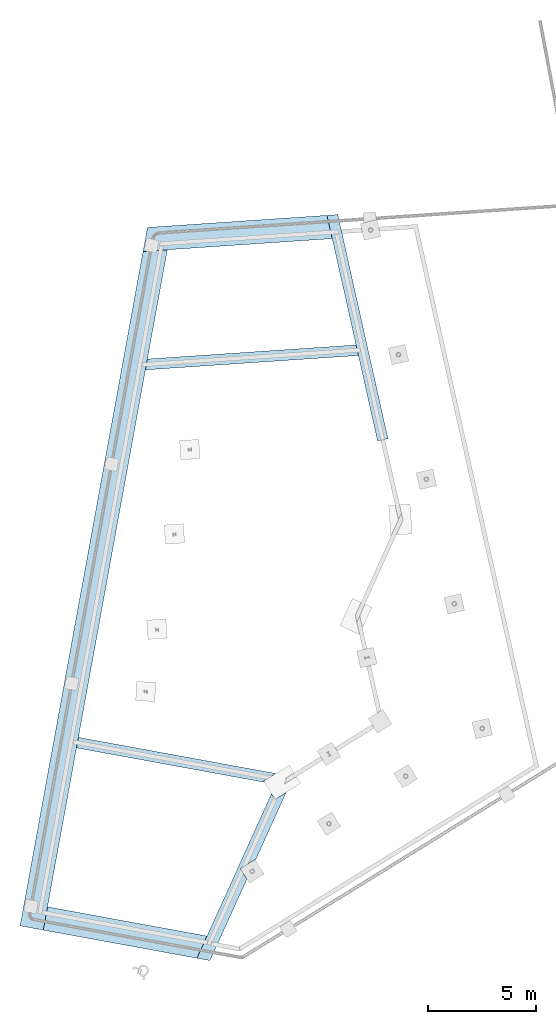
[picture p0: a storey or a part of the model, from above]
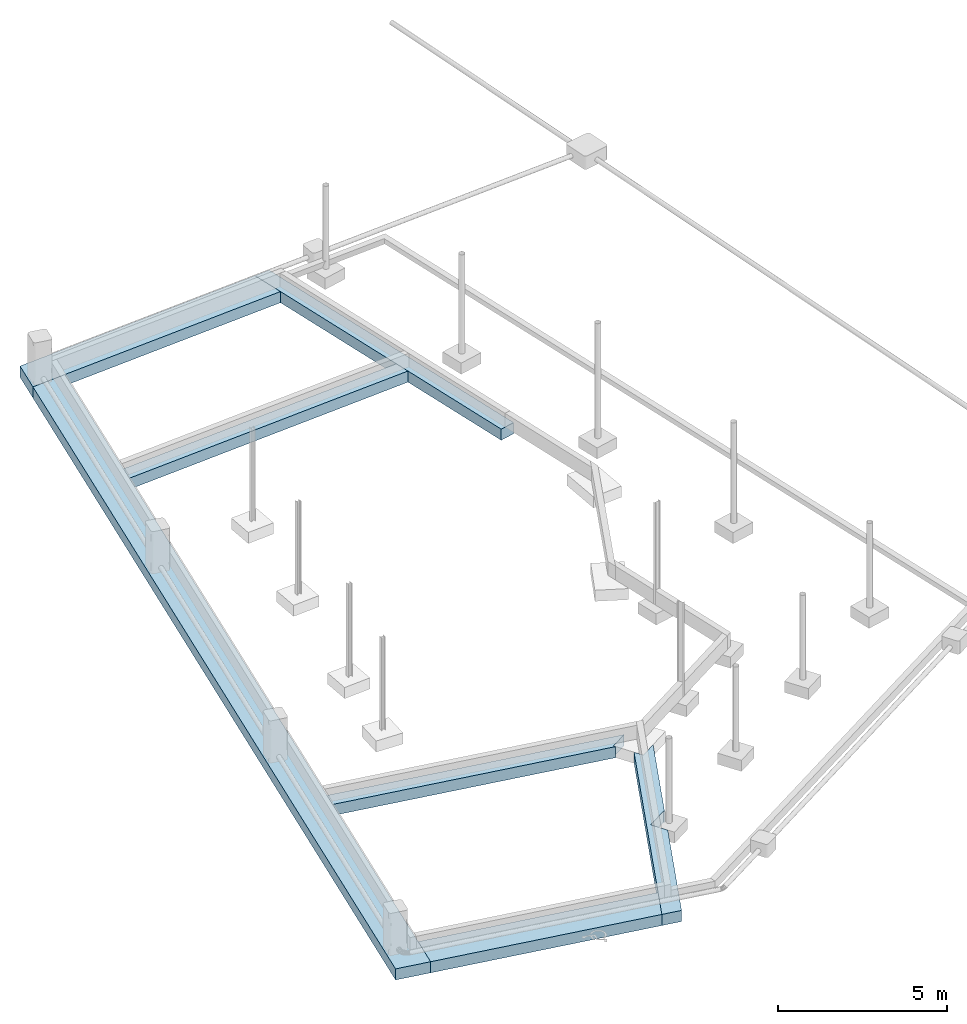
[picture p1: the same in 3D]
Properties of the parts of a building model (IFC2X3), part 1 of 5

# File
Description: ViewDefinition [CoordinationView_V2.0, QuantityTakeOffAddOnView]
File name: Maison des activités
Time: 2020-01-26T12:22:14
Written by: The EXPRESS Data Manager Version 5.02.0100.07 : 28 Aug 2013
Made in: 20180328_1600(x64) - Exporter 19.1.0.0 - Interface alternative d'export 19.1.0.0
Comment: STEP Physical File produced by: The EXPRESS Data Manager Version 5.02.0100.07 : 28 Aug 2013 * Module: EDMstepFileFactory/EDMstandAlone * Creation date: Sun Jan 26 12:22:14 2020 * Host: DESKTOP-D25JFNO * Database: C:\Users\MA392~1.JEA\AppData\Local\Temp\{6E2AF56B-D0A0-4CB7-A6A2-1DAB4A0019D9}\ifc * Database version: 5507 * Database creation date: Sun Jan 26 12:21:57 2020 * Schema: IFC2X3 * Model: DataRepository.ifc * Model creation date: Sun Jan 26 12:21:57 2020 * Header model: DataRepository.ifc_HeaderModel * Header model creation date: Sun Jan 26 12:21:57 2020 * EDMuser: sdai-user * EDMgroup: sdai-group * License ID and type: 5605 : Permanent license. Expiry date: * EDMstepFileFactory options: 020000

# IfcProject, Maison des activités
LongName: Construction d'une maison des activités; Phase: PRO

# IfcSite, Surface:1027720
RefLatitude: 43, 35, 59, 999999; RefLongitude: 1, 23, 59, 999999; RefElevation: 1.23108e-26 cm
Autre - Catégorie: Topographie; Déblais: 1000.42 m3; Déblais/remblais net: -831.129 m3; Remblais: 169.291 m3
Cotes - Surface: 22180.9 m2; Surface projetée: 21753.3 m2
Données d'identification - Nom: Terrain
Matériaux et finitions - Matériau: Site - Herbe existant
Phase de construction - Phase de création: Projet

# IfcBuilding
Pset_BuildingCommon - NumberOfStoreys: 4
Autre - Adresse du projet: LE P I G E O N N I E R 1 2 7 2 0 V E Y R E AU; Catégorie: Informations sur le projet; Etat du projet: PRO; Nom du client: Com. de Communes de Millau Grands Causses; Nom du projet: Construction d'une maison des activités; Numéro de projet: Maison des activités
Données d'identification - Auteur: Team TEB LP Millau

# IfcBuildingStorey: Niveau:Niveau (4)
Autre - Catégorie: Niveaux; Famille: Niveau: Niveau; Famille et type: Niveau: Niveau; ID du type: Niveau: Niveau; Type: Niveau: Niveau
Cotes - Hauteur de calcul: 0 cm
Données d'identification - Structure: no
Autre(Type) - Catégorie: Niveaux; Nom de la famille: Niveau
Contraintes(Type) - Base de l'élévation: Point de base du projet
Données d'identification(Type) - Nom du type: Niveau
Graphismes(Type) - Couleur: 16711680; Epaisseur des lignes: 1; Motif des lignes: Axes; Symbole: Repère de niveau - Demi-cercle: Arial 2mm; Valeur par défaut du symbole à l'extrémité 1: no; Valeur par défaut du symbole à l'extrémité 2: yes
Name | LongName | Elevation (cm) | Elévation (cm) | Etage de bâtiment | Nom
-1 Soubassement | -1 Soubassement | 86950 | 86700 | no | -2 Parking
0 RDC | 0 RDC | 87000 | 87000 | yes | 0 RDC
1 Toiture auvent | 1 Toiture auvent | 87229 | 87229 | yes | 1 Toiture auvent
2 Toiture batiment | 2 Toiture batiment | 87291 | 87291 | yes | 2 Toiture batiment

# IfcBeam: HEA260, HE-A:HEA260:1442058
In: 1 Toiture auvent
Type - PredefinedType: BEAM
Type - Analyse structurelle - Moment d'inertie de torsion: 0; Rayon d'inertie sectoriel: 0; Aire sectionnelle: 0.00868 m2; Module d'élasticité - axe faible: 0.000282 m3; Module d'élasticité - axe fort: 0.000836 m3; Module plastique - axe faible: 0.0004302 m3; Module plastique - axe fort: 0.0009198 m3; Moment d'inertie - axe faible: 0.00425213; Moment d'inertie - axe fort: 0.0121076; Périmètre: 0.451104 m2; Poids nominal: 668.811
Type - Autre - Catégorie: Ossature; Nom de la famille: HE-A
Type - Données d'identification - Identifiant du nom de la coupe: HEA260; Nom de code: EURONORM 53-62; DIN 1025-3; NF A 45-201; Nom du type: HEA260
Type - Géométrie de coupe structurelle - Centre de gravité horizontal: 13 cm; Centre de gravité vertical: 12.5 cm; Congé de l'âme: 2.4 cm; Epaisseur de l'aile: 1.25 cm; Epaisseur de l'âme: 0.75 cm; Hauteur: 25 cm; Largeur: 26 cm
Type - Structure - Forme de coupe: 8
Type - Pset_BeamCommon - IsExternal: no; Reference: HE-A:HEA260
Type - Pset_QuantityTakeOff - Reference: HE-A:HEA260
Type - Pset_ReinforcementBarPitchOfBeam - Reference: HE-A:HEA260
Material: Acier structurel - S235
BaseQuantities - GrossVolume: 0.0692697 m3; NetSurfaceArea: 12.4206 m2; NetVolume: 0.0725738 m3
Pset_BeamCommon - Span: 851.99 cm; Slope: 5.24864 deg
Pset_QuantityTakeOff - sets with these values: 2
Autre - Famille: HE-A: HEA260; Famille et type: HE-A: HEA260; ID du type: HE-A: HEA260; Type: HE-A: HEA260
Contraintes - Rotation de la section: 0 deg; Niveau de référence: Niveau: 1 Toiture auvent; Décalage du niveau d'arrivée: 125.927 cm; Décalage du niveau de départ: 47.9889 cm; Elévation du niveau de référence: 87229 cm
Cotes - Longueur: 851.99 cm; Volume: 0.0692697 m3
Matériaux et finitions - Matériau structurel: Acier structurel - S235
Phase de construction - Phase de création: Projet
Position géométrique - Etat de la jonction: Deux jonctions activées; Justification Y: Origine; Justification YZ: Uniforme; Justification Z: Haut; Valeur de décalage Y: 0 cm; Valeur de décalage Z: 0 cm
Structure - Activer le modèle analytique: yes; Emplacement du symbole filaire: Centre de la géométrie; Utilisation structurelle: Longeron; Longueur de coupe: 850.758 cm; Revêtement: -

# IfcBeam: IPE100 (9)
In: 1 Toiture auvent
Type - PredefinedType: BEAM
Type - Analyse structurelle - Moment d'inertie de torsion: 0; Rayon d'inertie sectoriel: 0; Aire sectionnelle: 0.00103 m2; Module d'élasticité - axe faible: 0.00000579 m3; Module d'élasticité - axe fort: 0.0000342 m3; Module plastique - axe faible: 0.0000092 m3; Module plastique - axe fort: 0.0000394 m3; Moment d'inertie - axe faible: 0.000018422; Moment d'inertie - axe fort: 0.000198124; Périmètre: 0.12192 m2; Poids nominal: 79.4336
Type - Autre - Catégorie: Ossature; Nom de la famille: IPE
Type - Données d'identification - Identifiant du nom de la coupe: IPE100; Nom de code: EURONORM 19-57; DIN 1025-5; NF A 45-205; Nom du type: IPE100
Type - Géométrie de coupe structurelle - Centre de gravité horizontal: 2.75 cm; Centre de gravité vertical: 5 cm; Congé de l'âme: 0.7 cm; Epaisseur de l'aile: 0.57 cm; Epaisseur de l'âme: 0.41 cm; Hauteur: 10 cm; Largeur: 5.5 cm
Type - Structure - Forme de coupe: 6
Type - Pset_BeamCommon - IsExternal: no; Reference: IPE:IPE100
Type - Pset_QuantityTakeOff - Reference: IPE:IPE100
Type - Pset_ReinforcementBarPitchOfBeam - Reference: IPE:IPE100
Material: Acier structurel - S235
Pset_QuantityTakeOff - sets with these values: 2
Autre - Famille: IPE: IPE100; Famille et type: IPE: IPE100; ID du type: IPE: IPE100; Type: IPE: IPE100
Contraintes - Niveau de référence: Niveau: 1 Toiture auvent; Elévation du niveau de référence: 87229 cm; Rotation de la section: 5 deg
Matériaux et finitions - Matériau structurel: Acier structurel - S235
Phase de construction - Phase de création: Projet
Position géométrique - Etat de la jonction: Deux jonctions activées; Justification Y: Origine; Justification YZ: Uniforme; Justification Z: Haut; Valeur de décalage Y: 0 cm; Valeur de décalage Z: 0 cm
Structure - Emplacement du symbole filaire: Centre de la géométrie; Revêtement: -
Name (IPE:IPE100:...) | GrossVolume (m3) = Volume (m3) | Span (cm) = Longueur (cm) | Slope (deg) | NetSurfaceArea (m2) | NetVolume (m3) | Décalage du niveau d'arrivée (cm) | Décalage du niveau de départ (cm) | Activer le modèle analytique | Utilisation structurelle | Longueur de coupe (cm)
1445606 | 0.00141974 | 146.88 | 0.863942 | 0.589265 | 0.00151628 | 40.841 | 43.0557 | yes | Autre | 145.336
1445995 | 0.00142019 | 146.88 | 0.864168 | 0.589265 | 0.00151628 | 55.4854 | 57.7007 | yes | Autre | 145.464
1446794 | 0.00142008 | 146.88 | 0.864382 | 0.589265 | 0.00151628 | 69.9644 | 72.1802 | yes | Poutrelle | 145.465
1447244 | 0.00141994 | 146.88 | 0.864596 | 0.589265 | 0.00151628 | 84.649 | 86.8654 | yes | Autre | 145.463
1448172 | 0.00141973 | 146.88 | 0.00315279 | 0.589265 | 0.00151628 | 99.3281 | 99.32 | no | Autre | 145.309
1448308 | 0.0014197 | 146.88 | 0.865 | 0.589265 | 0.00151628 | 113.842 | 116.059 | yes | Autre | 145.464
1448549 | 0.00141957 | 146.88 | 0.865199 | 0.589265 | 0.00151628 | 128.421 | 130.639 | yes | Autre | 145.462
1448750 | 0.00141942 | 146.87 | 0.865239 | 0.589225 | 0.00151618 | 142.959 | 145.177 | yes | Autre | 145.459
1449021 | 0.00141933 | 146.88 | 0.865617 | 0.589265 | 0.00151628 | 157.641 | 159.86 | yes | Autre | 145.464

# IfcBeam: IPE160 (57)
Type - PredefinedType: BEAM
Type - Analyse structurelle - Moment d'inertie de torsion: 0; Rayon d'inertie sectoriel: 0; Aire sectionnelle: 0.00201 m2; Module d'élasticité - axe faible: 0.0000167 m3; Module d'élasticité - axe fort: 0.000109 m3; Module plastique - axe faible: 0.0000261 m3; Module plastique - axe fort: 0.000124 m3; Moment d'inertie - axe faible: 0.0000791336; Moment d'inertie - axe fort: 0.00100684; Périmètre: 0.18989 m2; Poids nominal: 154.944
Type - Autre - Catégorie: Ossature; Nom de la famille: IPE
Type - Données d'identification - Identifiant du nom de la coupe: IPE160; Nom de code: EURONORM 19-57; DIN 1025-5; NF A 45-205; Nom du type: IPE160
Type - Géométrie de coupe structurelle - Centre de gravité horizontal: 4.1 cm; Centre de gravité vertical: 8 cm; Congé de l'âme: 0.9 cm; Epaisseur de l'aile: 0.74 cm; Epaisseur de l'âme: 0.5 cm; Hauteur: 16 cm; Largeur: 8.2 cm
Type - Structure - Forme de coupe: 6
Type - Pset_BeamCommon - IsExternal: no; Reference: IPE:IPE160
Type - Pset_QuantityTakeOff - Reference: IPE:IPE160
Type - Pset_ReinforcementBarPitchOfBeam - Reference: IPE:IPE160
Material: Acier structurel - S235
Pset_QuantityTakeOff - sets with these values: 2
Autre - Famille: IPE: IPE160; Famille et type: IPE: IPE160; ID du type: IPE: IPE160; Type: IPE: IPE160
Matériaux et finitions - Matériau structurel: Acier structurel - S235
Phase de construction - Phase de création: Projet
Position géométrique - Etat de la jonction: Deux jonctions activées; Justification Y: Origine; Justification YZ: Uniforme; Justification Z: Haut; Valeur de décalage Y: 0 cm; Valeur de décalage Z: 0 cm
Structure - Emplacement du symbole filaire: Centre de la géométrie
Name (IPE:IPE160:...) | In | GrossVolume (m3) = Volume (m3) | Span (cm) = Longueur (cm) | Slope (deg) | NetSurfaceArea (m2) | NetVolume (m3) | Niveau de référence | Décalage du niveau d'arrivée (cm) | Décalage du niveau de départ (cm) | Elévation du niveau de référence (cm) | Rotation de la section (deg) | Extension de départ (cm) | Extension de fin (cm) | Activer le modèle analytique | Utilisation structurelle | Distance d'ajustement (cm) | Longueur de coupe (cm)
1426357 | 2 Toiture batiment | 0.00786796 | 412 | 0.0000446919 | 2.53158 | 0.00814931 | Niveau: 2 Toiture batiment | 85.21 | 85.2097 | 87291 | -7 | 0 | 0 | yes | Longeron | 2 | 410.013
1426603 | 2 Toiture batiment | 0.00770232 | 402.5 | 0.000223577 | 2.47809 | 0.00797785 | Niveau: 2 Toiture batiment | 23.24 | 23.2384 | 87291 | 7 | 0 | 0 | yes | Longeron | 2 | 400.198
1426959 | 2 Toiture batiment | 0.00785297 | 411 | 0.000219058 | 2.52674 | 0.00813379 | Niveau: 2 Toiture batiment | 64.55 | 64.5484 | 87291 | 0 | 0 | 0 | yes | Longeron | 2 | 409.491
1427229 | 2 Toiture batiment | 0.00785165 | 411.5 | 0.000566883 | 2.52583 | 0.00813265 | Niveau: 2 Toiture batiment | 106.97 | 106.966 | 87291 | -7 | 0 | 0 | yes | Longeron | 2 | 409.513 | Position géométrique - Réduction du joint d'extrémité: 1.27 cm
1427360 | 2 Toiture batiment | 0.0057832 | 304 | 0.349515 | 1.8623 | 0.00598981 | Niveau: 2 Toiture batiment | 127.616 | 125.761 | 87291 | -7 | 0 | 0 | yes | Autre | 2 | 302.476 | Position géométrique - Réduction du joint de début: -10.1666 cm
1451167 | 1 Toiture auvent | 0.00810599 | 417.92 | 0.140781 | 2.55946 | 0.00824712 | Niveau: 1 Toiture auvent | 61.0967 | 60.0699 | 87229 | 5 |  |  | yes | Autre |  | 417.921 | Structure - Revêtement: -
1451210 | 1 Toiture auvent | 0.00811858 | 418.56 | 0.0898172 | 2.56213 | 0.00825576 | Niveau: 1 Toiture auvent | 74.8881 | 74.232 | 87229 | 5 |  |  | yes | Autre |  | 418.57 | Structure - Revêtement: -
1451319 | 1 Toiture auvent | 0.00818669 | 422.08 | 0.0775908 | 2.58181 | 0.00831925 | Niveau: 1 Toiture auvent | 89.4084 | 89.98 | 87229 | 5 |  |  | no | Autre |  | 422.081 | Structure - Revêtement: -
1451371 | 1 Toiture auvent | 0.00820692 | 423.12 | 0.143301 | 2.58479 | 0.00832889 | Niveau: 1 Toiture auvent | 102.996 | 104.055 | 87229 | 5 |  |  | yes | Autre |  | 423.124 | Structure - Revêtement: -
1451428 | 1 Toiture auvent | 0.00840514 | 423.75 | 0.0835391 | 2.59575 | 0.00836425 | Niveau: 1 Toiture auvent | 119.077 | 118.459 | 87229 | 5 |  |  | yes | Autre |  | 433.344 | Structure - Revêtement: -
1451463 | 1 Toiture auvent | 0.00690451 | 355.97 | 0.0839449 | 2.13152 | 0.00686604 | Niveau: 1 Toiture auvent | 133.028 | 132.506 | 87229 | 5 |  |  | no | Autre |  | 355.976 | Structure - Revêtement: -
1451555 | 1 Toiture auvent | 0.00376246 | 193.98 | 0.132089 | 1.14434 | 0.00368014 | Niveau: 1 Toiture auvent | 147.059 | 146.612 | 87229 | 5 |  |  | yes | Autre |  | 193.981 | Structure - Revêtement: -
1452370 | 1 Toiture auvent | 0.00397307 | 213.48 | 2.53689 | 1.28597 | 0.00413722 | Niveau: 1 Toiture auvent | 151.039 | 160.488 | 87229 | 5 |  |  | yes | Autre |  | 208.405 | Structure - Revêtement: -
2655009 | 2 Toiture batiment | 0.00734216 | 384 | 0.019421 | 2.36253 | 0.00760472 | Niveau: 2 Toiture batiment | 23.24 | 23.1098 | 87291 | 7 | 0 | 0 | yes | Longeron | 2 | 381.606 | Position géométrique - Réduction du joint de début: -8.5 cm
2655140 | 2 Toiture batiment | 0.00504601 | 272.1 | 0.0347731 | 1.62802 | 0.00522539 | Niveau: 2 Toiture batiment | 23.24 | 23.4051 | 87291 | 7 | 0 | 0 | yes | Longeron | 2 | 268.917 | Position géométrique - Réduction du joint de début: -10.4446 cm
2655445 | 2 Toiture batiment | 0.00845199 | 448.05 | 0.0387291 | 2.72113 | 0.00875351 | Niveau: 2 Toiture batiment | 23.24 | 23.5429 | 87291 | 7 | 0 | 0 | yes | Longeron | 2 | 444.725 | Position géométrique - Réduction du joint de début: -9.02683 cm
2655654 | 2 Toiture batiment | 0.00756356 | 402.13 | 0.0307975 | 2.43616 | 0.00783318 | Niveau: 2 Toiture batiment | 23.24 | 23.0238 | 87291 | 7 | 0 | 0 | yes | Longeron | 2 | 399.132 | Position géométrique - Réduction du joint de début: -9.7263 cm
2655850 | 2 Toiture batiment | 0.00784919 | 411 | 0.0312716 | 2.52561 | 0.00812983 | Niveau: 2 Toiture batiment | 23.24 | 23.4643 | 87291 | 7 | 0 | 0 | yes | Longeron | 2 | 409.005 | Position géométrique - Réduction du joint de début: -9.95159 cm
2656075 | 2 Toiture batiment | 0.00770148 | 402.5 | 0 | 2.47785 | 0.00797697 | Niveau: 2 Toiture batiment | 40.65 | 40.65 | 87291 | 7 | 0 | 0 | yes | Longeron | 2 | 400.133
2656185 | 2 Toiture batiment | 0.00735172 | 384.49 | 0.00250094 | 2.3656 | 0.00761461 | Niveau: 2 Toiture batiment | 40.65 | 40.6332 | 87291 | 7 | 0 | 0 | yes | Longeron | 2 | 382.095 | Position géométrique - Réduction du joint de début: -8.53366 cm
2656187 | 2 Toiture batiment | 0.00535272 | 287.91 | 0.0137888 | 1.72648 | 0.00554309 | Niveau: 2 Toiture batiment | 40.65 | 40.7193 | 87291 | 7 | 0 | 0 | yes | Longeron | 2 | 284.722 | Position géométrique - Réduction du joint de début: -10.4446 cm
2656189 | 2 Toiture batiment | 0.00845263 | 448.05 | 0.0430754 | 2.7214 | 0.00875418 | Niveau: 2 Toiture batiment | 40.65 | 40.9868 | 87291 | 7 | 0 | 0 | yes | Longeron | 2 | 445.05 | Position géométrique - Réduction du joint de début: -11.3354 cm
2656191 | 2 Toiture batiment | 0.00756327 | 402.13 | 0.0155274 | 2.43604 | 0.00783289 | Niveau: 2 Toiture batiment | 40.65 | 40.541 | 87291 | 7 | 0 | 0 | yes | Longeron | 2 | 399.132 | Position géométrique - Réduction du joint de début: -9.72814 cm
2656193 | 2 Toiture batiment | 0.00784919 | 411 | 0.0226187 | 2.52561 | 0.00812984 | Niveau: 2 Toiture batiment | 40.65 | 40.8123 | 87291 | 7 | 0 | 0 | yes | Longeron | 2 | 408.9 | Position géométrique - Réduction du joint de début: -9.24955 cm
2657622 | 2 Toiture batiment | 0.00769758 | 402.5 | 0 | 2.47661 | 0.00797292 | Niveau: 2 Toiture batiment | 64.55 | 64.55 | 87291 | 7 | 0 | 0 | yes | Longeron | 2 | 399.926
2657855 | 2 Toiture batiment | 0.00735181 | 384.5 | 0.000567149 | 2.36548 | 0.00761588 | Niveau: 2 Toiture batiment | 64.55 | 64.5538 | 87291 | 7 | 0 | 0 | yes | Longeron | 2 | 382.1 | Position géométrique - Réduction du joint de début: -8.5 cm
2658107 | 2 Toiture batiment | 0.00577078 | 309.48 | 0.0362374 | 1.86063 | 0.00597615 | Niveau: 2 Toiture batiment | 64.55 | 64.3543 | 87291 | 7 | 0 | 0 | yes | Longeron | 2 | 306.297 | Position géométrique - Réduction du joint de début: -12.3696 cm
2658297 | 2 Toiture batiment | 0.00845269 | 448.05 | 0.0318499 | 2.72142 | 0.00875424 | Niveau: 2 Toiture batiment | 64.55 | 64.7991 | 87291 | 7 | 0 | 0 | yes | Longeron | 2 | 445.05 | Position géométrique - Réduction du joint de début: -9.47143 cm
2658375 | 2 Toiture batiment | 0.00755506 | 401.79 | 0.013821 | 2.43326 | 0.00782445 | Niveau: 2 Toiture batiment | 64.55 | 64.4531 | 87291 | 7 | 0 | 0 | yes | Longeron | 2 | 398.764 | Position géométrique - Réduction du joint de début: -9.70074 cm
2658492 | 2 Toiture batiment | 0.00769545 | 402.5 | 0 | 2.47597 | 0.0079707 | Niveau: 2 Toiture batiment | 85.21 | 85.21 | 87291 | 7 | 0 | 0 | yes | Longeron | 2 | 399.79
2658655 | 2 Toiture batiment | 0.00735167 | 384.49 | 0.0193949 | 2.36559 | 0.00761457 | Niveau: 2 Toiture batiment | 85.21 | 85.3402 | 87291 | 7 | 0 | 0 | yes | Longeron | 2 | 382.094 | Position géométrique - Réduction du joint de début: -8.5 cm
2658731 | 2 Toiture batiment | 0.00613457 | 328.23 | 0.0554362 | 1.9774 | 0.00635298 | Niveau: 2 Toiture batiment | 85.21 | 84.8924 | 87291 | 7 | 0 | 0 | yes | Longeron | 2 | 325.045 | Position géométrique - Réduction du joint de début: -11.4086 cm
2658798 | 2 Toiture batiment | 0.00756188 | 402.2 | 0.00325656 | 2.43549 | 0.0078315 | Niveau: 2 Toiture batiment | 85.21 | 85.2329 | 87291 | 7 | 0 | 0 | yes | Longeron | 2 | 399.132 | Position géométrique - Réduction du joint de début: -11.3344 cm
2658959 | 2 Toiture batiment | 0.00735215 | 384.5 | 0.147819 | 2.36574 | 0.00761508 | Niveau: 2 Toiture batiment | 106.97 | 105.978 | 87291 | 7 | 0 | 0 | yes | Longeron | 2 | 382.143 | Position géométrique - Réduction du joint de début: -8.5 cm
2659129 | 2 Toiture batiment | 0.0041513 | 220 | 0 | 1.33807 | 0.00429962 | Niveau: 2 Toiture batiment | 106.97 | 106.97 | 87291 | 7 | 0 | 0 | yes | Longeron | 2 | 217.29
2659305 | 2 Toiture batiment | 0.00649006 | 346.85 | 0.278531 | 2.09106 | 0.00672139 | Niveau: 2 Toiture batiment | 106.97 | 105.284 | 87291 | 7 | 0 | 0 | yes | Longeron | 2 | 343.631 | Position géométrique - Réduction du joint de début: -8.27074 cm
2659413 | 2 Toiture batiment | 0.00844803 | 448.05 | 0.119489 | 2.71955 | 0.00874958 | Niveau: 2 Toiture batiment | 106.97 | 106.036 | 87291 | 7 | 0 | 0 | yes | Longeron | 2 | 445.051 | Position géométrique - Réduction du joint de début: -11.3354 cm
2659504 | 2 Toiture batiment | 0.00755065 | 401.9 | 0.157862 | 2.43135 | 0.0078201 | Niveau: 2 Toiture batiment | 106.97 | 105.863 | 87291 | 7 | 0 | 0 | yes | Longeron | 2 | 398.873 | Position géométrique - Réduction du joint d'extrémité: 0 cm; Réduction du joint de début: -9.89639 cm
2659623 | 2 Toiture batiment | 0.00685255 | 365.54 | 0.29131 | 2.2074 | 0.0070969 | Niveau: 2 Toiture batiment | 127.62 | 125.761 | 87291 | 7 | 0 | 0 | yes | Longeron | 2 | 362.358 | Position géométrique - Réduction du joint de début: -10.4763 cm
2660036 | 2 Toiture batiment | 0.00845088 | 447.92 | 0.0436361 | 2.72088 | 0.00875235 | Niveau: 2 Toiture batiment | 85.21 | 85.5511 | 87291 | 7 | 0 | 0 | yes | Longeron | 2 | 444.917 | Position géométrique - Réduction du joint de début: -9.88126 cm
2660176 | 2 Toiture batiment | 0.00844834 | 448.05 | 0.121896 | 2.71968 | 0.00874989 | Niveau: 2 Toiture batiment | 127.62 | 126.667 | 87291 | 7 | 0 | 0 | yes | Longeron | 2 | 445.051 | Position géométrique - Réduction du joint de début: -9.9601 cm
2660293 | 2 Toiture batiment | 0.00753281 | 398 | 0.149658 | 2.42533 | 0.00780174 | Niveau: 2 Toiture batiment | 127.62 | 126.58 | 87291 | 7 | 0 | 0 | yes | Longeron | 2 | 396.054 | Position géométrique - Réduction du joint de début: -9.97844 cm
2660359 | 2 Toiture batiment | 0.00704824 | 374 | 0 | 2.26791 | 0.00730046 | Niveau: 2 Toiture batiment | 127.62 | 127.62 | 87291 | -7 | 0 | 0 | yes | Longeron | 2 | 368.123
2660474 | 2 Toiture batiment | 0.00853167 | 448.05 | 0 | 2.74771 | 0.00883739 | Niveau: 2 Toiture batiment | 148.23 | 148.23 | 87291 | 7 | 0 | 0 | yes | Longeron | 2 | 447.035
2660672 | 2 Toiture batiment | 0.0061233 | 321.99 | 0.13478 | 1.97165 | 0.00634207 | Niveau: 2 Toiture batiment | 148.23 | 147.473 | 87291 | 7 | 0 | 0 | yes | Longeron | 2 | 320.041 | Position géométrique - Réduction du joint de début: -9.62284 cm
2660924 | 1 Toiture auvent | 0.00197774 | 92.37 | 0.441841 | 0.532687 | 0.00170616 | Niveau: 1 Toiture auvent | 117.74 | 117.028 | 87229 | 0 |  |  | yes | Autre |  | 101.966 | Structure - Revêtement: -
2661203 | 1 Toiture auvent | 0.00809422 | 417.31 | 0.058538 | 2.58187 | 0.00831945 | Niveau: 1 Toiture auvent | 89.8459 | 89.4196 | 87229 | 0 |  |  | no | Autre |  | 417.314 | Structure - Revêtement: -
2661324 | 1 Toiture auvent | 0.00806119 | 415.61 | 0.132645 | 2.54377 | 0.00819649 | Niveau: 1 Toiture auvent | 75.8575 | 74.8953 | 87229 | 0 |  |  | yes | Autre |  | 415.611 | Structure - Revêtement: -
2661588 | 1 Toiture auvent | 0.0080808 | 416.62 | 0.0968652 | 2.5513 | 0.0082208 | Niveau: 1 Toiture auvent | 61.8046 | 61.1002 | 87229 | 0 |  |  | yes | Autre |  | 416.622 | Structure - Revêtement: -
2665686 | 1 Toiture auvent | 0.00627313 | 332 | 0.102612 | 2.01747 | 0.00649806 | Niveau: 1 Toiture auvent | 61.21 | 61.8046 | 87229 | 0 | 0 | 0 | yes | Autre | 2 | 323.46 | Position géométrique - Réduction du joint de début: 1.27 cm
2666502 | 2 Toiture batiment | 0.00508501 | 268 | 0 | 1.63829 | 0.00526655 | Niveau: 2 Toiture batiment | 23.24 | 23.24 | 87291 | 7 | 0 | 0 | yes | Longeron | 2 | 266.38
2666755 | 1 Toiture auvent | 0.00500304 | 248.35 | 0.131233 | 1.50374 | 0.00484002 | Niveau: 1 Toiture auvent | 103.58 | 103.011 | 87229 | 0 |  |  | yes | Autre |  | 257.942 | Structure - Revêtement: -
2667009 | 1 Toiture auvent | 0.00336696 | 163.99 | 0.0195331 | 1.09665 | 0.00352624 | Niveau: 1 Toiture auvent | 75.4 | 75.4559 | 87229 | 0 |  |  | yes | Autre |  | 173.59 | Structure - Revêtement: -
2667447 | 2 Toiture batiment | 0.00549392 | 289.1 | 0 | 1.7695 | 0.00569014 | Niveau: 2 Toiture batiment | 40.65 | 40.65 | 87291 | 7 | 0 | 0 | yes | Longeron | 2 | 287.485
2667801 | 2 Toiture batiment | 0.00601703 | 316 | 0 | 1.93729 | 0.00623207 | Niveau: 2 Toiture batiment | 64.55 | 64.55 | 87291 | 7 | -1.77673 | 0 | yes | Longeron | 2 | 314.223
2668509 | 2 Toiture batiment | 0.00650238 | 342 | 0 | 2.09304 | 0.00673481 | Niveau: 2 Toiture batiment | 85.21 | 85.21 | 87291 | 7 | -1.77673 | 0 | yes | Longeron | 2 | 339.569
2668663 | 2 Toiture batiment | 0.00697839 | 370 | 0 | 2.24534 | 0.00722811 | Niveau: 2 Toiture batiment | 106.97 | 106.97 | 87291 | 7 | -1.77673 | 0 | yes | Longeron | 2 | 364.43

# IfcBeam: IPE180 (6)
In: 2 Toiture batiment
Type - PredefinedType: BEAM
Type - Analyse structurelle - Aire sectionnelle: 0.00239 m2; Module d'élasticité - axe faible: 0.0000222 m3; Module d'élasticité - axe fort: 0.000146 m3; Module plastique - axe faible: 0.0000346 m3; Module plastique - axe fort: 0.000166 m3; Moment d'inertie - axe faible: 0.00011702; Moment d'inertie - axe fort: 0.00152938; Moment d'inertie de torsion: 0; Périmètre: 0.21275 m2; Poids nominal: 184.364; Rayon d'inertie sectoriel: 0
Type - Autre - Catégorie: Ossature; Nom de la famille: IPE
Type - Données d'identification - Identifiant du nom de la coupe: IPE180; Nom de code: EURONORM 19-57; DIN 1025-5; NF A 45-205; Nom du type: IPE180
Type - Géométrie de coupe structurelle - Centre de gravité horizontal: 4.55 cm; Centre de gravité vertical: 9 cm; Congé de l'âme: 0.9 cm; Epaisseur de l'aile: 0.8 cm; Epaisseur de l'âme: 0.53 cm; Hauteur: 18 cm; Largeur: 9.1 cm
Type - Structure - Forme de coupe: 6
Type - Pset_BeamCommon - IsExternal: no; Reference: IPE:IPE180
Type - Pset_QuantityTakeOff - Reference: IPE:IPE180
Type - Pset_ReinforcementBarPitchOfBeam - Reference: IPE:IPE180
Material: Acier structurel - S235
Pset_QuantityTakeOff - sets with these values: 2
Autre - Famille: IPE: IPE180; Famille et type: IPE: IPE180; ID du type: IPE: IPE180; Type: IPE: IPE180
Contraintes - Elévation du niveau de référence: 87291 cm; Niveau de référence: Niveau: 2 Toiture batiment; Rotation de la section: 0 deg
Matériaux et finitions - Matériau structurel: Acier structurel - S235
Phase de construction - Phase de création: Projet
Position géométrique - Etat de la jonction: Deux jonctions activées; Justification Y: Origine; Justification YZ: Uniforme; Justification Z: Haut; Valeur de décalage Y: 0 cm; Valeur de décalage Z: 0 cm
Structure - Activer le modèle analytique: yes; Emplacement du symbole filaire: Centre de la géométrie
Name (IPE:IPE180:...) | GrossVolume (m3) = Volume (m3) | Span (cm) = Longueur (cm) | Slope (deg) | NetSurfaceArea (m2) | NetVolume (m3) | Décalage du niveau d'arrivée (cm) | Décalage du niveau de départ (cm) | Extension de départ (cm) | Extension de fin (cm) | Longueur de coupe (cm) | Utilisation structurelle
1423514 | 0.0124574 | 563 | 1.6703 | 3.7441 | 0.01283 | 52.7905 | 36.3802 | -26.2457 | -0.997768 | 535.757 | Longeron
1424207 | 0.0124723 | 537 | 1.73504 | 3.74856 | 0.0128453 | 73.6624 | 57.4034 | 0 | -0.603256 | 536.397 | Longeron
1424939 | 0.0124542 | 537 | 1.72874 | 3.74312 | 0.0128266 | 93 | 76.8 | 0 | -1.38286 | 535.617 | Longeron
1425459 | 0.0124863 | 537 | 1.76076 | 3.75277 | 0.0128598 | 112.5 | 96 | 0 | 0 | 537 | Longeron
1852149 | 0.0125145 | 590 | 1.69914 | 3.76124 | 0.0128888 | 34.0126 | 16.5183 | -25.0813 | -26.7057 | 538.213 | Longeron
1921158 | 0.00809963 | 352 | 0.950957 | 2.43603 | 0.00834187 | 7.11863 | 12.9606 | 0.108323 | -3.76699 | 348.341 | Autre

# IfcBeam: IPE220 (4)
In: 1 Toiture auvent
Type - PredefinedType: BEAM
Type - Analyse structurelle - Moment d'inertie de torsion: 0; Rayon d'inertie sectoriel: 0; Aire sectionnelle: 0.00334 m2; Module d'élasticité - axe faible: 0.0000373 m3; Module d'élasticité - axe fort: 0.000252 m3; Module plastique - axe faible: 0.0000581 m3; Module plastique - axe fort: 0.000285 m3; Moment d'inertie - axe faible: 0.000237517; Moment d'inertie - axe fort: 0.00320937; Périmètre: 0.25847 m2; Poids nominal: 256.933
Type - Autre - Catégorie: Ossature; Nom de la famille: IPE
Type - Données d'identification - Identifiant du nom de la coupe: IPE220; Nom de code: EURONORM 19-57; DIN 1025-5; NF A 45-205; Nom du type: IPE220
Type - Géométrie de coupe structurelle - Centre de gravité horizontal: 5.5 cm; Centre de gravité vertical: 11 cm; Congé de l'âme: 1.2 cm; Epaisseur de l'aile: 0.92 cm; Epaisseur de l'âme: 0.59 cm; Hauteur: 22 cm; Largeur: 11 cm
Type - Structure - Forme de coupe: 6
Type - Pset_BeamCommon - IsExternal: no; Reference: IPE:IPE220
Type - Pset_QuantityTakeOff - Reference: IPE:IPE220
Type - Pset_ReinforcementBarPitchOfBeam - Reference: IPE:IPE220
Material: Acier structurel - S235
Pset_QuantityTakeOff - sets with these values: 2
Autre - Famille: IPE: IPE220; Famille et type: IPE: IPE220; ID du type: IPE: IPE220; Type: IPE: IPE220
Contraintes - Elévation du niveau de référence: 87229 cm; Niveau de référence: Niveau: 1 Toiture auvent
Matériaux et finitions - Matériau structurel: Acier structurel - S235
Phase de construction - Phase de création: Projet
Position géométrique - Etat de la jonction: Deux jonctions activées; Justification Y: Origine; Justification YZ: Uniforme; Justification Z: Haut; Valeur de décalage Y: 0 cm; Valeur de décalage Z: 0 cm
Structure - Activer le modèle analytique: yes; Emplacement du symbole filaire: Centre de la géométrie; Revêtement: -
Name (IPE:IPE220:...) | GrossVolume (m3) = Volume (m3) | Span (cm) = Longueur (cm) | Slope (deg) | NetSurfaceArea (m2) | NetVolume (m3) | Rotation de la section (deg) | Décalage du niveau d'arrivée (cm) | Décalage du niveau de départ (cm) | Utilisation structurelle | Longueur de coupe (cm)
1434282 | 0.0391287 | 1217.65 | 5.62232 | 10.2632 | 0.0404022 | 0 | 159.294 | 40 | Autre | 1217.66
1435283 | 0.0379793 | 1177.96 | 5.42628 | 9.90917 | 0.0390075 | 0 | 47.9 | 159.294 | Longeron | 1185.52
1435941 | 0.0431707 | 1343.44 | 0.00589968 | 11.2565 | 0.0442916 | 5 | 48.0832 | 47.9449 | Longeron | 1343.44
1443118 | 0.0144115 | 453.51 | 5.29022 | 3.77468 | 0.0148428 | 0 | 89.8459 | 48.032 | Autre | 452.247

# IfcBeam: IPE360, IPE:IPE360:1431222
In: 2 Toiture batiment
Type - PredefinedType: BEAM
Type - Analyse structurelle - Moment d'inertie de torsion: 0; Rayon d'inertie sectoriel: 0; Aire sectionnelle: 0.00727 m2; Module d'élasticité - axe faible: 0.000123 m3; Module d'élasticité - axe fort: 0.000904 m3; Module plastique - axe faible: 0.000191 m3; Module plastique - axe fort: 0.001019 m3; Moment d'inertie - axe faible: 0.00120496; Moment d'inertie - axe fort: 0.0188507; Périmètre: 0.41148 m2; Poids nominal: 559.958
Type - Autre - Catégorie: Ossature; Nom de la famille: IPE
Type - Données d'identification - Identifiant du nom de la coupe: IPE360; Nom de code: EURONORM 19-57; DIN 1025-5; NF A 45-205; Nom du type: IPE360
Type - Géométrie de coupe structurelle - Centre de gravité horizontal: 8.5 cm; Centre de gravité vertical: 18 cm; Congé de l'âme: 1.8 cm; Epaisseur de l'aile: 1.27 cm; Epaisseur de l'âme: 0.8 cm; Hauteur: 36 cm; Largeur: 17 cm
Type - Structure - Forme de coupe: 6
Type - Pset_BeamCommon - IsExternal: no; Reference: IPE:IPE360
Type - Pset_QuantityTakeOff - Reference: IPE:IPE360
Type - Pset_ReinforcementBarPitchOfBeam - Reference: IPE:IPE360
Material: Acier structurel - S235
BaseQuantities - GrossVolume: 0.0632203 m3; NetSurfaceArea: 12.2441 m2; NetVolume: 0.0657702 m3
Pset_BeamCommon - Span: 906 cm; Slope: 6.89083 deg
Pset_QuantityTakeOff - sets with these values: 2
Autre - Famille: IPE: IPE360; Famille et type: IPE: IPE360; ID du type: IPE: IPE360; Type: IPE: IPE360
Contraintes - Niveau de référence: Niveau: 2 Toiture batiment; Rotation de la section: 0 deg; Décalage du niveau d'arrivée: 3.57495 cm; Décalage du niveau de départ: 112.275 cm; Elévation du niveau de référence: 87291 cm
Cotes - Longueur: 906 cm; Volume: 0.0632203 m3
Matériaux et finitions - Matériau structurel: Acier structurel - S235
Phase de construction - Phase de création: Projet
Position géométrique - Etat de la jonction: Deux jonctions activées; Justification Y: Origine; Justification YZ: Uniforme; Justification Z: Haut; Valeur de décalage Y: 0 cm; Valeur de décalage Z: 0 cm; Extension de départ: -4.31116 cm; Extension de fin: 2.12979 cm
Structure - Activer le modèle analytique: yes; Emplacement du symbole filaire: Centre de la géométrie; Utilisation structurelle: Longeron; Longueur de coupe: 903.819 cm

# IfcBeam: IPE450 (4)
In: 2 Toiture batiment
Type - PredefinedType: BEAM
Type - Analyse structurelle - Moment d'inertie de torsion: 0; Rayon d'inertie sectoriel: 0; Aire sectionnelle: 0.00988 m2; Module d'élasticité - axe faible: 0.000176 m3; Module d'élasticité - axe fort: 0.0015 m3; Module plastique - axe faible: 0.000276 m3; Module plastique - axe fort: 0.001702 m3; Moment d'inertie - axe faible: 0.00194648; Moment d'inertie - axe fort: 0.0390918; Périmètre: 0.490728 m2; Poids nominal: 760.993
Type - Autre - Catégorie: Ossature; Nom de la famille: IPE
Type - Données d'identification - Identifiant du nom de la coupe: IPE450; Nom de code: EURONORM 19-57; DIN 1025-5; NF A 45-205; Nom du type: IPE450
Type - Géométrie de coupe structurelle - Centre de gravité horizontal: 9.5 cm; Centre de gravité vertical: 22.5 cm; Congé de l'âme: 2.1 cm; Epaisseur de l'aile: 1.46 cm; Epaisseur de l'âme: 0.94 cm; Hauteur: 45 cm; Largeur: 19 cm
Type - Structure - Forme de coupe: 6
Type - Pset_BeamCommon - IsExternal: no; Reference: IPE:IPE450
Type - Pset_QuantityTakeOff - Reference: IPE:IPE450
Type - Pset_ReinforcementBarPitchOfBeam - Reference: IPE:IPE450
Material: Acier structurel - S235
Pset_QuantityTakeOff - sets with these values: 2
Autre - Famille: IPE: IPE450; Famille et type: IPE: IPE450; ID du type: IPE: IPE450; Type: IPE: IPE450
Contraintes - Niveau de référence: Niveau: 2 Toiture batiment; Rotation de la section: 0 deg; Elévation du niveau de référence: 87291 cm
Matériaux et finitions - Matériau structurel: Acier structurel - S235
Phase de construction - Phase de création: Projet
Position géométrique - Etat de la jonction: Deux jonctions activées; Justification Y: Origine; Justification YZ: Uniforme; Justification Z: Haut; Valeur de décalage Y: 0 cm; Valeur de décalage Z: 0 cm
Structure - Activer le modèle analytique: yes; Emplacement du symbole filaire: Centre de la géométrie; Revêtement: -
Name (IPE:IPE450:...) | GrossVolume (m3) = Volume (m3) | Span (cm) = Longueur (cm) | Slope (deg) | NetSurfaceArea (m2) | NetVolume (m3) | Décalage du niveau d'arrivée (cm) | Décalage du niveau de départ (cm) | Utilisation structurelle | Longueur de coupe (cm)
1427679 | 0.114945 | 1209.5 | 6.6135 | 19.5276 | 0.120112 | 3.33906 | 142.639 | Longeron | 1209.5
1428650 | 0.129866 | 1366.5 | 6.67744 | 22.0971 | 0.135933 | 2.90392 | 161.8 | Longeron | 1366.5
1429455 | 0.117802 | 1239.56 | 6.64979 | 19.9841 | 0.122923 | 3.5 | 147.042 | Autre | 1239.56
1429862 | 0.106256 | 1118.06 | 6.739 | 17.9473 | 0.110383 | 3.5 | 134.701 | Autre | 1118.07

# IfcBuildingElementPart (222)
Autre - Catégorie: Eléments
Cotes - Exclusion: no
Données d'identification - Matériau par origine: yes
Phase de construction - Phase de création: Projet; Phase de création par origine: yes; Phase de démolition par origine: yes
Name (Elément:...) | In | Material = Matériau | Niveau de base | Epaisseur (cm) | Hauteur (cm) | La forme a été modifiée | Longueur (cm) | Surface (m2) | Volume (m3) | Afficher des poignées de la forme | Catégorie d'origine | Construction | Famille d'origine | Type d'origine
1858975 | 0 RDC | Isolant Laine minérale 45mm | Niveau: 0 RDC | 4.8 | 331.463 | no | 120 | 1.89015 | 0.0907273 | yes | Murs | Noyau | Mur de base | Cloison de séparation 98/48 à ossature métal avec laine minérale
1858976 | 0 RDC | Plâtre BA25 | Niveau: 0 RDC | 2.5 | 331.763 | no | 112.7 | 1.66228 | 0.0415569 | no | Murs | Finition | Mur de base | Cloison de séparation 98/48 à ossature métal avec laine minérale
1858977 | 0 RDC | Plâtre BA25 | Niveau: 0 RDC | 2.5 | 330.887 | no | 120 | 1.89384 | 0.0473461 | no | Murs | Finition | Mur de base | Cloison de séparation 98/48 à ossature métal avec laine minérale
2182440 | 2 Toiture batiment | Bac acier | Niveau: 2 Toiture batiment | 1.5 |  | no |  | 379.293 | 5.68939 | no | Toits | Finition | Toit de base | Couverture bac acier double peau
2182441 | 2 Toiture batiment | Isolant Laine minérale 140mm | Niveau: 2 Toiture batiment | 14 |  | no |  | 379.293 | 53.101 | no | Toits | Noyau | Toit de base | Couverture bac acier double peau
2182442 | 2 Toiture batiment | Pare vapeur feutre alu tendu | Niveau: 2 Toiture batiment | 8 |  | no |  | 379.293 | 30.3434 | no | Toits | Noyau | Toit de base | Couverture bac acier double peau
2182443 | 2 Toiture batiment | Isolant Laine minairale 70mm | Niveau: 2 Toiture batiment | 7 |  | no |  | 379.293 | 26.5505 | no | Toits | Noyau | Toit de base | Couverture bac acier double peau
2182444 | 2 Toiture batiment | Bac acier | Niveau: 2 Toiture batiment | 1.5 |  | no |  | 379.293 | 5.68939 | no | Toits | Finition | Toit de base | Couverture bac acier double peau
1858782 | 0 RDC | Isolant Laine minérale 45mm | Niveau: 0 RDC | 4.8 | 404.963 | yes | 690.572 | 23.2508 | 1.11604 | yes | Murs | Noyau | Mur de base | Cloison de séparation 98/48 à ossature métal avec laine minérale
1858783 | 0 RDC | Plâtre BA25 | Niveau: 0 RDC | 2.5 | 404.738 | yes | 689.811 | 23.2651 | 0.581627 | yes | Murs | Finition | Mur de base | Cloison de séparation 98/48 à ossature métal avec laine minérale
1882766 | 0 RDC | Plâtre BA25 | Niveau: 0 RDC | 2.5 | 378.049 | yes | 458.5 | 14.211 | 0.355275 | yes | Murs | Finition | Mur de base | Cloison de séparation 98/48 à ossature métal avec laine minérale
1882767 | 0 RDC | Plâtre BA25 | Niveau: 0 RDC | 2.5 | 404.084 | yes | 227.636 | 8.88842 | 0.222211 | yes | Murs | Finition | Mur de base | Cloison de séparation 98/48 à ossature métal avec laine minérale
2184018 | 0 RDC | Béton dallage | Niveau: 0 RDC | 18 |  | yes |  | 180.198 | 32.4357 | yes | Sols | Noyau | Sol | Dallage Terrasse
1858825 | 0 RDC | Isolant Laine minérale 45mm | Niveau: 0 RDC | 4.8 | 331.887 | yes | 274.729 | 8.665 | 0.41592 | yes | Murs | Noyau | Mur de base | Cloison de séparation 98/48 à ossature métal avec laine minérale
1858826 | 0 RDC | Plâtre BA25 | Niveau: 0 RDC | 2.5 | 330.887 | yes | 125.4 | 4.05497 | 0.101374 | yes | Murs | Finition | Mur de base | Cloison de séparation 98/48 à ossature métal avec laine minérale
1858827 | 0 RDC | Plâtre BA25 | Niveau: 0 RDC | 2.5 | 331.887 | yes | 273.426 | 8.62605 | 0.215651 | yes | Murs | Finition | Mur de base | Cloison de séparation 98/48 à ossature métal avec laine minérale
1858840 | 0 RDC | Plâtre BA25 | Niveau: 0 RDC | 2.5 | 316.263 | yes | 143.231 | 4.40676 | 0.110169 | yes | Murs | Finition | Mur de base | Cloison de séparation 98/48 à ossature métal avec laine minérale
1858808 | 0 RDC | Isolant Laine minérale 45mm | Niveau: 0 RDC | 4.8 | 331.887 | yes | 275.325 | 8.6828 | 0.416774 | yes | Murs | Noyau | Mur de base | Cloison de séparation 98/48 à ossature métal avec laine minérale
1858809 | 0 RDC | Plâtre BA25 | Niveau: 0 RDC | 2.5 | 331.887 | yes | 274.027 | 8.64402 | 0.2161 | yes | Murs | Finition | Mur de base | Cloison de séparation 98/48 à ossature métal avec laine minérale
1858810 | 0 RDC | Plâtre BA25 | Niveau: 0 RDC | 2.5 | 331.887 | yes | 274.021 | 8.64386 | 0.216096 | yes | Murs | Finition | Mur de base | Cloison de séparation 98/48 à ossature métal avec laine minérale
2252366 | 0 RDC | Isolant Laine minérale 45mm | Niveau: 0 RDC | 4.8 | 365.762 | yes | 859.704 | 23.2232 | 1.11471 | yes | Murs | Noyau | Mur de base | Cloison de séparation 98/48 à ossature métal avec laine minérale
2252367 | 0 RDC | Plâtre BA25 | Niveau: 0 RDC | 2.5 | 364.837 | yes | 410.579 | 13.9155 | 0.347887 | yes | Murs | Finition | Mur de base | Cloison de séparation 98/48 à ossature métal avec laine minérale
2252368 | 0 RDC | Plâtre BA25 | Niveau: 0 RDC | 2.5 | 365.618 | yes | 857.517 | 24.9374 | 0.623435 | yes | Murs | Finition | Mur de base | Cloison de séparation 98/48 à ossature métal avec laine minérale
2595301 | 0 RDC | Plâtre BA25 | Niveau: 0 RDC | 2.5 | 294.513 | no | 157.6 | 4.49228 | 0.112307 | yes | Murs | Finition | Mur de base | Cloison de séparation 98/48 à ossature métal avec laine minérale
2595302 | 0 RDC | Plâtre BA25 | Niveau: 0 RDC | 2.5 | 315.919 | yes | 165 | 3.10422 | 0.0776056 | yes | Murs | Finition | Mur de base | Cloison de séparation 98/48 à ossature métal avec laine minérale
2624165 | 0 RDC | Plâtre BA25 | Niveau: 0 RDC | 2.5 | 276.141 | yes | 112.963 | 3.04267 | 0.0760667 | yes | Murs | Finition | Mur de base | Cloison de séparation 98/48 à ossature métal avec laine minérale
1858795 | 0 RDC | Isolant Laine minérale 45mm | Niveau: 0 RDC | 4.8 | 382.916 | yes | 182.41 | 6.93038 | 0.332658 | yes | Murs | Noyau | Mur de base | Cloison de séparation 98/48 à ossature métal avec laine minérale
1858796 | 0 RDC | Plâtre BA25 | Niveau: 0 RDC | 2.5 | 383.186 | yes | 174.084 | 6.62343 | 0.165586 | yes | Murs | Finition | Mur de base | Cloison de séparation 98/48 à ossature métal avec laine minérale
1858797 | 0 RDC | Plâtre BA25 | Niveau: 0 RDC | 2.5 | 383.035 | no | 174.084 | 6.6208 | 0.16552 | yes | Murs | Finition | Mur de base | Cloison de séparation 98/48 à ossature métal avec laine minérale
1858988 | 0 RDC | Isolant Laine minérale 45mm | Niveau: 0 RDC | 4.8 | 352.839 | yes | 382.937 | 11.4057 | 0.547472 | yes | Murs | Noyau | Mur de base | Cloison de séparation 98/48 à ossature métal avec laine minérale
1858989 | 0 RDC | Plâtre BA25 | Niveau: 0 RDC | 2.5 | 352.263 | yes | 257.137 | 9.05413 | 0.226353 | yes | Murs | Finition | Mur de base | Cloison de séparation 98/48 à ossature métal avec laine minérale
1858990 | 0 RDC | Plâtre BA25 | Niveau: 0 RDC | 2.5 | 352.263 | yes | 112.7 | 1.88331 | 0.0470828 | yes | Murs | Finition | Mur de base | Cloison de séparation 98/48 à ossature métal avec laine minérale
1858991 | 0 RDC | Plâtre BA25 | Niveau: 0 RDC | 2.5 | 353.139 | yes | 374.637 | 11.1387 | 0.278466 | yes | Murs | Finition | Mur de base | Cloison de séparation 98/48 à ossature métal avec laine minérale
1858872 | 0 RDC | vide | Niveau: 0 RDC | 0.3 | 331.887 | yes | 274.649 | 6.57681 | 0.0197304 | yes | Murs | Finition | Mur de base | Cloison de distribution 72/48 à ossature métal avec laine minérale
1858873 | 0 RDC | vide | Niveau: 0 RDC | 0.3 | 331.887 | yes | 274.647 | 6.57674 | 0.0197302 | yes | Murs | Finition | Mur de base | Cloison de distribution 72/48 à ossature métal avec laine minérale
1858874 | 0 RDC | Plâtre BA18 | Niveau: 0 RDC | 1.8 | 331.887 | yes | 273.351 | 6.53797 | 0.117683 | yes | Murs | Finition | Mur de base | Cloison de distribution 72/48 à ossature métal avec laine minérale
1858875 | 0 RDC | Isolant Laine minérale haute densité 40mm | Niveau: 0 RDC | 3 | 331.887 | yes | 274.649 | 6.57678 | 0.197303 | yes | Murs | Noyau | Mur de base | Cloison de distribution 72/48 à ossature métal avec laine minérale
1858876 | 0 RDC | Plâtre BA18 | Niveau: 0 RDC | 1.8 | 331.887 | yes | 273.347 | 6.53869 | 0.117696 | yes | Murs | Finition | Mur de base | Cloison de distribution 72/48 à ossature métal avec laine minérale
1858893 | 0 RDC | vide | Niveau: 0 RDC | 0.3 | 301 | yes | 102.168 | 3.07526 | 0.00922577 | yes | Murs | Finition | Mur de base | Cloison de distribution 72/48 à ossature métal avec laine minérale
1858894 | 0 RDC | vide | Niveau: 0 RDC | 0.3 | 301 | yes | 102.171 | 3.07533 | 0.00922599 | yes | Murs | Finition | Mur de base | Cloison de distribution 72/48 à ossature métal avec laine minérale
1858895 | 0 RDC | Plâtre BA18 | Niveau: 0 RDC | 1.8 | 301 | yes | 100.868 | 3.0361 | 0.0546499 | yes | Murs | Finition | Mur de base | Cloison de distribution 72/48 à ossature métal avec laine minérale
1858896 | 0 RDC | Isolant Laine minérale haute densité 40mm | Niveau: 0 RDC | 3 | 301 | yes | 102.17 | 3.07529 | 0.0922588 | yes | Murs | Noyau | Mur de base | Cloison de distribution 72/48 à ossature métal avec laine minérale
1858897 | 0 RDC | Plâtre BA18 | Niveau: 0 RDC | 1.8 | 301 | yes | 100.872 | 3.03622 | 0.054652 | yes | Murs | Finition | Mur de base | Cloison de distribution 72/48 à ossature métal avec laine minérale
1858968 | 0 RDC | Isolant Laine minérale 45mm | Niveau: 0 RDC | 4.8 | 352.263 | yes | 165 | 5.64903 | 0.271153 | yes | Murs | Noyau | Mur de base | Cloison de séparation 98/48 à ossature métal avec laine minérale
1858969 | 0 RDC | Plâtre BA25 | Niveau: 0 RDC | 2.5 | 351.963 | yes | 167.3 | 5.72072 | 0.143018 | yes | Murs | Finition | Mur de base | Cloison de séparation 98/48 à ossature métal avec laine minérale
1858970 | 0 RDC | Plâtre BA25 | Niveau: 0 RDC | 2.5 | 351.963 | yes | 160 | 5.47781 | 0.136945 | yes | Murs | Finition | Mur de base | Cloison de séparation 98/48 à ossature métal avec laine minérale
1858715 | 0 RDC | Isolant Laine minérale 45mm | Niveau: 0 RDC | 4.8 | 332.463 | yes | 1836.11 | 47.6019 | 2.28489 | yes | Murs | Noyau | Mur de base | Cloison de séparation 98/48 à ossature métal avec laine minérale
1858716 | 0 RDC | Plâtre BA25 | Niveau: 0 RDC | 2.5 | 332.763 | yes | 1835.4 | 47.6685 | 1.19171 | yes | Murs | Finition | Mur de base | Cloison de séparation 98/48 à ossature métal avec laine minérale
2598077 | 0 RDC | Plâtre BA25 | Niveau: 0 RDC | 2.5 | 330.887 | yes | 5.8 | 0.191797 | 0.00479492 | yes | Murs | Finition | Mur de base | Cloison de séparation 98/48 à ossature métal avec laine minérale
2682655 | 0 RDC | Plâtre BA25 | Niveau: 0 RDC | 2.5 | 255 | no | 20 | 0.509977 | 0.0127494 | no | Murs | Finition | Mur de base | Cloison de séparation 98/48 à ossature métal avec laine minérale
2683542 | 0 RDC | Plâtre BA25 | Niveau: 0 RDC | 2.5 | 330.887 | no | 255.763 | 6.38402 | 0.159601 | no | Murs | Finition | Mur de base | Cloison de séparation 98/48 à ossature métal avec laine minérale
2683543 | 0 RDC | Plâtre BA25 | Niveau: 0 RDC | 2.5 | 330.887 | no | 99.9 | 3.30406 | 0.0826015 | no | Murs | Finition | Mur de base | Cloison de séparation 98/48 à ossature métal avec laine minérale
2826877 | 0 RDC | Plâtre BA25 | Niveau: 0 RDC | 2.5 | 330.887 | no | 190.1 | 4.21231 | 0.105308 | no | Murs | Finition | Mur de base | Cloison de séparation 98/48 à ossature métal avec laine minérale
2826878 | 0 RDC | Plâtre BA25 | Niveau: 0 RDC | 2.5 | 330.887 | no | 600.3 | 15.9739 | 0.399347 | no | Murs | Finition | Mur de base | Cloison de séparation 98/48 à ossature métal avec laine minérale
2826879 | 0 RDC | Plâtre BA25 | Niveau: 0 RDC | 2.5 | 330.887 | no | 650.885 | 16.3292 | 0.40823 | no | Murs | Finition | Mur de base | Cloison de séparation 98/48 à ossature métal avec laine minérale
1858923 | 0 RDC | vide | Niveau: 0 RDC | 0.3 | 300 | no | 377.336 | 7.57901 | 0.022737 | no | Murs | Finition | Mur de base | Cloison de distribution 72/48 à ossature métal avec laine minérale
1858924 | 0 RDC | vide | Niveau: 0 RDC | 0.3 | 300 | no | 184.8 | 3.67045 | 0.0110113 | no | Murs | Finition | Mur de base | Cloison de distribution 72/48 à ossature métal avec laine minérale
1858925 | 0 RDC | Plâtre BA18 | Niveau: 0 RDC | 1.8 | 300 | no | 376.636 | 7.56407 | 0.136153 | no | Murs | Finition | Mur de base | Cloison de distribution 72/48 à ossature métal avec laine minérale
1858926 | 0 RDC | Isolant Laine minérale haute densité 40mm | Niveau: 0 RDC | 3 | 300 | no | 377.036 | 7.57001 | 0.2271 | no | Murs | Noyau | Mur de base | Cloison de distribution 72/48 à ossature métal avec laine minérale
1858927 | 0 RDC | Plâtre BA18 | Niveau: 0 RDC | 1.8 | 301 | yes | 182 | 3.59272 | 0.064669 | yes | Murs | Finition | Mur de base | Cloison de distribution 72/48 à ossature métal avec laine minérale
2624271 | 0 RDC | vide | Niveau: 0 RDC | 0.3 | 300 | no | 186.236 | 3.71957 | 0.0111587 | no | Murs | Finition | Mur de base | Cloison de distribution 72/48 à ossature métal avec laine minérale
2624272 | 0 RDC | Plâtre BA18 | Niveau: 0 RDC | 1.8 | 300 | no | 185.636 | 3.70157 | 0.0666282 | no | Murs | Finition | Mur de base | Cloison de distribution 72/48 à ossature métal avec laine minérale
1858942 | 0 RDC | vide | Niveau: 0 RDC | 0.3 | 301 | yes | 113.099 | 3.40429 | 0.0102129 | yes | Murs | Finition | Mur de base | Cloison de distribution 72/48 à ossature métal avec laine minérale
1858943 | 0 RDC | vide | Niveau: 0 RDC | 0.3 | 301 | yes | 113.097 | 3.40421 | 0.0102126 | yes | Murs | Finition | Mur de base | Cloison de distribution 72/48 à ossature métal avec laine minérale
1858944 | 0 RDC | Plâtre BA18 | Niveau: 0 RDC | 1.8 | 301 | yes | 110.001 | 3.311 | 0.059598 | yes | Murs | Finition | Mur de base | Cloison de distribution 72/48 à ossature métal avec laine minérale
1858945 | 0 RDC | Isolant Laine minérale haute densité 40mm | Niveau: 0 RDC | 3 | 301 | yes | 113.399 | 3.41328 | 0.102398 | yes | Murs | Noyau | Mur de base | Cloison de distribution 72/48 à ossature métal avec laine minérale
1858946 | 0 RDC | Plâtre BA18 | Niveau: 0 RDC | 1.8 | 301 | yes | 109.997 | 3.31088 | 0.0595959 | yes | Murs | Finition | Mur de base | Cloison de distribution 72/48 à ossature métal avec laine minérale
2608668 | 0 RDC | Plâcoplatre plafond | Niveau: 0 RDC | 1.5 |  | no |  | 19.1008 | 0.286511 | no | Plafonds | Noyau | Plafond composé | Plafond Placo non démontable
2608669 | 0 RDC | Plâcoplatre plafond | Niveau: 0 RDC | 1.5 |  | no |  | 19.1008 | 0.286511 | no | Plafonds | Noyau | Plafond composé | Plafond Placo non démontable
2608653 | 0 RDC | Isolant Laine minérale haute densité 40mm | Niveau: 0 RDC | 4 |  | no |  | 1.9809 | 0.0792361 | no | Plafonds | Noyau | Plafond composé | Plafond Rayonnant H Dalle 60 x 60
2608654 | 0 RDC | Plâcoplatre plafond | Niveau: 0 RDC | 0.65 |  | no |  | 2.70616 | 0.0175901 | no | Plafonds | Noyau | Plafond composé | Plafond Rayonnant H Dalle 60 x 60
2633709 | 0 RDC | Isolant Laine minérale haute densité 40mm | Niveau: 0 RDC | 4 |  | no |  | 2.00481 | 0.0801926 | no | Plafonds | Noyau | Plafond composé | Plafond Rayonnant H Dalle 60 x 60
2633710 | 0 RDC | Isolant Laine minérale haute densité 40mm | Niveau: 0 RDC | 4 |  | no |  | 2.70616 | 0.108247 | no | Plafonds | Noyau | Plafond composé | Plafond Rayonnant H Dalle 60 x 60
2633711 | 0 RDC | Plâcoplatre plafond | Niveau: 0 RDC | 0.65 |  | no |  | 2.00481 | 0.0130313 | no | Plafonds | Noyau | Plafond composé | Plafond Rayonnant H Dalle 60 x 60
2633712 | 0 RDC | Plâcoplatre plafond | Niveau: 0 RDC | 0.65 |  | no |  | 1.9809 | 0.0128759 | no | Plafonds | Noyau | Plafond composé | Plafond Rayonnant H Dalle 60 x 60
2634302 | 0 RDC | Isolant Laine minérale haute densité 40mm | Niveau: 0 RDC | 4 |  | no |  | 4.1404 | 0.165616 | no | Plafonds | Noyau | Plafond composé | Plafond Rayonnant H Dalle 60 x 60
2634303 | 0 RDC | Isolant Laine minérale haute densité 40mm | Niveau: 0 RDC | 4 |  | no |  | 13.2706 | 0.530823 | no | Plafonds | Noyau | Plafond composé | Plafond Rayonnant H Dalle 60 x 60
2634304 | 0 RDC | Plâcoplatre plafond | Niveau: 0 RDC | 0.65 |  | no |  | 4.1404 | 0.0269126 | no | Plafonds | Noyau | Plafond composé | Plafond Rayonnant H Dalle 60 x 60
2634305 | 0 RDC | Plâcoplatre plafond | Niveau: 0 RDC | 0.65 |  | no |  | 13.2706 | 0.0862587 | no | Plafonds | Noyau | Plafond composé | Plafond Rayonnant H Dalle 60 x 60
2608660 | 0 RDC | Plastique blanc | Niveau: 0 RDC | 0.1 |  | no |  | 16.9877 | 0.0169877 | no | Plafonds | Finition | Plafond composé | Plafond Dalle 60 x 60 "Hygiène & Acoustique"
2608661 | 0 RDC | Isolant Laine minérale 20mm | Niveau: 0 RDC | 1.8 |  | no |  | 16.9877 | 0.305778 | no | Plafonds | Noyau | Plafond composé | Plafond Dalle 60 x 60 "Hygiène & Acoustique"
2608662 | 0 RDC | Plastique blanc | Niveau: 0 RDC | 0.1 |  | no |  | 16.9877 | 0.0169877 | no | Plafonds | Finition | Plafond composé | Plafond Dalle 60 x 60 "Hygiène & Acoustique"
2608656 | 0 RDC | Isolant Laine minérale haute densité 40mm | Niveau: 0 RDC | 4 |  | no |  | 1.7632 | 0.070528 | no | Plafonds | Noyau | Plafond composé | Plafond Rayonnant H Dalle 60 x 60
2608657 | 0 RDC | Plâcoplatre plafond | Niveau: 0 RDC | 0.65 |  | no |  | 1.7632 | 0.0114608 | no | Plafonds | Noyau | Plafond composé | Plafond Rayonnant H Dalle 60 x 60
2608683 | 0 RDC | Plâcoplatre plafond | Niveau: 0 RDC | 1.5 |  | no |  | 7.89474 | 0.118421 | no | Plafonds | Noyau | Plafond composé | Plafond Placo non démontable
2608684 | 0 RDC | Plâcoplatre plafond | Niveau: 0 RDC | 1.5 |  | no |  | 7.89474 | 0.118421 | no | Plafonds | Noyau | Plafond composé | Plafond Placo non démontable
2608687 | 0 RDC | Isolant Laine minérale haute densité 40mm | Niveau: 0 RDC | 4 |  | no |  | 4.23135 | 0.169254 | no | Plafonds | Noyau | Plafond composé | Plafond Rayonnant H Dalle 60 x 60
2608688 | 0 RDC | Plâcoplatre plafond | Niveau: 0 RDC | 0.65 |  | no |  | 4.23135 | 0.0275038 | no | Plafonds | Noyau | Plafond composé | Plafond Rayonnant H Dalle 60 x 60
1858857 | 0 RDC | Isolant Laine minérale 45mm | Niveau: 0 RDC | 4.8 | 330.887 | no | 130.2 | 4.20643 | 0.201909 | no | Murs | Noyau | Mur de base | Cloison de séparation 98/48 à ossature métal avec laine minérale
1858858 | 0 RDC | Plâtre BA25 | Niveau: 0 RDC | 2.5 | 331.887 | yes | 132.7 | 4.29848 | 0.107462 | yes | Murs | Finition | Mur de base | Cloison de séparation 98/48 à ossature métal avec laine minérale
1858859 | 0 RDC | Plâtre BA25 | Niveau: 0 RDC | 2.5 | 330.887 | yes | 125.4 | 4.05497 | 0.101374 | yes | Murs | Finition | Mur de base | Cloison de séparation 98/48 à ossature métal avec laine minérale
1858841 | 0 RDC | Isolant Laine minérale 45mm | Niveau: 0 RDC | 4.8 | 315.839 | no | 195.1 | 6.1564 | 0.295507 | no | Murs | Noyau | Mur de base | Cloison de séparation 98/48 à ossature métal avec laine minérale
1858842 | 0 RDC | Plâtre BA25 | Niveau: 0 RDC | 2.5 | 315.263 | no | 197.4 | 6.22033 | 0.155508 | no | Murs | Finition | Mur de base | Cloison de séparation 98/48 à ossature métal avec laine minérale
1858843 | 0 RDC | Plâtre BA25 | Niveau: 0 RDC | 2.5 | 316.139 | no | 190.1 | 6.00695 | 0.150174 | no | Murs | Finition | Mur de base | Cloison de séparation 98/48 à ossature métal avec laine minérale
2189592 | 0 RDC | Béton dallage | Niveau: 0 RDC | 12 |  | no |  | 32.7069 | 3.92483 | no | Terre-plein | Noyau | Terre-plein | Dallage sur terre plein finition carrelage 45x45
2189593 | 0 RDC | Isolant rigide Polystyrène Expansé | Niveau: 0 RDC | 8 |  | no |  | 32.7069 | 2.61656 | no | Terre-plein | Noyau | Terre-plein | Dallage sur terre plein finition carrelage 45x45
2189594 | 0 RDC | Sable | Niveau: 0 RDC | 4 |  | no |  | 32.7069 | 1.30828 | no | Terre-plein | Noyau | Terre-plein | Dallage sur terre plein finition carrelage 45x45
2189595 | 0 RDC | Gravier | Niveau: 0 RDC | 25 |  | no |  | 32.7069 | 8.17673 | no | Terre-plein | Noyau | Terre-plein | Dallage sur terre plein finition carrelage 45x45
2748537 | 0 RDC | Carrelage 45x45cm | Niveau: 0 RDC | 1 |  | yes |  | 29.837 | 0.29837 | yes | Terre-plein | Finition | Terre-plein | Dallage sur terre plein finition carrelage 45x45
2608638 | 0 RDC | Isolant Laine minérale haute densité 40mm | Niveau: 0 RDC | 4 |  | no |  | 30.8811 | 1.23524 | yes | Plafonds | Noyau | Plafond composé | Plafond Rayonnant C Dalle 60x60cm
2608639 | 0 RDC | Plâcoplatre plafond | Niveau: 0 RDC | 0.95 |  | no |  | 30.8811 | 0.29337 | yes | Plafonds | Finition | Plafond composé | Plafond Rayonnant C Dalle 60x60cm
1858906 | 0 RDC | vide | Niveau: 0 RDC | 0.3 | 301 | yes | 113.236 | 3.4084 | 0.0102252 | yes | Murs | Finition | Mur de base | Cloison de distribution 72/48 à ossature métal avec laine minérale
1858907 | 0 RDC | vide | Niveau: 0 RDC | 0.3 | 301 | yes | 116.539 | 3.50781 | 0.0105234 | yes | Murs | Finition | Mur de base | Cloison de distribution 72/48 à ossature métal avec laine minérale
1858908 | 0 RDC | Plâtre BA18 | Niveau: 0 RDC | 1.8 | 301 | yes | 110.136 | 3.31507 | 0.0596712 | yes | Murs | Finition | Mur de base | Cloison de distribution 72/48 à ossature métal avec laine minérale
1858909 | 0 RDC | Isolant Laine minérale haute densité 40mm | Niveau: 0 RDC | 3 | 301 | yes | 113.538 | 3.41747 | 0.102524 | yes | Murs | Noyau | Mur de base | Cloison de distribution 72/48 à ossature métal avec laine minérale
1858910 | 0 RDC | Plâtre BA18 | Niveau: 0 RDC | 1.8 | 301 | yes | 115.54 | 3.47773 | 0.0625991 | yes | Murs | Finition | Mur de base | Cloison de distribution 72/48 à ossature métal avec laine minérale
2174406 | 0 RDC | Enduit | Niveau: 0 RDC | 2.1 | 351.733 | yes | 505.564 | 12.0814 | 0.253709 | yes | Murs | Finition | Mur de base | Mur exterieur doublé
2174407 | 0 RDC | Béton banché mur | Niveau: 0 RDC | 20 | 352.539 | yes | 521.806 | 12.0347 | 2.40695 | yes | Murs | Noyau | Mur de base | Mur exterieur doublé
2683629 | 0 RDC | Plâtre BA13 | Niveau: 0 RDC | 1.3 | 281.3 | yes | 489.835 | 9.33792 | 0.121393 | yes | Murs | Finition | Mur de base | Mur exterieur doublé
2683699 | 0 RDC | Isolant Laine minérale 120mm | Niveau: 0 RDC | 12 | 281.3 | yes | 506.683 | 9.69617 | 1.16354 | yes | Murs | Noyau | Mur de base | Mur exterieur doublé
1856201 | 0 RDC | Enduit | Niveau: 0 RDC | 2.1 | 294.185 | no | 3175.87 | 93.3362 | 1.96006 | no | Murs | Finition | Mur de base | Mur exterieur doublé
1856202 | 0 RDC | Béton banché mur | Niveau: 0 RDC | 20 | 296.585 | no | 3176.66 | 93.7141 | 18.7428 | yes | Murs | Noyau | Mur de base | Mur exterieur doublé
1856203 | 0 RDC | Plâtre BA13 | Niveau: 0 RDC | 1.3 | 298.95 | yes | 533.288 | 15.9274 | 0.207056 | yes | Murs | Finition | Mur de base | Mur exterieur doublé
1856205 | 0 RDC | Isolant Laine minérale 120mm | Niveau: 0 RDC | 12 | 298.794 | yes | 553.014 | 16.3921 | 1.96706 | yes | Murs | Noyau | Mur de base | Mur exterieur doublé
1856206 | 0 RDC | Isolant Laine minérale 120mm | Niveau: 0 RDC | 12 | 299.023 | yes | 2568.46 | 76.4589 | 9.17507 | yes | Murs | Noyau | Mur de base | Mur exterieur doublé
1858752 | 0 RDC | Plâtre BA13 | Niveau: 0 RDC | 1.3 | 298.11 | no | 175.965 | 5.15811 | 0.0670555 | no | Murs | Finition | Mur de base | Mur exterieur doublé
1858807 | 0 RDC | Plâtre BA13 | Niveau: 0 RDC | 1.3 | 298.004 | no | 585.286 | 17.4248 | 0.226523 | yes | Murs | Finition | Mur de base | Mur exterieur doublé
2597011 | 0 RDC | Plâtre BA13 | Niveau: 0 RDC | 1.3 | 299.143 | yes | 182 | 5.44219 | 0.0707485 | yes | Murs | Finition | Mur de base | Mur exterieur doublé
2628208 | 0 RDC | Plâtre BA13 | Niveau: 0 RDC | 1.3 | 299.075 | yes | 805.401 | 24.0724 | 0.312941 | yes | Murs | Finition | Mur de base | Mur exterieur doublé
2628209 | 0 RDC | Plâtre BA13 | Niveau: 0 RDC | 1.3 | 298.085 | no | 104.4 | 3.10519 | 0.0403674 | no | Murs | Finition | Mur de base | Mur exterieur doublé
2628210 | 0 RDC | Plâtre BA13 | Niveau: 0 RDC | 1.3 | 298.094 | no | 103.601 | 3.0874 | 0.0401362 | no | Murs | Finition | Mur de base | Mur exterieur doublé
2628211 | 0 RDC | Plâtre BA13 | Niveau: 0 RDC | 1.3 | 298.127 | no | 185.718 | 5.5327 | 0.0719251 | no | Murs | Finition | Mur de base | Mur exterieur doublé
2724605 | 0 RDC | Plâtre BA13 | Niveau: 0 RDC | 1.3 | 299.178 | yes | 381.302 | 11.404 | 0.148252 | yes | Murs | Finition | Mur de base | Mur exterieur doublé
2724606 | 0 RDC | Plâtre BA13 | Niveau: 0 RDC | 1.3 | 298.144 | no | 7.30001 | 0.092995 | 0.00120894 | no | Murs | Finition | Mur de base | Mur exterieur doublé
1858767 | 0 RDC | Isolant Laine minérale 45mm | Niveau: 0 RDC | 4.8 | 330.028 | yes | 521.184 | 16.7851 | 0.805686 | yes | Murs | Noyau | Mur de base | Cloison de séparation 98/48 à ossature métal avec laine minérale
1858769 | 0 RDC | Plâtre BA25 | Niveau: 0 RDC | 2.5 | 329.298 | yes | 514.084 | 16.5312 | 0.413281 | yes | Murs | Finition | Mur de base | Cloison de séparation 98/48 à ossature métal avec laine minérale
2682450 | 0 RDC | Plâtre BA25 | Niveau: 0 RDC | 2.5 | 329.147 | no | 174.084 | 5.68269 | 0.142067 | no | Murs | Finition | Mur de base | Cloison de séparation 98/48 à ossature métal avec laine minérale
2682451 | 0 RDC | Plâtre BA25 | Niveau: 0 RDC | 2.5 | 324.72 | yes | 330.2 | 10.5566 | 0.263914 | yes | Murs | Finition | Mur de base | Cloison de séparation 98/48 à ossature métal avec laine minérale
1853358 | 0 RDC | Enduit | Niveau: 0 RDC | 2.1 | 390.385 | no | 829.483 | 28.3637 | 0.595637 | no | Murs | Finition | Mur de base | Mur exterieur doublé
1853359 | 0 RDC | Béton banché mur | Niveau: 0 RDC | 20 | 391.087 | no | 814.87 | 27.8477 | 5.56953 | no | Murs | Noyau | Mur de base | Mur exterieur doublé
1853360 | 0 RDC | Plâtre BA13 | Niveau: 0 RDC | 1.3 | 314.126 | yes | 130.874 | 4.00632 | 0.0520821 | yes | Murs | Finition | Mur de base | Mur exterieur doublé
1853361 | 0 RDC | Isolant Laine minérale 120mm | Niveau: 0 RDC | 12 | 390.303 | yes | 787.141 | 27.0236 | 3.24284 | yes | Murs | Noyau | Mur de base | Mur exterieur doublé
1858766 | 0 RDC | Plâtre BA13 | Niveau: 0 RDC | 1.3 | 388.952 | yes | 638.514 | 22.4589 | 0.291966 | yes | Murs | Finition | Mur de base | Mur exterieur doublé
2167449 | 0 RDC | Plâtre BA13 | Niveau: 0 RDC | 1.3 | 352.263 | yes | 169.8 | 5.80843 | 0.0755096 | yes | Murs | Finition | Mur de base | Int. Voile BA 20 doublé
2598555 | 0 RDC | Isolant Laine minérale 45mm | Niveau: 0 RDC | 4.5 | 352.263 | yes | 169.803 | 5.80849 | 0.261382 | yes | Murs | Finition | Mur de base | Int. Voile BA 20 doublé
2678185 | 0 RDC | Plâtre BA13 | Niveau: 0 RDC | 1.3 | 280.3 | no | 7.25016 | 0.178613 | 0.00232196 | no | Murs | Finition | Mur de base | Int. Voile BA 20 doublé
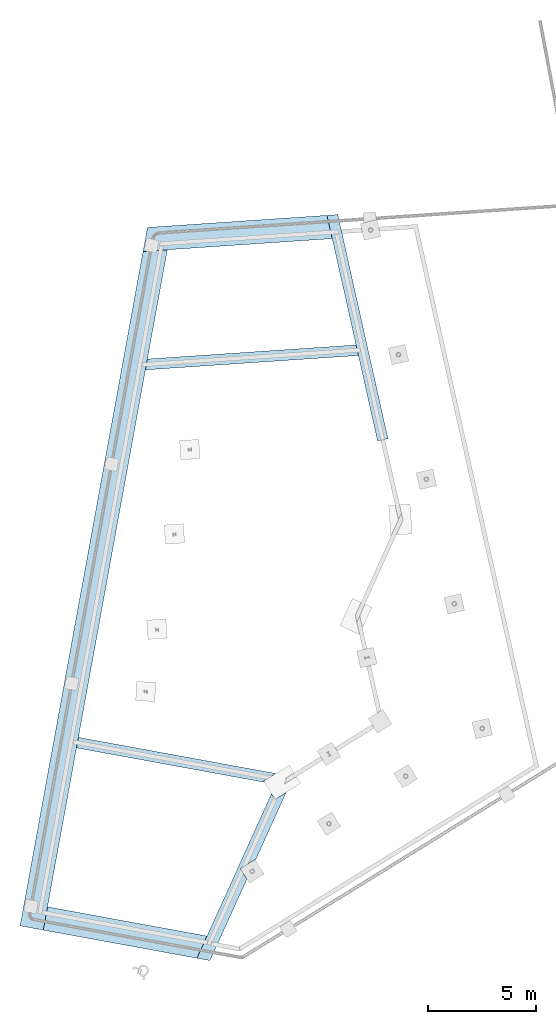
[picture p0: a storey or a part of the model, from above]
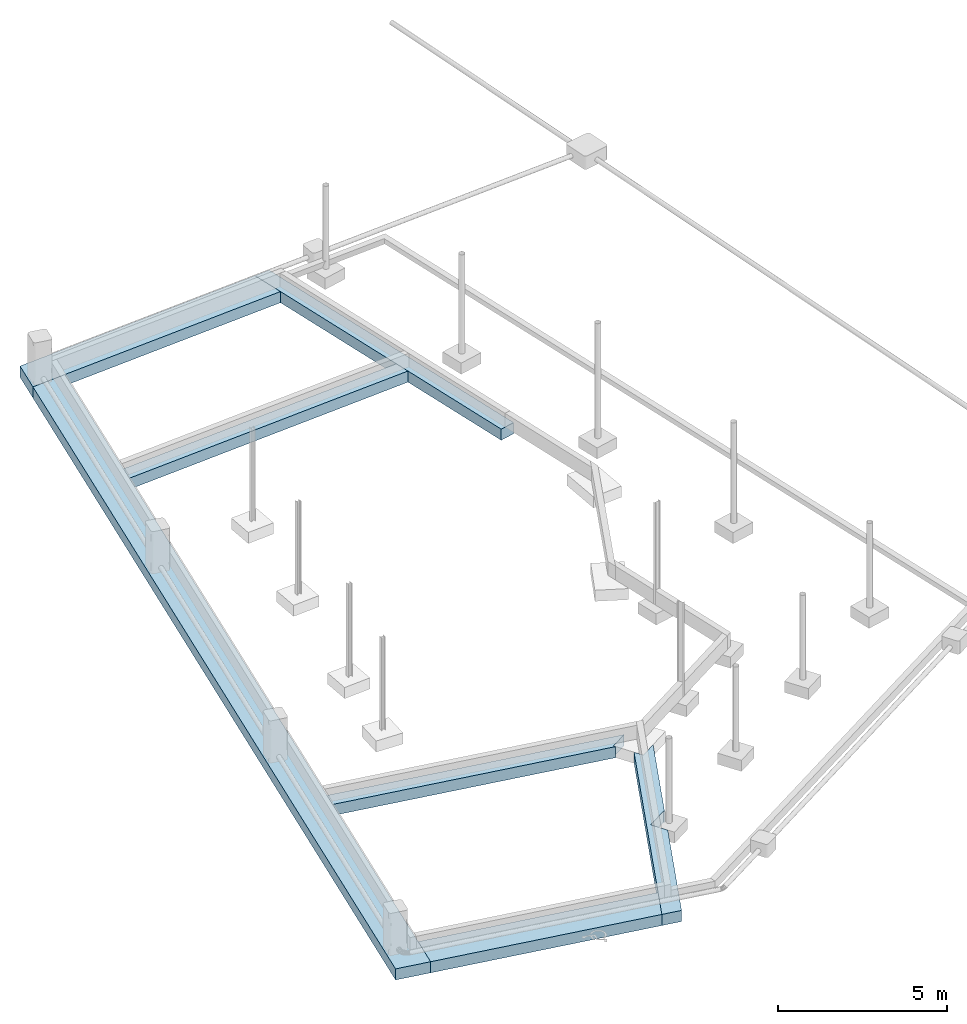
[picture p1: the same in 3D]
Properties of the parts of a building model (IFC2X3), part 2 of 5

# IfcBuildingElementPart (222)
Name (Elément:...) | In | Material = Matériau | Niveau de base | Epaisseur (cm) | Hauteur (cm) | La forme a été modifiée | Longueur (cm) | Surface (m2) | Volume (m3) | Afficher des poignées de la forme | Catégorie d'origine | Construction | Famille d'origine | Type d'origine
2678186 | 0 RDC | Plâtre BA13 | Niveau: 0 RDC | 1.3 | 281.3 | yes | 678.044 | 16.9808 | 0.22075 | yes | Murs | Finition | Mur de base | Int. Voile BA 20 doublé
2686381 | 0 RDC | Isolant Laine minérale 45mm | Niveau: 0 RDC | 4.5 | 412.491 | no | 505.433 | 17.2177 | 0.774798 | no | Murs | Finition | Mur de base | Int. Voile BA 20 doublé
2686748 | 0 RDC | Plâtre BA13 | Niveau: 0 RDC | 1.3 | 413.195 | yes | 502.971 | 17.173 | 0.223249 | yes | Murs | Finition | Mur de base | Int. Voile BA 20 doublé
2726262 | 0 RDC | Béton banché mur | Niveau: 0 RDC | 20 | 415.573 | yes | 697.387 | 23.8709 | 4.77419 | yes | Murs | Noyau | Mur de base | Int. Voile BA 20 doublé
2826754 | 0 RDC | Plâtre BA13 | Niveau: 1 Toiture auvent | 1.3 | 132.828 | no | 678.044 | 6.24572 | 0.0811943 | no | Murs | Finition | Mur de base | Int. Voile BA 20 doublé
2182281 | 0 RDC | Enduit | Niveau: 0 RDC | 2.1 | 308.786 | yes | 549.818 | 10.7971 | 0.226738 | yes | Murs | Finition | Mur de base | Mur exterieur doublé
2726695 | 0 RDC | Plâtre BA13 | Niveau: 0 RDC | 1.3 | 281.3 | yes | 519.789 | 8.3394 | 0.108412 | yes | Murs | Finition | Mur de base | Mur exterieur doublé
2727262 | 0 RDC | Isolant Laine minérale 120mm | Niveau: 0 RDC | 12 | 281.3 | yes | 530.613 | 8.55852 | 1.02702 | yes | Murs | Noyau | Mur de base | Mur exterieur doublé
2728156 | 0 RDC | Béton banché mur | Niveau: 0 RDC | 20 | 15.7858 | no | 35.2894 | 0.0189223 | 0.00378446 | no | Murs | Noyau | Mur de base | Mur exterieur doublé
2728158 | 0 RDC | Béton banché mur | Niveau: 0 RDC | 20 | 15.7858 | no | 26.9432 | 0.0155247 | 0.00310495 | no | Murs | Noyau | Mur de base | Mur exterieur doublé
2728880 | 0 RDC | Béton banché mur | Niveau: 0 RDC | 20 | 306.786 | no | 551.432 | 10.2522 | 2.05045 | yes | Murs | Noyau | Mur de base | Mur exterieur doublé
2728881 | 0 RDC | Béton banché mur | Niveau: 0 RDC | 20 | 280.212 | no | 12.8775 | 0.0447014 | 0.00894028 | no | Murs | Noyau | Mur de base | Mur exterieur doublé
1854748 | 0 RDC | Plâtre BA13 | Niveau: 0 RDC | 1.3 | 412.25 | no | 253.336 | 10.0659 | 0.130857 | yes | Murs | Finition | Mur de base | Int. Voile BA 20 doublé
1854749 | 0 RDC | Isolant Laine minérale 45mm | Niveau: 0 RDC | 4.5 | 412.616 | no | 255.345 | 10.1408 | 0.456334 | no | Murs | Finition | Mur de base | Int. Voile BA 20 doublé
1854750 | 0 RDC | Béton banché mur | Niveau: 0 RDC | 20 | 415.977 | yes | 1019.83 | 34.1982 | 6.83964 | yes | Murs | Noyau | Mur de base | Int. Voile BA 20 doublé
1858764 | 0 RDC | Plâtre BA13 | Niveau: 0 RDC | 1.3 | 328.336 | no | 261.244 | 6.18029 | 0.0803438 | no | Murs | Finition | Mur de base | Int. Voile BA 20 doublé
1858765 | 0 RDC | Isolant Laine minérale 45mm | Niveau: 0 RDC | 4.5 | 328.469 | no | 263.724 | 6.24433 | 0.280995 | no | Murs | Finition | Mur de base | Int. Voile BA 20 doublé
1858793 | 0 RDC | Plâtre BA13 | Niveau: 0 RDC | 1.3 | 383.225 | yes | 458.5 | 16.3474 | 0.212516 | yes | Murs | Finition | Mur de base | Int. Voile BA 20 doublé
1858794 | 0 RDC | Isolant Laine minérale 45mm | Niveau: 0 RDC | 4.5 | 383.358 | yes | 458.5 | 16.3513 | 0.73581 | yes | Murs | Finition | Mur de base | Int. Voile BA 20 doublé
2586333 | 0 RDC | Plâtre BA13 | Niveau: 0 RDC | 1.3 | 330.887 | no | 283.481 | 6.90786 | 0.0898021 | no | Murs | Finition | Mur de base | Int. Voile BA 20 doublé
2586334 | 0 RDC | Plâtre BA13 | Niveau: 0 RDC | 1.3 | 414.474 | yes | 705.08 | 26.3215 | 0.34218 | yes | Murs | Finition | Mur de base | Int. Voile BA 20 doublé
2190372 | 0 RDC | Isolant rigide Polystyrène Expansé | Niveau: 0 RDC | 8 |  | no |  | 219.041 | 17.5233 | no | Terre-plein | Noyau | Terre-plein | Dallage sur terre plein finition quartz
2190373 | 0 RDC | Sable | Niveau: 0 RDC | 4 |  | no |  | 219.041 | 8.76165 | no | Terre-plein | Noyau | Terre-plein | Dallage sur terre plein finition quartz
2190374 | 0 RDC | Gravier | Niveau: 0 RDC | 25 |  | no |  | 219.041 | 54.7603 | no | Terre-plein | Noyau | Terre-plein | Dallage sur terre plein finition quartz
2771341 | 0 RDC | Chape finiton quartz | Niveau: 0 RDC | 1 |  | yes |  | 213.358 | 2.13358 | yes | Terre-plein | Finition | Terre-plein | Dallage sur terre plein finition quartz
2252275 | 0 RDC | vide | Niveau: 0 RDC | 0.3 | 301 | yes | 254.637 | 5.57958 | 0.0167387 | yes | Murs | Finition | Mur de base | Cloison de distribution 72/48 à ossature métal avec laine minérale
2252276 | 0 RDC | vide | Niveau: 0 RDC | 0.3 | 301 | yes | 254.637 | 5.57958 | 0.0167387 | yes | Murs | Finition | Mur de base | Cloison de distribution 72/48 à ossature métal avec laine minérale
2252277 | 0 RDC | Plâtre BA18 | Niveau: 0 RDC | 1.8 | 301 | yes | 254.637 | 5.57958 | 0.100432 | yes | Murs | Finition | Mur de base | Cloison de distribution 72/48 à ossature métal avec laine minérale
2252278 | 0 RDC | Isolant Laine minérale haute densité 40mm | Niveau: 0 RDC | 3 | 301 | yes | 254.637 | 5.57958 | 0.167387 | yes | Murs | Noyau | Mur de base | Cloison de distribution 72/48 à ossature métal avec laine minérale
2252279 | 0 RDC | Plâtre BA18 | Niveau: 0 RDC | 1.8 | 301 | yes | 254.637 | 5.57958 | 0.100432 | yes | Murs | Finition | Mur de base | Cloison de distribution 72/48 à ossature métal avec laine minérale
2173726 | 0 RDC | Enduit | Niveau: 0 RDC | 2.1 | 457.447 | yes | 2165.84 | 41.9344 | 0.880623 | yes | Murs | Finition | Mur de base | Mur exterieur doublé
2177107 | 0 RDC | Isolant Laine minérale 120mm | Niveau: 0 RDC | 12 | 453.659 | yes | 1330.82 | 18.2172 | 2.18607 | yes | Murs | Noyau | Mur de base | Mur exterieur doublé
2724583 | 0 RDC | Plâtre BA13 | Niveau: 0 RDC | 1.3 | 390.734 | yes | 11.5916 | 0.446314 | 0.00580208 | yes | Murs | Finition | Mur de base | Mur exterieur doublé
2724584 | 0 RDC | Plâtre BA13 | Niveau: 0 RDC | 1.3 | 401.815 | yes | 379.805 | 6.90738 | 0.0897959 | yes | Murs | Finition | Mur de base | Mur exterieur doublé
2724585 | 0 RDC | Plâtre BA13 | Niveau: 0 RDC | 1.3 | 452.145 | yes | 1311.58 | 17.9899 | 0.233869 | yes | Murs | Finition | Mur de base | Mur exterieur doublé
2724588 | 0 RDC | Plâtre BA13 | Niveau: 0 RDC | 1.3 | 169.789 | no | 1.90019 | 0.0322435 | 0.000419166 | no | Murs | Finition | Mur de base | Mur exterieur doublé
2724589 | 0 RDC | Plâtre BA13 | Niveau: 0 RDC | 1.3 | 401.108 | no | 10.4241 | 0.260935 | 0.00339215 | no | Murs | Finition | Mur de base | Mur exterieur doublé
2725675 | 0 RDC | Isolant Laine minérale 120mm | Niveau: 0 RDC | 12 | 414.975 | yes | 810.516 | 22.2692 | 2.67231 | yes | Murs | Noyau | Mur de base | Mur exterieur doublé
2725816 | 0 RDC | Plâtre BA13 | Niveau: 0 RDC | 1.3 | 414.356 | yes | 387.77 | 13.7389 | 0.178605 | yes | Murs | Finition | Mur de base | Mur exterieur doublé
2727905 | 0 RDC | Béton banché mur | Niveau: 0 RDC | 20 | 419.047 | yes | 853.735 | 24.1126 | 4.82252 | yes | Murs | Noyau | Mur de base | Mur exterieur doublé
2729507 | 0 RDC | Béton banché mur | Niveau: 0 RDC | 20 | 456.182 | yes | 1345.13 | 18.5025 | 3.7005 | yes | Murs | Noyau | Mur de base | Mur exterieur doublé
2174209 | 0 RDC | Enduit | Niveau: 0 RDC | 2.1 | 456.283 | yes | 1387.21 | 42.2361 | 0.886958 | yes | Murs | Finition | Mur de base | Mur exterieur doublé
2174210 | 0 RDC | Béton banché mur | Niveau: 0 RDC | 20 | 454.623 | yes | 1363.37 | 40.5006 | 8.10013 | yes | Murs | Noyau | Mur de base | Mur exterieur doublé
2174211 | 0 RDC | Plâtre BA13 | Niveau: 0 RDC | 1.3 | 452.044 | yes | 801.252 | 27.3796 | 0.355934 | yes | Murs | Finition | Mur de base | Mur exterieur doublé
2174213 | 0 RDC | Isolant Laine minérale 120mm | Niveau: 0 RDC | 12 | 451.724 | yes | 801.487 | 27.0478 | 3.24573 | yes | Murs | Noyau | Mur de base | Mur exterieur doublé
2174214 | 0 RDC | Isolant Laine minérale 120mm | Niveau: 0 RDC | 12 | 415.028 | yes | 529.189 | 12.0591 | 1.44709 | yes | Murs | Noyau | Mur de base | Mur exterieur doublé
2175371 | 0 RDC | Plâtre BA13 | Niveau: 0 RDC | 1.3 | 412.403 | no | 177.656 | 5.19713 | 0.0675627 | no | Murs | Finition | Mur de base | Mur exterieur doublé
2175372 | 0 RDC | Plâtre BA13 | Niveau: 0 RDC | 1.3 | 404.617 | yes | 334.3 | 6.18199 | 0.0803659 | yes | Murs | Finition | Mur de base | Mur exterieur doublé
2190527 | 0 RDC | Béton dallage | Niveau: 0 RDC | 12 |  | no |  | 35.5618 | 4.26742 | no | Terre-plein | Noyau | Terre-plein | Dallage sur terre plein finition Carrelage 30x30
2190528 | 0 RDC | Isolant rigide Polystyrène Expansé | Niveau: 0 RDC | 8 |  | no |  | 35.5618 | 2.84494 | no | Terre-plein | Noyau | Terre-plein | Dallage sur terre plein finition Carrelage 30x30
2190529 | 0 RDC | Sable | Niveau: 0 RDC | 4 |  | no |  | 35.5618 | 1.42247 | no | Terre-plein | Noyau | Terre-plein | Dallage sur terre plein finition Carrelage 30x30
2190530 | 0 RDC | Gravier | Niveau: 0 RDC | 25 |  | no |  | 35.5618 | 8.89045 | no | Terre-plein | Noyau | Terre-plein | Dallage sur terre plein finition Carrelage 30x30
2738408 | 0 RDC | Carrelage 30x30cm | Niveau: 0 RDC | 1 |  | yes |  | 33.0331 | 0.330331 | yes | Terre-plein | Finition | Terre-plein | Dallage sur terre plein finition Carrelage 30x30
2185831 | 0 RDC | Béton dallage | Niveau: 0 RDC | 12 |  | no |  | 33.5907 | 4.03088 | no | Terre-plein | Noyau | Terre-plein | Dallage sur terre plein finition carrelage 45x45
2185832 | 0 RDC | Isolant rigide Polystyrène Expansé | Niveau: 0 RDC | 8 |  | no |  | 33.5907 | 2.68726 | no | Terre-plein | Noyau | Terre-plein | Dallage sur terre plein finition carrelage 45x45
2185833 | 0 RDC | Sable | Niveau: 0 RDC | 4 |  | no |  | 33.5907 | 1.34363 | no | Terre-plein | Noyau | Terre-plein | Dallage sur terre plein finition carrelage 45x45
2185834 | 0 RDC | Gravier | Niveau: 0 RDC | 25 |  | no |  | 33.5907 | 8.39768 | no | Terre-plein | Noyau | Terre-plein | Dallage sur terre plein finition carrelage 45x45
2724175 | 0 RDC | Carrelage 45x45cm | Niveau: 0 RDC | 1 |  | yes |  | 30.8184 | 0.308184 | yes | Terre-plein | Finition | Terre-plein | Dallage sur terre plein finition carrelage 45x45
2608680 | 0 RDC | Isolant Laine minérale haute densité 40mm | Niveau: 0 RDC | 4 |  | no |  | 21.9544 | 0.878176 | no | Plafonds | Noyau | Plafond composé | Plafond Rayonnant C Dalle 60x60cm
2608681 | 0 RDC | Plâcoplatre plafond | Niveau: 0 RDC | 0.95 |  | no |  | 21.9544 | 0.208567 | no | Plafonds | Finition | Plafond composé | Plafond Rayonnant C Dalle 60x60cm
2608672 | 0 RDC | Plâcoplatre plafond | Niveau: 0 RDC | 1.5 |  | no |  | 9.94213 | 0.149132 | no | Plafonds | Noyau | Plafond composé | Plafond Placo non démontable
2608673 | 0 RDC | Plâcoplatre plafond | Niveau: 0 RDC | 1.5 |  | no |  | 9.94213 | 0.149132 | no | Plafonds | Noyau | Plafond composé | Plafond Placo non démontable
2608676 | 0 RDC | Plâcoplatre plafond | Niveau: 0 RDC | 1.5 |  | no |  | 16.8532 | 0.252797 | no | Plafonds | Noyau | Plafond composé | Plafond Placo non démontable
2608677 | 0 RDC | Plâcoplatre plafond | Niveau: 0 RDC | 1.5 |  | no |  | 16.8532 | 0.252797 | no | Plafonds | Noyau | Plafond composé | Plafond Placo non démontable
2634310 | 0 RDC | Enduit | Niveau: 0 RDC | 2.1 | 392.667 | yes | 820.885 | 22.5158 | 0.472832 | yes | Murs | Finition | Mur de base | Mur exterieur doublé
2634311 | 0 RDC | Béton banché mur | Niveau: 0 RDC | 20 | 390.532 | yes | 786.583 | 21.2427 | 4.24854 | yes | Murs | Noyau | Mur de base | Mur exterieur doublé
2634312 | 0 RDC | Plâtre BA13 | Niveau: 0 RDC | 1.3 | 390.285 | yes | 759.228 | 20.5026 | 0.266533 | yes | Murs | Finition | Mur de base | Mur exterieur doublé
2634313 | 0 RDC | Isolant Laine minérale 120mm | Niveau: 0 RDC | 12 | 390.407 | yes | 762.424 | 20.5546 | 2.46655 | yes | Murs | Noyau | Mur de base | Mur exterieur doublé
2608664 | 0 RDC | Plâcoplatre plafond | Niveau: 0 RDC | 1.5 |  | no |  | 2.2888 | 0.0343321 | no | Plafonds | Noyau | Plafond composé | Plafond Placo non démontable
2608665 | 0 RDC | Plâcoplatre plafond | Niveau: 0 RDC | 1.5 |  | no |  | 2.2888 | 0.0343321 | no | Plafonds | Noyau | Plafond composé | Plafond Placo non démontable
2742824 | 0 RDC | Béton dallage | Niveau: 0 RDC | 12 |  | no |  | 4.55179 | 0.546214 | no | Terre-plein | Noyau | Terre-plein | Dallage sur terre plein finition Carrelage 30x30
2742825 | 0 RDC | Isolant rigide Polystyrène Expansé | Niveau: 0 RDC | 8 |  | no |  | 4.55179 | 0.364143 | no | Terre-plein | Noyau | Terre-plein | Dallage sur terre plein finition Carrelage 30x30
2742826 | 0 RDC | Sable | Niveau: 0 RDC | 4 |  | no |  | 4.55179 | 0.182071 | no | Terre-plein | Noyau | Terre-plein | Dallage sur terre plein finition Carrelage 30x30
2742827 | 0 RDC | Gravier | Niveau: 0 RDC | 25 |  | no |  | 4.55179 | 1.13795 | no | Terre-plein | Noyau | Terre-plein | Dallage sur terre plein finition Carrelage 30x30
2744430 | 0 RDC | Carrelage 30x30cm | Niveau: 0 RDC | 1 |  | no |  | 4.17612 | 0.0417612 | no | Terre-plein | Finition | Terre-plein | Dallage sur terre plein finition Carrelage 30x30
2597922 | 0 RDC | Béton banché mur | Niveau: 0 RDC | 20 | 75.8869 | yes | 286.457 | 1.68146 | 0.336292 | yes | Murs | Noyau | Mur de base | Int. Voile BA 20
2717988 | 0 RDC | Chape finiton quartz | Niveau: 0 RDC | 1 |  | yes |  | 9.94571 | 0.0994571 | yes | Terre-plein | Finition | Terre-plein | Dallage sur terre plein finition quartz
2717989 | 0 RDC | Béton dallage | Niveau: 0 RDC | 12 |  | no |  | 11.0317 | 1.32381 | no | Terre-plein | Noyau | Terre-plein | Dallage sur terre plein finition quartz
2717990 | 0 RDC | Isolant rigide Polystyrène Expansé | Niveau: 0 RDC | 8 |  | no |  | 11.0317 | 0.882537 | no | Terre-plein | Noyau | Terre-plein | Dallage sur terre plein finition quartz
2717991 | 0 RDC | Sable | Niveau: 0 RDC | 4 |  | no |  | 11.0317 | 0.441269 | no | Terre-plein | Noyau | Terre-plein | Dallage sur terre plein finition quartz
2717992 | 0 RDC | Gravier | Niveau: 0 RDC | 25 |  | no |  | 11.0317 | 2.75793 | no | Terre-plein | Noyau | Terre-plein | Dallage sur terre plein finition quartz
2717983 | 0 RDC | Béton dallage | Niveau: 0 RDC | 12 |  | no |  | 10.9192 | 1.31031 | no | Terre-plein | Noyau | Terre-plein | Dallage sur terre plein finition Carrelage 30x30
2717984 | 0 RDC | Isolant rigide Polystyrène Expansé | Niveau: 0 RDC | 8 |  | no |  | 10.9192 | 0.873539 | no | Terre-plein | Noyau | Terre-plein | Dallage sur terre plein finition Carrelage 30x30
2717985 | 0 RDC | Sable | Niveau: 0 RDC | 4 |  | no |  | 10.9192 | 0.436769 | no | Terre-plein | Noyau | Terre-plein | Dallage sur terre plein finition Carrelage 30x30
2717986 | 0 RDC | Gravier | Niveau: 0 RDC | 25 |  | no |  | 10.9192 | 2.72981 | no | Terre-plein | Noyau | Terre-plein | Dallage sur terre plein finition Carrelage 30x30
2741243 | 0 RDC | Carrelage 30x30cm | Niveau: 0 RDC | 1 |  | no |  | 10.3885 | 0.103885 | yes | Terre-plein | Finition | Terre-plein | Dallage sur terre plein finition Carrelage 30x30

# IfcBuildingElementProxy: 4.8m x 2.4m - 90°, Place de parking - Handicapé:4.8m x 2.4m - 90°:1593048
In: -1 Soubassement
Type - Material: Peinture de sol - Blanc
Type - Autre - Catégorie: Parking; Nom de la famille: Place de parking - Handicapé
Type - Contraintes - pl2: 240 cm; pw2: 120 cm
Type - Cotes - Angle: 90 deg; Largeur du parking: 240 cm; Longueur du parking: 480 cm; pl: 480 cm; pw: 240 cm
Type - Données d'identification - Nom du type: 4.8m x 2.4m - 90°
Type - Pset_BuildingElementProxyCommon - Reference: Place de parking - Handicapé:4.8m x 2.4m - 90°
Type - Pset_QuantityTakeOff - Reference: Place de parking - Handicapé:4.8m x 2.4m - 90°
Pset_BuildingElementProxyCommon - sets with these values: 2
Autre - Famille: Place de parking - Handicapé: 4.8m x 2.4m - 90°; Famille et type: Place de parking - Handicapé: 4.8m x 2.4m - 90°; ID du type: Place de parking - Handicapé: 4.8m x 2.4m - 90°; Type: Place de parking - Handicapé: 4.8m x 2.4m - 90°
Contraintes - Se déplace avec les éléments voisins: no; Niveau: Niveau: -1 Soubassement; Décalage: 1 cm; Hôte: Sous-région
Cotes - Surface: 0.146568 m2; Volume: 0.000227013 m3
Phase de construction - Phase de création: Projet

# IfcBuildingElementProxy: 56x52 cm (2)
In: 0 RDC
Type - Material: Métal - Chrome, Peinture - Ivoire brillant
Type - Autre - Catégorie: Equipement spécialisé; Nom de la famille: Congélateur - Vertical
Type - Cotes - Dégagement arrière: 5 cm; Hauteur: 84 cm; Largeur: 56 cm; Poignée: 4 cm; Profondeur: 52 cm
Type - Données d'identification - Nom du type: 56x52 cm
Type - Matériaux et finitions - Matériau: Peinture - Ivoire brillant
Type - Pset_BuildingElementProxyCommon - Reference: Congélateur - Vertical:56x52 cm
Type - Pset_QuantityTakeOff - Reference: Congélateur - Vertical:56x52 cm
Pset_BuildingElementProxyCommon - sets with these values: 2
Autre - Famille: Congélateur - Vertical: 56x52 cm; Famille et type: Congélateur - Vertical: 56x52 cm; ID du type: Congélateur - Vertical: 56x52 cm; Type: Congélateur - Vertical: 56x52 cm
Contraintes - Décalage: 0 cm; Se déplace avec les éléments voisins: no; Niveau: Niveau: 0 RDC; Hôte: Niveau : 0 RDC
Cotes - Surface: 1.68307 m2; Volume: 0.240455 m3
Phase de construction - Phase de création: Projet
Name (Congélateur - Vertical:56x52 cm:...)
559292
660356

# IfcBuildingElementProxy: 600 mm x 600 mm x 850 mm, Lave vaisselle - 01:600 mm x 600 mm x 850 mm:574366
In: 0 RDC
Type - Material: Peinture - Ivoire
Type - Autre - Catégorie: Equipement spécialisé; Nom de la famille: Lave vaisselle - 01
Type - Cotes - Hauteur: 85 cm; Profondeur: 60 cm
Type - Données d'identification - Nom du type: 600 mm x 600 mm x 850 mm
Type - Matériaux et finitions - Finition: Peinture - Ivoire
Type - Pset_BuildingElementProxyCommon - Reference: Lave vaisselle - 01:600 mm x 600 mm x 850 mm
Type - Pset_QuantityTakeOff - Reference: Lave vaisselle - 01:600 mm x 600 mm x 850 mm
Pset_BuildingElementProxyCommon - sets with these values: 2
Autre - Famille: Lave vaisselle - 01: 600 mm x 600 mm x 850 mm; Famille et type: Lave vaisselle - 01: 600 mm x 600 mm x 850 mm; ID du type: Lave vaisselle - 01: 600 mm x 600 mm x 850 mm; Type: Lave vaisselle - 01: 600 mm x 600 mm x 850 mm
Contraintes - Décalage: 0 cm; Se déplace avec les éléments voisins: no; Niveau: Niveau: 0 RDC; Hôte: Niveau : 0 RDC
Cotes - Surface: 1.75199 m2; Volume: 0.303685 m3
Phase de construction - Phase de création: Projet

# IfcBuildingElementProxy: 610mm x 610mm, Cuisinière:610mm x 610mm:1902207
In: 0 RDC
Type - Material: Métal - Chrome, Verre, Peinture - Ivoire
Type - Autre - Catégorie: Equipement spécialisé; Nom de la famille: Cuisinière
Type - Cotes - Largeur: 61 cm; Profondeur: 61 cm
Type - Données d'identification - Nom du type: 610mm x 610mm
Type - Matériaux et finitions - Brûleur: Métal - Chrome; Plage: Peinture - Ivoire
Type - Pset_BuildingElementProxyCommon - Reference: Cuisinière:610mm x 610mm
Type - Pset_QuantityTakeOff - Reference: Cuisinière:610mm x 610mm
Pset_BuildingElementProxyCommon - sets with these values: 2
Autre - Famille: Cuisinière: 610mm x 610mm; Famille et type: Cuisinière: 610mm x 610mm; ID du type: Cuisinière: 610mm x 610mm; Type: Cuisinière: 610mm x 610mm
Contraintes - Niveau: Niveau: 0 RDC; Se déplace avec les éléments voisins: no; Hôte: Niveau : 0 RDC
Cotes - Surface: 3.10096 m2; Volume: 0.14282 m3
Phase de construction - Phase de création: Projet

# IfcBuildingElementProxy: 750 mm x 1800 mm, Congélateur - Vertical:750 mm x 1800 mm:559449
In: 0 RDC
Type - Material: Métal - Chrome, Peinture - Ivoire brillant
Type - Autre - Catégorie: Equipement spécialisé; Nom de la famille: Congélateur - Vertical
Type - Cotes - Dégagement arrière: 5 cm; Hauteur: 204 cm; Largeur: 70 cm; Poignée: 4 cm; Profondeur: 86 cm
Type - Données d'identification - Nom du type: 750 mm x 1800 mm
Type - Matériaux et finitions - Matériau: Peinture - Ivoire brillant
Type - Pset_BuildingElementProxyCommon - Reference: Congélateur - Vertical:750 mm x 1800 mm
Type - Pset_QuantityTakeOff - Reference: Congélateur - Vertical:750 mm x 1800 mm
Pset_BuildingElementProxyCommon - sets with these values: 2
Autre - Famille: Congélateur - Vertical: 750 mm x 1800 mm; Famille et type: Congélateur - Vertical: 750 mm x 1800 mm; ID du type: Congélateur - Vertical: 750 mm x 1800 mm; Type: Congélateur - Vertical: 750 mm x 1800 mm
Contraintes - Niveau: Niveau: 0 RDC; Décalage: 0 cm; Se déplace avec les éléments voisins: no; Hôte: Niveau : 0 RDC
Cotes - Surface: 5.21994 m2; Volume: 1.21753 m3
Phase de construction - Phase de création: Projet

# IfcBuildingElementProxy: Bord de dalle:Be1 (2)
In: -1 Soubassement
Pset_BuildingElementProxyCommon - Reference: Bord de dalle:Be1; sets with these values: 2
Autre - Catégorie: Bords de dalles; Famille: Bord de dalle: Be1; Famille et type: Bord de dalle: Be1; ID du type: Bord de dalle: Be1; Type: Bord de dalle: Be1
Contraintes - Décalage horizontal du profil: 0 cm; Décalage vertical du profil: 0 cm
Phase de construction - Phase de création: Projet
Profil - Angle: 0 deg
Structure - Enrobage d'armature: Paramètres de l'enrobage d'armature: Enrobage d'armature 1
Autre(Type) - Catégorie: Bords de dalles; Nom de la famille: Bord de dalle
Construction(Type) - Profil: Beche bord de dalle terrasse: Beche bord de dalle terrasse
Données d'identification(Type) - Nom du type: Be1
Matériaux et finitions(Type) - Matériau: Maçonnerie - Voile BA
Name (Bord de dalle:Be1:...) | Longueur (cm) | Volume (m3)
2120513 | 4579.79 | 1.92326
2120712 | 138.166 | 0.0571462

# IfcBuildingElementProxy: Bord de toiture:Habillage de rive H = 25cm (9)
Pset_BuildingElementProxyCommon - Reference: Bord de toiture:Habillage de rive H = 25cm; sets with these values: 2
Autre - Catégorie: Bords de toitures; Famille: Bord de toiture: Habillage de rive H = 25cm; Famille et type: Bord de toiture: Habillage de rive H = 25cm; ID du type: Bord de toiture: Habillage de rive H = 25cm; Type: Bord de toiture: Habillage de rive H = 25cm
Contraintes - Décalage horizontal du profil: 0 cm
Phase de construction - Phase de création: Projet
Profil - Angle: 0 deg
Autre(Type) - Catégorie: Bords de toitures; Nom de la famille: Bord de toiture
Construction(Type) - Profil: Planche de rive: 2x25cm
Données d'identification(Type) - Nom du type: Habillage de rive H = 25cm
Matériaux et finitions(Type) - Matériau: Chêne clair
Name (Bord de toiture:Habillage de rive H = 25cm:...) | In | Décalage vertical du profil (cm) | Longueur (cm)
1502694 | 2 Toiture batiment | 0 | 1411.66
1502710 | 2 Toiture batiment | 32.3231 | 2196.2
1502809 | 1 Toiture auvent | 0 | 1217.35
1502815 | 1 Toiture auvent | 0 | 1275.39
1502825 | 1 Toiture auvent | 0 | 161.45
1502826 | 1 Toiture auvent | 0 | 1414.13
1945203 | 2 Toiture batiment | 0 | 3214.12
1945211 | 2 Toiture batiment | 0 | 875.783
2159197 | 2 Toiture batiment | 0 | 869.277

# IfcBuildingElementProxy: Dauphin (4)
In: 0 RDC
Type - Material: Fonte, forgé
Type - Autre - Catégorie: Modèles génériques; Nom de la famille: Dauphin
Type - Cotes - Hauteur du dauphin: 100 cm; J1: 5 cm; J2: 5.5 cm; Ø EXT: 10 cm; Ø EXT JOINTURE: 11 cm; Ø INT: 9.6 cm; Ø INT JOINTURE: 10.6 cm
Type - Données d'identification - Nom du type: Dauphin
Type - Pset_BuildingElementProxyCommon - Reference: Dauphin:Dauphin
Type - Pset_QuantityTakeOff - Reference: Dauphin:Dauphin
Pset_BuildingElementProxyCommon - sets with these values: 2
Autre - Famille: Dauphin: Dauphin; Famille et type: Dauphin: Dauphin; ID du type: Dauphin: Dauphin; Type: Dauphin: Dauphin
Contraintes - Niveau: Niveau: 0 RDC; Se déplace avec les éléments voisins: no; Décalage: 100 cm; Hôte: Niveau : 0 RDC
Cotes - Surface: 0.348383 m2; Volume: 0.000843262 m3
Matériaux et finitions - Matériau: Fonte, forgé
Phase de construction - Phase de création: Projet
Name (Dauphin:Dauphin:...)
1946321
1946512
1956690
1957020

# IfcBuildingElementProxy: Texte 3D:Texte 3D 1, Texte 3D:Texte 3D 1:545769
In: 0 RDC
Pset_BuildingElementProxyCommon - Reference: Texte 3D:Texte 3D 1; sets with these values: 2
Autre - Catégorie: Modèles génériques; Famille: Texte 3D: Texte 3D 1; Famille et type: Texte 3D: Texte 3D 1; ID du type: Texte 3D: Texte 3D 1; Type: Texte 3D: Texte 3D 1
Contraintes - Plan de construction: <non associé>
Cotes - Profondeur: 10 cm
Données d'identification - Sous-catégorie: Modèles génériques
Graphismes - Alignement horizontal: Gauche; Texte: V E Y R E A U
Matériaux et finitions - Matériau: Peinture - Noir
Phase de construction - Phase de création: Projet
Autre(Type) - Catégorie: Modèles génériques; Nom de la famille: Texte 3D
Données d'identification(Type) - Nom du type: Texte 3D 1
Texte(Type) - Gras: no; Italique: no; Police de texte: Cooper Black; Taille du texte: 30 cm

# IfcColumn: HE140A (4)
In: -1 Soubassement
Type - PredefinedType: COLUMN
Type - Autre - Catégorie: Poteaux porteurs; Nom de la famille: H-Poutrelles-Poteau
Type - Cotes - bf: 14 cm; d: 13.3 cm; k: 2.05 cm; kr: 1.2 cm; tf: 0.85 cm; tw: 0.55 cm
Type - Données d'identification - Nom du type: HE140A
Type - Structure - A: 0.003142 m2; Forme de coupe: 0; W: 0.242224
Type - Pset_ColumnCommon - IsExternal: no; LoadBearing: yes; Reference: H-Poutrelles-Poteau:HE140A
Type - Pset_QuantityTakeOff - Reference: H-Poutrelles-Poteau:HE140A
Type - Pset_ReinforcementBarPitchOfColumn - Reference: H-Poutrelles-Poteau:HE140A
Material: Acier structurel - S235
BaseQuantities - GrossVolume: 0.0100801 m3
Pset_ColumnCommon - Slope: 0 deg
Pset_QuantityTakeOff - sets with these values: 2
Autre - Famille: H-Poutrelles-Poteau: HE140A; Famille et type: H-Poutrelles-Poteau: HE140A; ID du type: H-Poutrelles-Poteau: HE140A; Type: H-Poutrelles-Poteau: HE140A
Contraintes - Décalage inférieur: 0 cm; Niveau: Niveau: -1 Soubassement; Se déplace avec les quadrillages: yes; Style de poteau: Vertical; Niveau de base: Niveau: -1 Soubassement; Décalage supérieur: 285 cm; Niveau supérieur: Niveau: 0 RDC
Cotes - Longueur: 335 cm; Volume: 0.0100801 m3
Matériaux et finitions - Matériau structurel: Acier structurel - S235
Phase de construction - Phase de création: Projet
Structure - Activer le modèle analytique: yes; Revêtement: -
Name (H-Poutrelles-Poteau:HE140A:...)
650962
651404
651437
651486

# IfcColumn: IPE200 (2)
In: -1 Soubassement
Type - PredefinedType: COLUMN
Type - Analyse structurelle - Moment d'inertie de torsion: 0; Rayon d'inertie sectoriel: 0; Aire sectionnelle: 0.00285 m2; Module d'élasticité - axe faible: 0.0000285 m3; Module d'élasticité - axe fort: 0.000194 m3; Module plastique - axe faible: 0.0000739 m3; Module plastique - axe fort: 0.000367 m3; Moment d'inertie - axe faible: 0.000164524; Moment d'inertie - axe fort: 0.00225119; Périmètre: 0.234086 m2; Poids nominal: 301.063
Type - Autre - Catégorie: Poteaux porteurs; Nom de la famille: Poteau IPE
Type - Données d'identification - Nom de code: EURONORM 19-57; DIN 1025; NF A 45-205; Nom du type: IPE200
Type - Géométrie de coupe structurelle - Centre de gravité horizontal: 5 cm; Centre de gravité vertical: 10 cm; Congé de l'âme: 1.2 cm; Epaisseur de l'aile: 0.85 cm; Epaisseur de l'âme: 0.56 cm; Hauteur: 20 cm; Largeur: 10 cm
Type - Structure - Forme de coupe: 6
Type - Pset_ColumnCommon - IsExternal: no; LoadBearing: yes; Reference: Poteau IPE:IPE200
Type - Pset_QuantityTakeOff - Reference: Poteau IPE:IPE200
Type - Pset_ReinforcementBarPitchOfColumn - Reference: Poteau IPE:IPE200
Material: Acier structurel - S235
Pset_ColumnCommon - Slope: 0 deg
Pset_QuantityTakeOff - sets with these values: 2
Autre - Famille: Poteau IPE: IPE200; Famille et type: Poteau IPE: IPE200; ID du type: Poteau IPE: IPE200; Type: Poteau IPE: IPE200
Contraintes - Décalage inférieur: 0 cm; Niveau: Niveau: -1 Soubassement; Niveau de base: Niveau: -1 Soubassement; Se déplace avec les quadrillages: yes; Style de poteau: Vertical; Niveau supérieur: Niveau: 0 RDC
Matériaux et finitions - Matériau structurel: Acier structurel - S235
Phase de construction - Phase de création: Projet
Structure - Activer le modèle analytique: yes
Name (Poteau IPE:IPE200:...) | GrossVolume (m3) = Volume (m3) | Décalage supérieur (cm) | Longueur (cm)
2080676 | 0.0092207 | 288.399 | 338.399
2081203 | 0.00998851 | 316.578 | 366.578

# IfcColumn: Poteau rond 193.7x4 mm (8)
In: -1 Soubassement
Type - PredefinedType: COLUMN
Type - Analyse structurelle - Aire sectionnelle: 0.00238 m2; Module d'élasticité - axe fort: 0.000111 m3; Module de torsion: 0.000222 m3; Module plastique - axe fort: 0.000144 m3; Moment d'inertie - axe fort: 0.0012432; Moment d'inertie de torsion: 0.00248639; Périmètre: 0.185623 m2; Poids nominal: 183.384
Type - Autre - Catégorie: Poteaux porteurs; Nom de la famille: Poteau RO (EN 10219-2)
Type - Cotes - Epaisseur de conception du mur: 0.4 cm
Type - Données d'identification - Identifiant du nom de la coupe: RO193.7x4; Nom de code: EN 10219-2; DIN EN 10219-2; NF EN 10219-2; Nom du type: Poteau rond 193.7x4 mm
Type - Géométrie de coupe structurelle - Centre de gravité horizontal: 9.685 cm; Centre de gravité vertical: 9.685 cm; Diamètre: 19.37 cm; Epaisseur nominale du mur: 0.4 cm
Type - Structure - Forme de coupe: 15
Type - Pset_ColumnCommon - IsExternal: no; Reference: Poteau RO (EN 10219-2):Poteau rond 193.7x4 mm; LoadBearing: yes
Type - Pset_QuantityTakeOff - Reference: Poteau RO (EN 10219-2):Poteau rond 193.7x4 mm
Type - Pset_ReinforcementBarPitchOfColumn - Reference: Poteau RO (EN 10219-2):Poteau rond 193.7x4 mm
Material: Acier structurel - S235
Pset_ColumnCommon - Slope: 0 deg
Pset_QuantityTakeOff - sets with these values: 2
Autre - Famille: Poteau RO (EN 10219-2): Poteau rond 193.7x4 mm; Famille et type: Poteau RO (EN 10219-2): Poteau rond 193.7x4 mm; ID du type: Poteau RO (EN 10219-2): Poteau rond 193.7x4 mm; Type: Poteau RO (EN 10219-2): Poteau rond 193.7x4 mm
Contraintes - Décalage inférieur: 0 cm; Niveau: Niveau: -1 Soubassement; Niveau de base: Niveau: -1 Soubassement; Niveau supérieur: Niveau: -1 Soubassement; Se déplace avec les quadrillages: yes; Style de poteau: Vertical
Matériaux et finitions - Matériau structurel: Acier structurel - S235
Phase de construction - Phase de création: Projet
Structure - Activer le modèle analytique: yes; Revêtement: -
Name (Poteau RO (EN 10219-2):Poteau rond 193.7x4 mm:...) | GrossVolume (m3) = Volume (m3) | Décalage supérieur (cm) = Longueur (cm) | Décalage de l'attachement en haut (cm) | Justification de l'attachement en haut | Partie supérieure attachée
517289 | 0.00977153 | 414.553
517291 | 0.00714932 | 305.125 | 0 | Intersection maximale | yes
517293 | 0.00709877 | 304.804 | 0 | Intersection maximale | yes
517295 | 0.00717132 | 304.848 | 0 | Intersection maximale | yes
517502 | 0.00834934 | 357.472 | 0 | Intersection maximale | yes
517504 | 0.00696719 | 299.117 | 0 | Intersection maximale | yes
561053 | 0.0084592 | 362.076 | 0 | Intersection maximale | yes
582613 | 0.00717417 | 304.893 | 0 | Intersection maximale | yes

# IfcCovering: Plafond composé:Plafond Dalle 60 x 60 "Hygiène & Acoustique", Plafond composé:Plafond Dalle 60 x 60 "Hygiène & Acoustique":665799
In: 0 RDC
Type - PredefinedType: CEILING
Type - Autre - Catégorie: Plafonds; Nom de la famille: Plafond composé
Type - Construction - Epaisseur: 2 cm
Type - Données d'identification - Nom du type: Plafond Dalle 60 x 60 "Hygiène & Acoustique"
Type - Graphismes - Motif vue détail faible: <Remplissage de solide>; Couleur vue détail faible: 12632256
Type - Propriétés analytiques - Rugosité: 1; Coefficient d'absorbance: 0.1; Coefficient de transfert de chaleur (U): 1.88889; Masse thermique: 2556; Résistance thermique (R): 0.529412
Type - Pset_CoveringCommon - Reference: Plafond composé:Plafond Dalle 60 x 60 "Hygiène & Acoustique"; TotalThickness: 2 cm
Type - Pset_QuantityTakeOff - Reference: Plafond composé:Plafond Dalle 60 x 60 "Hygiène & Acoustique"
Pset_CoveringCommon - Finish: Plastique blanc;
BaseQuantities - GrossCeilingArea: 16.9877 m2
Autre - Famille: Plafond composé: Plafond Dalle 60 x 60 "Hygiène & Acoustique"; Famille et type: Plafond composé: Plafond Dalle 60 x 60 "Hygiène & Acoustique"; ID du type: Plafond composé: Plafond Dalle 60 x 60 "Hygiène & Acoustique"; Type: Plafond composé: Plafond Dalle 60 x 60 "Hygiène & Acoustique"
Contraintes - Limite de pièce: yes; Niveau: Niveau: 0 RDC; Décalage par rapport au niveau: 250 cm
Cotes - Périmètre: 1667.63 cm; Surface: 16.9877 m2; Volume: 0.339753 m3
Données d'identification - Commentaires: Pièce humide
Phase de construction - Phase de création: Projet

# IfcCovering: Plafond composé:Plafond Dalle 60x60 + Iso 200mm, Plafond composé:Plafond Dalle 60x60 + Iso 200mm:1299896
In: 0 RDC
Type - PredefinedType: CEILING
Type - Autre - Catégorie: Plafonds; Nom de la famille: Plafond composé
Type - Construction - Epaisseur: 22 cm
Type - Données d'identification - Nom du type: Plafond Dalle 60x60 + Iso 200mm
Type - Graphismes - Motif vue détail faible: <Remplissage de solide>; Couleur vue détail faible: 12632256
Type - Propriétés analytiques - Rugosité: 1; Coefficient d'absorbance: 0.1; Coefficient de transfert de chaleur (U): 0.17; Masse thermique: 28400; Résistance thermique (R): 5.88235
Type - Pset_CoveringCommon - Reference: Plafond composé:Plafond Dalle 60x60 + Iso 200mm; TotalThickness: 22 cm
Type - Pset_QuantityTakeOff - Reference: Plafond composé:Plafond Dalle 60x60 + Iso 200mm
Material: Isolant Laine minérale 200mm 20 cm, Peinture blanche 2 cm
Pset_CoveringCommon - Finish: Peinture blanche;
BaseQuantities - GrossCeilingArea: 12.2837 m2
Autre - Famille: Plafond composé: Plafond Dalle 60x60 + Iso 200mm; Famille et type: Plafond composé: Plafond Dalle 60x60 + Iso 200mm; ID du type: Plafond composé: Plafond Dalle 60x60 + Iso 200mm; Type: Plafond composé: Plafond Dalle 60x60 + Iso 200mm
Contraintes - Limite de pièce: yes; Niveau: Niveau: 0 RDC; Décalage par rapport au niveau: 258.25 cm
Cotes - Périmètre: 1837.93 cm; Surface: 12.2837 m2; Volume: 2.70242 m3
Données d'identification - Commentaires: Pièce courante
Phase de construction - Phase de création: Projet

# IfcCovering: Plafond composé:Plafond Placo non démontable (5)
In: 0 RDC
Type - PredefinedType: CEILING
Type - Autre - Catégorie: Plafonds; Nom de la famille: Plafond composé
Type - Construction - Epaisseur: 3 cm
Type - Données d'identification - Nom du type: Plafond Placo non démontable
Type - Graphismes - Motif vue détail faible: <Remplissage de solide>; Couleur vue détail faible: 12632256
Type - Propriétés analytiques - Rugosité: 1; Coefficient d'absorbance: 0.1; Coefficient de transfert de chaleur (U): 8.33333; Masse thermique: 27720; Résistance thermique (R): 0.12
Type - Pset_CoveringCommon - Reference: Plafond composé:Plafond Placo non démontable; TotalThickness: 3 cm
Type - Pset_QuantityTakeOff - Reference: Plafond composé:Plafond Placo non démontable
Pset_CoveringCommon - Finish: Plâcoplatre plafond;
Autre - Famille: Plafond composé: Plafond Placo non démontable; Famille et type: Plafond composé: Plafond Placo non démontable; ID du type: Plafond composé: Plafond Placo non démontable; Type: Plafond composé: Plafond Placo non démontable
Contraintes - Limite de pièce: yes; Niveau: Niveau: 0 RDC
Phase de construction - Phase de création: Projet
Name (Plafond composé:Plafond Placo non démontable:...) | GrossCeilingArea (m2) = Surface (m2) | Décalage par rapport au niveau (cm) | Périmètre (cm) | Volume (m3) | Commentaires
665075 | 19.1008 | 250 | 2142.85 | 0.573023 | CF1H
676425 | 7.89474 | 250 | 1255.17 | 0.236842 | CF1H
1987002 | 9.94213 | 250 | 1431.15 | 0.298264 | CF1H
1987536 | 16.8532 | 217.5 | 1783.6 | 0.505595 | CF1H | Cotes - Inclinaison: 0.12
2579840 | 2.2888 | 250 | 621 | 0.0686641

# IfcCovering: Plafond composé:Plafond Rayonnant C Dalle 60x60cm (2)
In: 0 RDC
Type - PredefinedType: CEILING
Type - Autre - Catégorie: Plafonds; Nom de la famille: Plafond composé
Type - Construction - Epaisseur: 4.95 cm
Type - Données d'identification - Nom du type: Plafond Rayonnant C Dalle 60x60cm
Type - Graphismes - Motif vue détail faible: <Remplissage de solide>; Couleur vue détail faible: 12632256
Type - Propriétés analytiques - Rugosité: 1; Coefficient d'absorbance: 0.1; Coefficient de transfert de chaleur (U): 0.752829; Masse thermique: 14458; Résistance thermique (R): 1.32832
Type - Pset_CoveringCommon - Reference: Plafond composé:Plafond Rayonnant C Dalle 60x60cm; TotalThickness: 4.95 cm
Type - Pset_QuantityTakeOff - Reference: Plafond composé:Plafond Rayonnant C Dalle 60x60cm
Pset_CoveringCommon - Finish: Plâcoplatre plafond;
Autre - Famille: Plafond composé: Plafond Rayonnant C Dalle 60x60cm; Famille et type: Plafond composé: Plafond Rayonnant C Dalle 60x60cm; ID du type: Plafond composé: Plafond Rayonnant C Dalle 60x60cm; Type: Plafond composé: Plafond Rayonnant C Dalle 60x60cm
Contraintes - Limite de pièce: yes; Niveau: Niveau: 0 RDC; Décalage par rapport au niveau: 250 cm
Cotes - Inclinaison: 0.12
Données d'identification - Commentaires: Pièce courante
Phase de construction - Phase de création: Projet
Name (Plafond composé:Plafond Rayonnant C Dalle 60x60cm:...) | GrossCeilingArea (m2) = Surface (m2) | Périmètre (cm) | Volume (m3)
1302164 | 30.8811 | 2385.37 | 1.52861
1986977 | 21.9544 | 1984.59 | 1.08674

# IfcCovering: Plafond composé:Plafond Rayonnant H Dalle 60 x 60 (3)
In: 0 RDC
Type - PredefinedType: CEILING
Type - Autre - Catégorie: Plafonds; Nom de la famille: Plafond composé
Type - Construction - Epaisseur: 4.65 cm
Type - Données d'identification - Nom du type: Plafond Rayonnant H Dalle 60 x 60
Type - Graphismes - Motif vue détail faible: <Remplissage de solide>; Couleur vue détail faible: 12632256
Type - Propriétés analytiques - Rugosité: 1; Coefficient d'absorbance: 0.1; Coefficient de transfert de chaleur (U): 0.759692; Masse thermique: 11686; Résistance thermique (R): 1.31632
Type - Pset_CoveringCommon - Reference: Plafond composé:Plafond Rayonnant H Dalle 60 x 60; TotalThickness: 4.65 cm
Type - Pset_QuantityTakeOff - Reference: Plafond composé:Plafond Rayonnant H Dalle 60 x 60
Pset_CoveringCommon - Finish: Plâcoplatre plafond;
Autre - Famille: Plafond composé: Plafond Rayonnant H Dalle 60 x 60; Famille et type: Plafond composé: Plafond Rayonnant H Dalle 60 x 60; ID du type: Plafond composé: Plafond Rayonnant H Dalle 60 x 60; Type: Plafond composé: Plafond Rayonnant H Dalle 60 x 60
Contraintes - Limite de pièce: yes; Niveau: Niveau: 0 RDC; Décalage par rapport au niveau: 250 cm
Phase de construction - Phase de création: Projet
Name (Plafond composé:Plafond Rayonnant H Dalle 60 x 60:...) | GrossCeilingArea (m2) = Surface (m2) | Périmètre (cm) | Volume (m3) | Commentaires
665087 | 24.1028 | 4796.34 | 1.12078 | Pièce humide
666149 | 1.7632 | 540.4 | 0.0819888 | Pièce courante
676441 | 4.23135 | 835.363 | 0.196758 | Pièce humide

# IfcDistributionPort (61)
Description: Flow; FlowDirection: SOURCEANDSINK
Name | Group
2 x InPort_1963935 | EP 5
2 x OutPort_2002122 | EP 5
Port_1963935 | EP 5
OutPort_2027032 | EP 5
2 x InPort_1964383 | EP 5
2 x OutPort_2000957 | EP 5
Port_1964383 | EP 5
2 x Port_1964598 | EP 5
InPort_1964598 | EP 5
2 x Port_1981700 | EP 3
InPort_1981700 | EP 3
OutPort_2047433 | EP 3
2 x InPort_1981944 | EP 2
OutPort_2039489 | EP 2
Port_1981944 | EP 2
OutPort_2000548 | EP 2
2 x Port_1982875 | EP 6
InPort_1982875 | EP 6
OutPort_2038890 | EP 6
2 x Port_1983183 | EP 5
InPort_1983183 | EP 5
2 x OutPort_2035817 | EP 5
InPort_2000548 | EP 2
OutPort_2040593 | EP 2
2 x InPort_2026979 | EP 5
OutPort_2034771 | EP 5
2 x OutPort_2035645 | EP 5
InPort_2027032 | EP 5
OutPort_2035501 | EP 5
InPort_2034771 | EP 5
InPort_2035501 | EP 5
2 x InPort_2037868 | EP 1
OutPort_2040104 | EP 1
Port_2037868 | EP 1
OutPort_2038155 | EP 1
Port_2038155 | EP 1
InPort_2038890 | EP 6
2 x OutPort_2039167 | EP 6
2 x InPort_2039043 | EP 6
Port_2039043 | EP 6
OutPort_2039150 | EP 6
Port_2039150 | EP 6
Port_2039489 | EP 2
Port_2040104 | EP 1
Port_2040593 | EP 2
Port_2047433 | EP 3

# IfcDoor: 0.90m x 2.04m, Coulissante - Encastrée:0.90m x 2.04m:574166
In: 0 RDC
Type - ParameterTakesPrecedence: no; Sizeable: no; Material: Porte - Poignée, Porte - Panneau, Porte - Cadre
Type - Autre - Catégorie: Portes; Nom de la famille: Coulissante - Encastrée
Type - Construction - Fonction: Intérieur; Fermeture du mur: Aucun
Type - Cotes - Epaisseur: 4 cm; Hauteur: 204 cm; Hauteur de la poignée: 90 cm; Largeur: 90 cm; Largeur du cadre: 1.5 cm; Retour: 1 cm
Type - Données d'identification - Marque de type: 43; Nom du type: 0.90m x 2.04m
Type - Matériaux et finitions - Dormants: Porte - Cadre; Panneau: Porte - Panneau; Poignée: Porte - Poignée
Type - Propriétés analytiques - Coefficient d'apport thermique solaire: 0; Coefficient de transfert de chaleur (U): 3.7021; Construction analytique: Métal; Résistance thermique (R): 0.270117; Transmission de la lumière visible: 0
OverallHeight: 206.5 cm; OverallWidth: 184 cm
Pset_DoorCommon - IsExternal: no; Reference: Coulissante - Encastrée:0.90m x 2.04m; ThermalTransmittance: 3.7021 kg/K/s3
Pset_QuantityTakeOff - Reference: Coulissante - Encastrée:0.90m x 2.04m
BaseQuantities - Height: 204 cm; Width: 90 cm; Area: 1.836 m2
Autre - ID hôte: Mur de base: Cloison de séparation 98/48 à ossature métal avec laine minérale; Famille: Coulissante - Encastrée: 0.90m x 2.04m; Famille et type: Coulissante - Encastrée: 0.90m x 2.04m; Hauteur sous linteau: 203 cm; ID du type: Coulissante - Encastrée: 0.90m x 2.04m; Type: Coulissante - Encastrée: 0.90m x 2.04m
Contraintes - Niveau: Niveau: 0 RDC; Hauteur de l'appui: -1 cm
Cotes - Surface: 2.5614 m2; Volume: 0.0817011 m3
Données d'identification - Identifiant: 138
Phase de construction - Phase de création: Projet

# IfcDoor: Menuiserie 2, Ensemble Alu vitré:Menuiserie 2:1876803
In: 0 RDC
Type - ParameterTakesPrecedence: no; Sizeable: no; Material: Verre, Aluminium
Type - Autre(Type) - Catégorie: Portes; Altezza maniglia: 73.3333 cm; Larghezza anta: 94.95 cm; Nom de la famille: Ensemble Alu vitré; Posizione simbolo: 47.475 cm; Proiezione telaio est.: 2.5 cm; Proiezione telaio int.: 2.5 cm
Type - Construction(Type) - Fonction: Extérieur; Fermeture du mur: Par hôte
Type - Cotes(Type) - Epaisseur: 30 cm; Hauteur: 220 cm; Largeur: 370 cm; Largeur brute: 30 cm
Type - Données d'identification(Type) - Marque de type: 99; Nom du type: Menuiserie 2; Note d'identification: Paroi vitrée; Numéro OmniClass: 23.30.10.00; Titre OmniClass: Doors
Type - Données(Type) - Air Permeability: Class 4; Mechanical Resistance: Class 4; Operating Forces: Class 1; Resistance opening and closing: Class 2; Soundproofing: up to 42 dB; Thermal Transmittance: Uf W/m2K 2.6; Watertightness: Class 9A; Wind Resistance: Class B3
Type - Général(Type) - Edition number: 2; Nominal height: 0; Nominal width: 0; Weight Net (Kg): 0; Product group: Aluminium windows
Type - Matériaux et finitions(Type) - Material Frame: Aluminium; Material Glass: Verre; Material Handle: Aluminium; Material main: Alluminium; Material secondary: Glass
Type - Propriétés analytiques(Type) - Coefficient d'apport thermique solaire: 0; Transmission de la lumière visible: 0; Coefficient de transfert de chaleur (U): 1.55; Construction analytique: Cadre en métal, double/triple vitre, contre-porte vitrée; Résistance thermique (R): 0.645161
OverallHeight: 220.001 cm; OverallWidth: 370 cm
Pset_DoorCommon - IsExternal: yes; Reference: Ensemble Alu vitré:Menuiserie 2; ThermalTransmittance: 1.55 kg/K/s3
Pset_QuantityTakeOff - Reference: Ensemble Alu vitré:Menuiserie 2
BaseQuantities - Height: 220 cm; Width: 370 cm; Area: 8.14 m2
Autre - Catégorie: Portes; ID hôte: Mur de base: Mur exterieur doublé; Famille: Ensemble Alu vitré: Menuiserie 2; Famille et type: Ensemble Alu vitré: Menuiserie 2; ID du type: Ensemble Alu vitré: Menuiserie 2; Type: Ensemble Alu vitré: Menuiserie 2; Hauteur sous linteau: 220 cm
Contraintes - Niveau: Niveau: 0 RDC; Hauteur de l'appui: 0 cm
Cotes - Ext Wall Offset: 2 cm; Surface: 15.7068 m2; Volume: 0.38 m3
Données d'identification - Identifiant: 167
Phase de construction - Phase de création: Projet

# IfcDoor: Menuiserie 3 (3)
In: 0 RDC
Type - ParameterTakesPrecedence: no; Sizeable: no; Material: Black, Aluminium, Verre, Black_Rubber
Type - Analyse d'énergie(Type) - U-Value: 1.55
Type - Autre(Type) - Catégorie: Portes; Height Control: 220 cm; Nom de la famille: Porte Ext vitrée; Width Control: 93 cm
Type - Construction(Type) - Fonction: Extérieur; Fermeture du mur: Par hôte
Type - Cotes(Type) - Epaisseur: 6.5 cm; Gap: 0 cm; Hauteur: 220 cm; Hauteur brute: 220 cm; Largeur: 93 cm; Largeur brute: 93 cm; Leaf Height: 216 cm; Leaf Width: 85 cm
Type - Données d'identification(Type) - Marque de type: 92; Nom du type: Menuiserie 3; Numéro OmniClass: 23.30.10.00; Titre OmniClass: Doors
Type - Général(Type) - Nominal height: 0; Nominal width: 0; Weight Net (Kg): 0; Edition number: 1; Manufacturer country: Switzerland; Manufacturer name: Forster; Product family: Door
Type - Matériaux et finitions(Type) - Frame Material: Aluminium; Glass Material: Verre; Handle Material: Aluminium; Leaf Material: Aluminium; Material main: Aluminium; Material secondary: Verre
Type - Propriétés analytiques(Type) - Coefficient d'apport thermique solaire: 0; Transmission de la lumière visible: 0; Coefficient de transfert de chaleur (U): 1.55; Construction analytique: Cadre en métal, double/triple vitre, contre-porte vitrée; Résistance thermique (R): 0.645161
Type - Visibilité(Type) - Height Warning Max: no; Height Warning Min: no; Warning: no; Width Warning Max: no; Width Warning Min: no
OverallHeight: 220 cm; OverallWidth: 93 cm
Pset_DoorCommon - IsExternal: yes; ThermalTransmittance: 1.55 kg/K/s3; Reference: Porte Ext vitrée:Menuiserie 3
Pset_QuantityTakeOff - Reference: Porte Ext vitrée:Menuiserie 3
BaseQuantities - Height: 220 cm; Width: 93 cm; Area: 2.046 m2
Autre - Catégorie: Portes; ID hôte: Mur de base: Mur exterieur doublé; Famille: Porte Ext vitrée: Menuiserie 3; Famille et type: Porte Ext vitrée: Menuiserie 3; ID du type: Porte Ext vitrée: Menuiserie 3; Type: Porte Ext vitrée: Menuiserie 3; Handle Height Control: 105 cm; Hauteur sous linteau: 220 cm; Inset Control: 5 cm; Wall Width: 35.4 cm
Contraintes - Niveau: Niveau: 0 RDC; Hauteur de l'appui: 0 cm
Cotes - Handle Height: 105 cm; Inset: 5 cm; Surface: 3.43277 m2; Volume: 0.0724895 m3
Données - Fire Resistance Options Text: no
Phase de construction - Phase de création: Projet
Name (Porte Ext vitrée:Menuiserie 3:...) | Identifiant
1876838 | 160
1876934 | 162
2675854 | 243

# IfcDoor: Menuiserie 6, Ensemble Alu vitré:Menuiserie 6:1876860
In: 0 RDC
Type - ParameterTakesPrecedence: no; Sizeable: no; Material: Verre, Aluminium
Type - Autre(Type) - Catégorie: Portes; Altezza maniglia: 73.3333 cm; Larghezza anta: 102.45 cm; Nom de la famille: Ensemble Alu vitré; Posizione simbolo: 51.225 cm; Proiezione telaio est.: 2.5 cm; Proiezione telaio int.: 2.5 cm
Type - Construction(Type) - Fonction: Extérieur; Fermeture du mur: Par hôte
Type - Cotes(Type) - Epaisseur: 30 cm; Hauteur: 220 cm; Largeur: 400 cm; Largeur brute: 30 cm
Type - Données d'identification(Type) - Marque de type: 97; Nom du type: Menuiserie 6; Note d'identification: Paroi vitrée; Numéro OmniClass: 23.30.10.00; Titre OmniClass: Doors
Type - Données(Type) - Air Permeability: Class 4; Mechanical Resistance: Class 4; Operating Forces: Class 1; Resistance opening and closing: Class 2; Soundproofing: up to 42 dB; Watertightness: Class 9A; Wind Resistance: Class B3
Type - Général(Type) - Edition number: 2; Nominal height: 0; Nominal width: 0; Product family: Windows & Doors; Product group: Aluminium windows; Weight Net (Kg): 0
Type - Matériaux et finitions(Type) - Material Frame: Aluminium; Material Glass: Verre; Material Handle: Aluminium; Material main: Aluminium; Material secondary: Glass
Type - Propriétés analytiques(Type) - Coefficient d'apport thermique solaire: 0; Transmission de la lumière visible: 0; Coefficient de transfert de chaleur (U): 1.55; Construction analytique: Cadre en métal, double/triple vitre, contre-porte vitrée; Résistance thermique (R): 0.645161
OverallHeight: 220.001 cm; OverallWidth: 400 cm
Pset_DoorCommon - IsExternal: yes; ThermalTransmittance: 1.55 kg/K/s3; Reference: Ensemble Alu vitré:Menuiserie 6
Pset_QuantityTakeOff - Reference: Ensemble Alu vitré:Menuiserie 6
BaseQuantities - Height: 220 cm; Width: 400 cm; Area: 8.8 m2
Autre - Catégorie: Portes; Famille: Ensemble Alu vitré: Menuiserie 6; Famille et type: Ensemble Alu vitré: Menuiserie 6; ID du type: Ensemble Alu vitré: Menuiserie 6; ID hôte: Mur de base: Mur exterieur doublé; Type: Ensemble Alu vitré: Menuiserie 6; Hauteur sous linteau: 220 cm
Contraintes - Hauteur de l'appui: 0 cm; Niveau: Niveau: 0 RDC
Cotes - Ext Wall Offset: 2 cm; Surface: 16.6796 m2; Volume: 0.406165 m3
Données d'identification - Identifiant: 172
Phase de construction - Phase de création: Projet

# IfcDoor: Menuiserie 7, Ensemble Alu vitré:Menuiserie 7:1876902
In: 0 RDC
Type - ParameterTakesPrecedence: no; Sizeable: no; Material: Verre, Aluminium
Type - Autre(Type) - Catégorie: Portes; Altezza maniglia: 73.3333 cm; Larghezza anta: 84.95 cm; Nom de la famille: Ensemble Alu vitré; Posizione simbolo: 42.475 cm; Proiezione telaio est.: 2.5 cm; Proiezione telaio int.: 2.5 cm
Type - Construction(Type) - Fonction: Extérieur; Fermeture du mur: Par hôte
Type - Cotes(Type) - Epaisseur: 30 cm; Hauteur: 220 cm; Largeur: 330 cm; Largeur brute: 30 cm
Type - Données d'identification(Type) - Marque de type: 100; Nom du type: Menuiserie 7; Note d'identification: Paroi vitrée; Numéro OmniClass: 23.30.10.00; Titre OmniClass: Doors
Type - Données(Type) - Air Permeability: Class 4; Mechanical Resistance: Class 4; Operating Forces: Class 1; Resistance opening and closing: Class 2; Soundproofing: up to 42 dB; Thermal Transmittance: Uf W/m2K 2.6; Watertightness: Class 9A; Wind Resistance: Class B3
Type - Général(Type) - Edition number: 2; Nominal height: 0; Nominal width: 0; Weight Net (Kg): 0; Manufacturer name: Metra; Product family: Windows & Doors; Product group: Aluminium windows; Region Antarctica: TF
Type - Matériaux et finitions(Type) - Material Frame: Aluminium; Material Glass: Verre; Material Handle: Aluminium; Material main: Aluminium; Material secondary: Glass
Type - Propriétés analytiques(Type) - Coefficient d'apport thermique solaire: 0; Transmission de la lumière visible: 0; Coefficient de transfert de chaleur (U): 1.55; Construction analytique: Cadre en métal, double/triple vitre, contre-porte vitrée; Résistance thermique (R): 0.645161
OverallHeight: 220.001 cm; OverallWidth: 330 cm
Pset_DoorCommon - IsExternal: yes; ThermalTransmittance: 1.55 kg/K/s3; Reference: Ensemble Alu vitré:Menuiserie 7
Pset_QuantityTakeOff - Reference: Ensemble Alu vitré:Menuiserie 7
BaseQuantities - Height: 220 cm; Width: 330 cm; Area: 7.26 m2
Autre - Catégorie: Portes; ID hôte: Mur de base: Mur exterieur doublé; Famille: Ensemble Alu vitré: Menuiserie 7; Famille et type: Ensemble Alu vitré: Menuiserie 7; ID du type: Ensemble Alu vitré: Menuiserie 7; Type: Ensemble Alu vitré: Menuiserie 7; Hauteur sous linteau: 220 cm
Contraintes - Niveau: Niveau: 0 RDC; Hauteur de l'appui: 0 cm
Cotes - Ext Wall Offset: 2 cm; Surface: 14.4097 m2; Volume: 0.345114 m3
Données d'identification - Identifiant: 171
Phase de construction - Phase de création: Projet

# IfcDoor: Menuiserie 8, Ensemble Alu vitré:Menuiserie 8:1876962
In: 0 RDC
Type - ParameterTakesPrecedence: no; Sizeable: no; Material: Verre, Aluminium
Type - Autre - Catégorie: Portes; Altezza maniglia: 73.3333 cm; Larghezza anta: 82.45 cm; Nom de la famille: Ensemble Alu vitré; Posizione simbolo: 41.225 cm; Proiezione telaio est.: 2.5 cm; Proiezione telaio int.: 2.5 cm
Type - Construction - Fonction: Extérieur; Fermeture du mur: Par hôte
Type - Cotes - Epaisseur: 30 cm; Hauteur: 220 cm; Largeur: 320 cm; Largeur brute: 30 cm
Type - Données - Air Permeability: Class 4; Mechanical Resistance: Class 4; Operating Forces: Class 1; Resistance opening and closing: Class 2; Soundproofing: up to 42 dB; Thermal Transmittance: Uf W/m2K 2.6; Watertightness: Class 9A; Wind Resistance: Class B3
Type - Données d'identification - Marque de type: 98; Nom du type: Menuiserie 8; Note d'identification: Paroi vitrée; Numéro OmniClass: 23.30.10.00; Titre OmniClass: Doors
Type - Général - Edition number: 2; Nominal height: 0; Nominal width: 0; Weight Net (Kg): 0
Type - Matériaux et finitions - Material Frame: Aluminium; Material Glass: Verre; Material Handle: Aluminium; Material main: Aluminium; Material secondary: Glass
Type - Propriétés analytiques - Coefficient d'apport thermique solaire: 0; Transmission de la lumière visible: 0; Coefficient de transfert de chaleur (U): 1.55; Construction analytique: Cadre en métal, double/triple vitre, contre-porte vitrée; Résistance thermique (R): 0.645161
OverallHeight: 220.001 cm; OverallWidth: 320 cm
Pset_DoorCommon - IsExternal: yes; ThermalTransmittance: 1.55 kg/K/s3; Reference: Ensemble Alu vitré:Menuiserie 8
Pset_QuantityTakeOff - Reference: Ensemble Alu vitré:Menuiserie 8
BaseQuantities - Height: 220 cm; Width: 320 cm; Area: 7.04 m2
Autre - ID hôte: Mur de base: Mur exterieur doublé; Famille: Ensemble Alu vitré: Menuiserie 8; Famille et type: Ensemble Alu vitré: Menuiserie 8; Hauteur sous linteau: 220 cm; ID du type: Ensemble Alu vitré: Menuiserie 8; Type: Ensemble Alu vitré: Menuiserie 8
Contraintes - Niveau: Niveau: 0 RDC; Hauteur de l'appui: 0 cm
Cotes - Ext Wall Offset: 2 cm; Surface: 14.0854 m2; Volume: 0.336392 m3
Données d'identification - Identifiant: 170
Phase de construction - Phase de création: Projet

# IfcDoor: Ouverture Loge, Ouverture en rectangle:Ouverture Loge:1854679
In: 0 RDC
Type - ParameterTakesPrecedence: no; Sizeable: no; Material: Bois - Chêne
Type - Autre - Catégorie: Portes; Nom de la famille: Ouverture en rectangle
Type - Construction - Fonction: Intérieur; Fermeture du mur: Aucun
Type - Cotes - Hauteur: 210 cm; Largeur: 95 cm; Retour: 2.5 cm
Type - Données d'identification - Marque de type: 75; Nom du type: Ouverture Loge
Type - Matériaux et finitions - Cadre: Bois - Chêne
Type - Propriétés analytiques - Construction analytique: <Aucun>
OverallHeight: 212.5 cm; OverallWidth: 100 cm
Pset_DoorCommon - IsExternal: no; Reference: Ouverture en rectangle:Ouverture Loge
Pset_QuantityTakeOff - Reference: Ouverture en rectangle:Ouverture Loge
BaseQuantities - Height: 210 cm; Width: 95 cm; Area: 1.995 m2
Autre - ID hôte: Mur de base: Int. Voile BA 20 doublé; Famille: Ouverture en rectangle: Ouverture Loge; Famille et type: Ouverture en rectangle: Ouverture Loge; Hauteur sous linteau: 210 cm; ID du type: Ouverture en rectangle: Ouverture Loge; Type: Ouverture en rectangle: Ouverture Loge
Contraintes - Niveau: Niveau: 0 RDC; Hauteur de l'appui: 0 cm
Cotes - Surface: 1.59503 m2; Volume: 0.0297402 m3
Données d'identification - Identifiant: 176
Graphismes - Avec huisserie: yes
Phase de construction - Phase de création: Projet

# IfcDoor: PP (0.83m x 2.04m), Int. Simple:PP (0.83m x 2.04m):575037
In: 0 RDC
Type - OperationType: SINGLE_SWING_LEFT; ParameterTakesPrecedence: no; Sizeable: no; Material: Finition Peinture - Blanc satiné, Bois - Panneau de porte, Bois - Cadre de porte
Type - Autre - Catégorie: Portes; Nom de la famille: Int. Simple
Type - Construction - Fonction: Intérieur; Fermeture du mur: Par hôte
Type - Cotes - Epaisseur: 4 cm; Hauteur: 204 cm; Largeur: 83 cm
Type - Données d'identification - Marque de type: 13; Nom du type: PP (0.83m x 2.04m)
Type - Matériaux et finitions - Panneau: Bois - Panneau de porte; Poignée: Finition Peinture - Blanc satiné; Ajustement: Bois - Cadre de porte; Cadre: Bois - Cadre de porte
Type - Propriétés analytiques - Construction analytique: <Aucun>
Type - Int. Simple:PP (0.83m x 2.04m):575037 - PanelOperation: SWINGING
OverallHeight: 209 cm; OverallWidth: 93 cm
Pset_DoorCommon - IsExternal: no; Reference: Int. Simple:PP (0.83m x 2.04m)
Pset_QuantityTakeOff - Reference: Int. Simple:PP (0.83m x 2.04m)
BaseQuantities - Height: 204 cm; Width: 83 cm; Area: 1.6932 m2
Autre - Famille: Int. Simple: PP (0.83m x 2.04m); Famille et type: Int. Simple: PP (0.83m x 2.04m); ID du type: Int. Simple: PP (0.83m x 2.04m); Type: Int. Simple: PP (0.83m x 2.04m); ID hôte: Mur de base: Cloison de distribution 72/48 à ossature métal avec laine minérale; Hauteur sous linteau: 204 cm
Contraintes - Hauteur de l'appui: 0 cm; Niveau: Niveau: 0 RDC
Cotes - Surface: 2.34338 m2; Volume: 0.0802776 m3
Données d'identification - Commentaires: CF1/2h; Identifiant: 140
Graphismes - Angle d'ouverture 2D fixe: yes; Angle d'ouverture 3D: 0 deg
Phase de construction - Phase de création: Projet

# IfcDoor: PP (0.83m x 2.04m), Int. Simple:PP (0.83m x 2.04m):574840
In: 0 RDC
Type - OperationType: SINGLE_SWING_RIGHT; ParameterTakesPrecedence: no; Sizeable: no; Material: Finition Peinture - Blanc satiné, Bois - Panneau de porte, Bois - Cadre de porte
Type - Autre - Catégorie: Portes; Nom de la famille: Int. Simple
Type - Construction - Fonction: Intérieur; Fermeture du mur: Par hôte
Type - Cotes - Epaisseur: 4 cm; Hauteur: 204 cm; Largeur: 83 cm
Type - Données d'identification - Marque de type: 13; Nom du type: PP (0.83m x 2.04m)
Type - Matériaux et finitions - Panneau: Bois - Panneau de porte; Poignée: Finition Peinture - Blanc satiné; Ajustement: Bois - Cadre de porte; Cadre: Bois - Cadre de porte
Type - Propriétés analytiques - Construction analytique: <Aucun>
Type - Int. Simple:PP (0.83m x 2.04m):574840 - PanelOperation: SWINGING
OverallHeight: 209 cm; OverallWidth: 93 cm
Pset_DoorCommon - IsExternal: no; Reference: Int. Simple:PP (0.83m x 2.04m)
Pset_QuantityTakeOff - Reference: Int. Simple:PP (0.83m x 2.04m)
BaseQuantities - Height: 204 cm; Width: 83 cm; Area: 1.6932 m2
Autre - Famille: Int. Simple: PP (0.83m x 2.04m); Famille et type: Int. Simple: PP (0.83m x 2.04m); ID du type: Int. Simple: PP (0.83m x 2.04m); Type: Int. Simple: PP (0.83m x 2.04m); ID hôte: Mur de base: Cloison de distribution 72/48 à ossature métal avec laine minérale; Hauteur sous linteau: 204 cm
Contraintes - Hauteur de l'appui: 0 cm; Niveau: Niveau: 0 RDC
Cotes - Surface: 2.34338 m2; Volume: 0.0802776 m3
Données d'identification - Commentaires: CF1/2h; Identifiant: 139
Graphismes - Angle d'ouverture 2D fixe: yes; Angle d'ouverture 3D: 0 deg
Phase de construction - Phase de création: Projet

# IfcDoor: PP (0.83m x 2.04m), Int. Simple:PP (0.83m x 2.04m):562711
In: 0 RDC
Type - OperationType: SINGLE_SWING_RIGHT; ParameterTakesPrecedence: no; Sizeable: no; Material: Finition Peinture - Blanc satiné, Bois - Panneau de porte, Bois - Cadre de porte
Type - Int. Simple:PP (0.83m x 2.04m):562711 - PanelOperation: SWINGING
Type - Autre - Catégorie: Portes; Nom de la famille: Int. Simple
Type - Construction - Fonction: Intérieur; Fermeture du mur: Par hôte
Type - Cotes - Epaisseur: 4 cm; Hauteur: 204 cm; Largeur: 83 cm
Type - Données d'identification - Marque de type: 13; Nom du type: PP (0.83m x 2.04m)
Type - Matériaux et finitions - Panneau: Bois - Panneau de porte; Poignée: Finition Peinture - Blanc satiné; Ajustement: Bois - Cadre de porte; Cadre: Bois - Cadre de porte
Type - Propriétés analytiques - Construction analytique: <Aucun>
OverallHeight: 209 cm; OverallWidth: 93 cm
Pset_DoorCommon - IsExternal: no; Reference: Int. Simple:PP (0.83m x 2.04m)
Pset_QuantityTakeOff - Reference: Int. Simple:PP (0.83m x 2.04m)
BaseQuantities - Height: 204 cm; Width: 83 cm; Area: 1.6932 m2
Autre - ID hôte: Mur de base: Cloison de séparation 98/48 à ossature métal avec laine minérale; Famille: Int. Simple: PP (0.83m x 2.04m); Famille et type: Int. Simple: PP (0.83m x 2.04m); Hauteur sous linteau: 204 cm; ID du type: Int. Simple: PP (0.83m x 2.04m); Type: Int. Simple: PP (0.83m x 2.04m)
Contraintes - Hauteur de l'appui: 0 cm; Niveau: Niveau: 0 RDC
Cotes - Surface: 2.47377 m2; Volume: 0.0848094 m3
Données d'identification - Commentaires: + FP; Identifiant: 131
Graphismes - Angle d'ouverture 2D fixe: yes; Angle d'ouverture 3D: 0 deg
Phase de construction - Phase de création: Projet
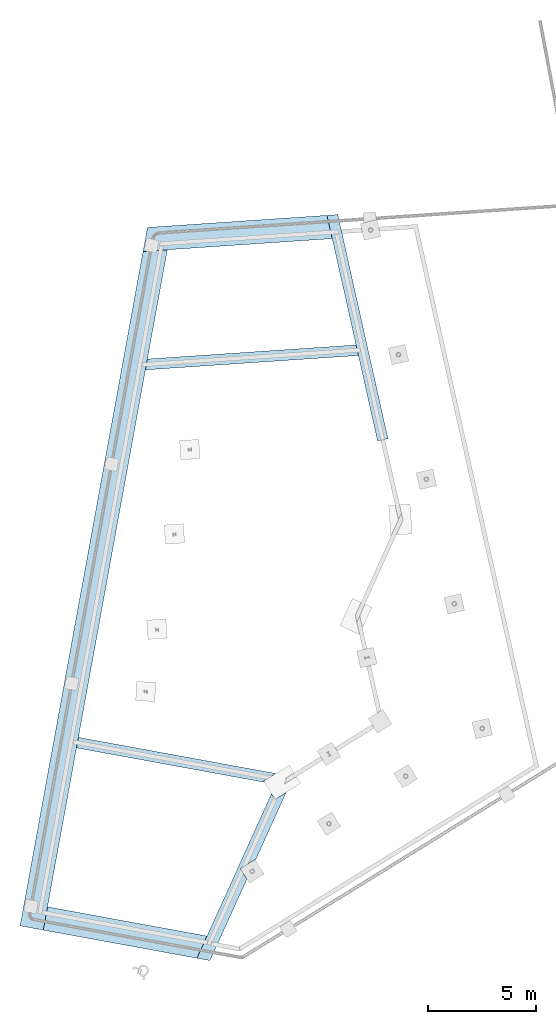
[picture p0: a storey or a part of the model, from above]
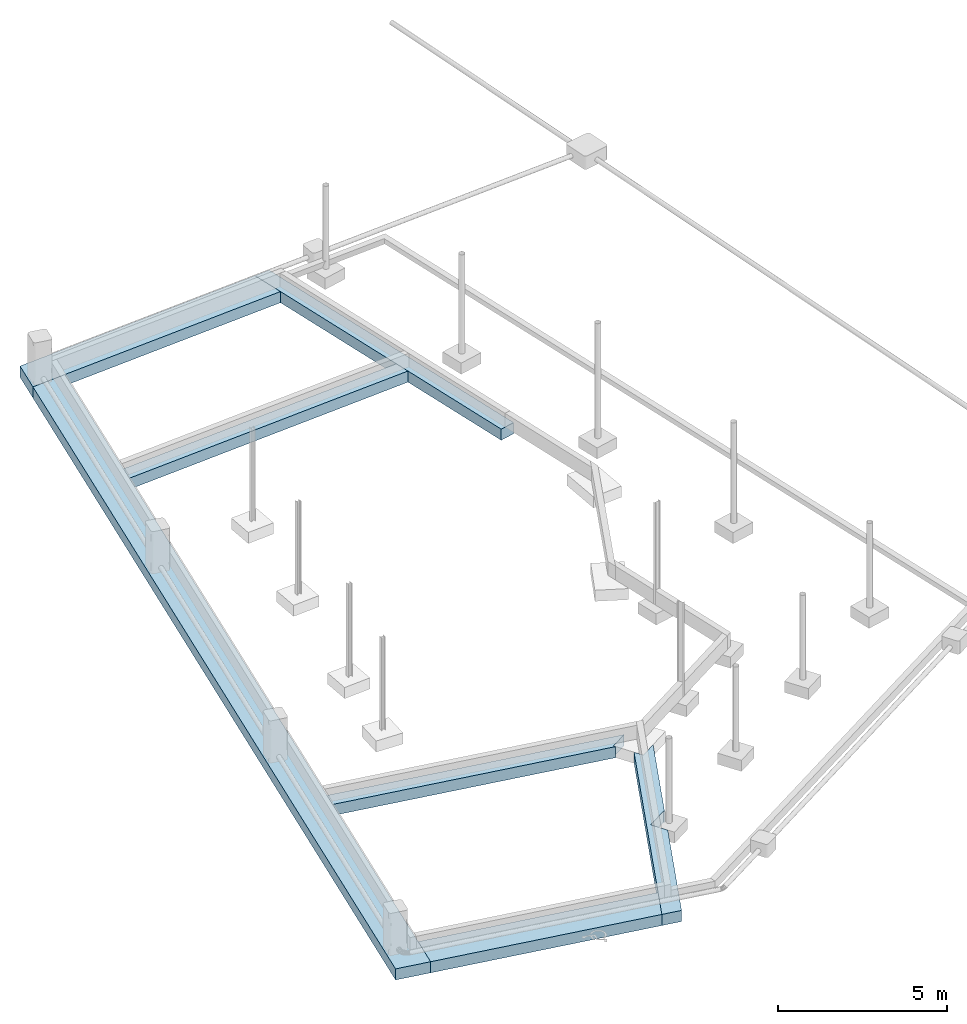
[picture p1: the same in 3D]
Properties of the parts of a building model (IFC2X3), part 3 of 5

# IfcDoor: PP (0.93m x 2.04m), Int. Simple:PP (0.93m x 2.04m):1618639
In: 0 RDC
Type - OperationType: SINGLE_SWING_LEFT; ParameterTakesPrecedence: no; Sizeable: no; Material: Finition Peinture - Blanc satiné, Bois - Panneau de porte
Type - Autre - Catégorie: Portes; Nom de la famille: Int. Simple
Type - Construction - Fonction: Intérieur; Fermeture du mur: Par hôte
Type - Cotes - Epaisseur: 4 cm; Hauteur: 204 cm; Largeur: 93 cm
Type - Données d'identification - Marque de type: 41; Nom du type: PP (0.93m x 2.04m)
Type - Matériaux et finitions - Ajustement: Bois - Panneau de porte; Cadre: Bois - Panneau de porte; Panneau: Bois - Panneau de porte; Poignée: Finition Peinture - Blanc satiné
Type - Propriétés analytiques - Construction analytique: <Aucun>
Type - Int. Simple:PP (0.93m x 2.04m):1618639 - PanelOperation: SWINGING
OverallHeight: 209 cm; OverallWidth: 103 cm
Pset_DoorCommon - IsExternal: no; Reference: Int. Simple:PP (0.93m x 2.04m)
Pset_QuantityTakeOff - Reference: Int. Simple:PP (0.93m x 2.04m)
BaseQuantities - Height: 204 cm; Width: 93 cm; Area: 1.8972 m2
Autre - Famille: Int. Simple: PP (0.93m x 2.04m); Famille et type: Int. Simple: PP (0.93m x 2.04m); ID du type: Int. Simple: PP (0.93m x 2.04m); Type: Int. Simple: PP (0.93m x 2.04m); ID hôte: Mur de base: Int. Voile BA 20 doublé; Hauteur sous linteau: 204 cm
Contraintes - Hauteur de l'appui: 0 cm; Niveau: Niveau: 0 RDC
Cotes - Surface: 3.57997 m2; Volume: 0.124072 m3
Données d'identification - Commentaires: CF1/2h + FP; Identifiant: 126
Graphismes - Angle d'ouverture 2D fixe: yes; Angle d'ouverture 3D: 0 deg
Phase de construction - Phase de création: Projet

# IfcDoor: PP (0.93m x 2.04m) (3)
In: 0 RDC
Type - OperationType: SINGLE_SWING_LEFT; ParameterTakesPrecedence: no; Sizeable: no; Material: Finition Peinture - Blanc satiné, Bois - Panneau de porte
Type - Autre - Catégorie: Portes; Nom de la famille: Int. Simple
Type - Construction - Fonction: Intérieur; Fermeture du mur: Par hôte
Type - Cotes - Epaisseur: 4 cm; Hauteur: 204 cm; Largeur: 93 cm
Type - Données d'identification - Marque de type: 41; Nom du type: PP (0.93m x 2.04m)
Type - Matériaux et finitions - Ajustement: Bois - Panneau de porte; Cadre: Bois - Panneau de porte; Panneau: Bois - Panneau de porte; Poignée: Finition Peinture - Blanc satiné
Type - Propriétés analytiques - Construction analytique: <Aucun>
Type - Int. Simple:PP (0.93m x 2.04m):567465 - PanelOperation: SWINGING
OverallHeight: 209 cm; OverallWidth: 103 cm
Pset_DoorCommon - IsExternal: no; Reference: Int. Simple:PP (0.93m x 2.04m)
Pset_QuantityTakeOff - Reference: Int. Simple:PP (0.93m x 2.04m)
BaseQuantities - Height: 204 cm; Width: 93 cm; Area: 1.8972 m2
Autre - ID hôte: Mur de base: Cloison de séparation 98/48 à ossature métal avec laine minérale; Famille: Int. Simple: PP (0.93m x 2.04m); Famille et type: Int. Simple: PP (0.93m x 2.04m); ID du type: Int. Simple: PP (0.93m x 2.04m); Type: Int. Simple: PP (0.93m x 2.04m)
Contraintes - Niveau: Niveau: 0 RDC
Cotes - Surface: 2.69507 m2; Volume: 0.0933124 m3
Graphismes - Angle d'ouverture 2D fixe: yes; Angle d'ouverture 3D: 0 deg
Phase de construction - Phase de création: Projet
Name (Int. Simple:PP (0.93m x 2.04m):...) | Hauteur sous linteau (cm) | Hauteur de l'appui (cm) | Commentaires | Identifiant
567465 | 279 | 75 | CF1/2h + FP | 134
574015 | 204 | 0 | CF1/2h + FP | 137
886736 | 204 | 0 | CF1/2h | 151

# IfcDoor: PP (0.93m x 2.04m) (2)
In: 0 RDC
Type - OperationType: SINGLE_SWING_RIGHT; ParameterTakesPrecedence: no; Sizeable: no; Material: Finition Peinture - Blanc satiné, Bois - Panneau de porte
Type - Autre - Catégorie: Portes; Nom de la famille: Int. Simple
Type - Construction - Fonction: Intérieur; Fermeture du mur: Par hôte
Type - Cotes - Epaisseur: 4 cm; Hauteur: 204 cm; Largeur: 93 cm
Type - Données d'identification - Marque de type: 41; Nom du type: PP (0.93m x 2.04m)
Type - Matériaux et finitions - Ajustement: Bois - Panneau de porte; Cadre: Bois - Panneau de porte; Panneau: Bois - Panneau de porte; Poignée: Finition Peinture - Blanc satiné
Type - Propriétés analytiques - Construction analytique: <Aucun>
Type - Int. Simple:PP (0.93m x 2.04m):562898 - PanelOperation: SWINGING
OverallHeight: 209 cm; OverallWidth: 103 cm
Pset_DoorCommon - IsExternal: no; Reference: Int. Simple:PP (0.93m x 2.04m)
Pset_QuantityTakeOff - Reference: Int. Simple:PP (0.93m x 2.04m)
BaseQuantities - Height: 204 cm; Width: 93 cm; Area: 1.8972 m2
Autre - Famille: Int. Simple: PP (0.93m x 2.04m); Famille et type: Int. Simple: PP (0.93m x 2.04m); ID du type: Int. Simple: PP (0.93m x 2.04m); Type: Int. Simple: PP (0.93m x 2.04m); Hauteur sous linteau: 204 cm; ID hôte: Mur de base: Cloison de distribution 72/48 à ossature métal avec laine minérale
Contraintes - Niveau: Niveau: 0 RDC; Hauteur de l'appui: 0 cm
Cotes - Surface: 2.56208 m2; Volume: 0.0886896 m3
Graphismes - Angle d'ouverture 2D fixe: yes; Angle d'ouverture 3D: 0 deg
Phase de construction - Phase de création: Projet
Name (Int. Simple:PP (0.93m x 2.04m):...) | Identifiant
562898 | 133 | Données d'identification - Commentaires: CF1/2h
1839471 | 175

# IfcDoor: PP (0.93m x 2.04m) (2)
In: 0 RDC
Type - OperationType: SINGLE_SWING_RIGHT; ParameterTakesPrecedence: no; Sizeable: no; Material: Finition Peinture - Blanc satiné, Bois - Panneau de porte
Type - Int. Simple:PP (0.93m x 2.04m):552072 - PanelOperation: SWINGING
Type - Autre - Catégorie: Portes; Nom de la famille: Int. Simple
Type - Construction - Fonction: Intérieur; Fermeture du mur: Par hôte
Type - Cotes - Epaisseur: 4 cm; Hauteur: 204 cm; Largeur: 93 cm
Type - Données d'identification - Marque de type: 41; Nom du type: PP (0.93m x 2.04m)
Type - Matériaux et finitions - Ajustement: Bois - Panneau de porte; Cadre: Bois - Panneau de porte; Panneau: Bois - Panneau de porte; Poignée: Finition Peinture - Blanc satiné
Type - Propriétés analytiques - Construction analytique: <Aucun>
OverallHeight: 209 cm; OverallWidth: 103 cm
Pset_DoorCommon - IsExternal: no; Reference: Int. Simple:PP (0.93m x 2.04m)
Pset_QuantityTakeOff - Reference: Int. Simple:PP (0.93m x 2.04m)
BaseQuantities - Height: 204 cm; Width: 93 cm; Area: 1.8972 m2
Autre - ID hôte: Mur de base: Cloison de séparation 98/48 à ossature métal avec laine minérale; Famille: Int. Simple: PP (0.93m x 2.04m); Famille et type: Int. Simple: PP (0.93m x 2.04m); Hauteur sous linteau: 204 cm; ID du type: Int. Simple: PP (0.93m x 2.04m); Type: Int. Simple: PP (0.93m x 2.04m)
Contraintes - Niveau: Niveau: 0 RDC; Hauteur de l'appui: 0 cm
Cotes - Surface: 2.69507 m2; Volume: 0.0933124 m3
Graphismes - Angle d'ouverture 2D fixe: yes; Angle d'ouverture 3D: 0 deg
Phase de construction - Phase de création: Projet
Name (Int. Simple:PP (0.93m x 2.04m):...) | Identifiant
552072 | 114
573939 | 136 | Données d'identification - Commentaires: CF1/2h + FP

# IfcDoor: PP (1.43m x 2.04m), Int. Tierce:PP (1.43m x 2.04m):552028
In: 0 RDC
Type - OperationType: DOUBLE_DOOR_SINGLE_SWING; ParameterTakesPrecedence: no; Sizeable: no; Material: Finition Peinture - Blanc satiné, Bois - Panneau de porte, Bois - Cadre de porte
Type - Int. Tierce:PP (1.43m x 2.04m):552028 - PanelOperation: SWINGING
Type - Autre - Catégorie: Portes; Nom de la famille: Int. Tierce
Type - Construction - Fonction: Intérieur; Fermeture du mur: Par hôte
Type - Cotes - Epaisseur: 4 cm; Hauteur: 204 cm; Largeur: 143 cm; Largeur du grand panneau: 90 cm
Type - Données d'identification - Marque de type: 53; Nom du type: PP (1.43m x 2.04m)
Type - Matériaux et finitions - Cadre: Bois - Cadre de porte; Coffrage de finition: Bois - Cadre de porte; Panneau: Bois - Panneau de porte; Poignée: Finition Peinture - Blanc satiné
Type - Propriétés analytiques - Coefficient d'apport thermique solaire: 0.86; Coefficient de transfert de chaleur (U): 5.5617; Construction analytique: Grandes fenêtres à vitrage simple; Résistance thermique (R): 0.179801; Transmission de la lumière visible: 0.9
OverallHeight: 209 cm; OverallWidth: 153 cm
Pset_DoorCommon - IsExternal: no; Reference: Int. Tierce:PP (1.43m x 2.04m); ThermalTransmittance: 5.5617 kg/K/s3
Pset_QuantityTakeOff - Reference: Int. Tierce:PP (1.43m x 2.04m)
BaseQuantities - Height: 204 cm; Width: 143 cm; Area: 2.9172 m2
Autre - ID hôte: Mur de base: Cloison de séparation 98/48 à ossature métal avec laine minérale; Famille: Int. Tierce: PP (1.43m x 2.04m); Famille et type: Int. Tierce: PP (1.43m x 2.04m); Hauteur sous linteau: 204 cm; ID du type: Int. Tierce: PP (1.43m x 2.04m); Type: Int. Tierce: PP (1.43m x 2.04m)
Contraintes - Hauteur de l'appui: 0 cm; Niveau: Niveau: 0 RDC
Cotes - Surface: 3.88317 m2; Volume: 0.135827 m3
Données d'identification - Commentaires: CF1/2h + FP; Identifiant: 113
Graphismes - Angle d'ouverture 2D fixe: yes; Angle d'ouverture 3D: 0 deg
Phase de construction - Phase de création: Projet

# IfcDoor: PP (1.80m x 2.04m), Int. Double:PP (1.80m x 2.04m):528869
In: 0 RDC
Type - OperationType: DOUBLE_DOOR_SINGLE_SWING; ParameterTakesPrecedence: no; Sizeable: no; Material: Bois - Panneau de porte, Finition Peinture - Blanc satiné
Type - Int. Double:PP (1.80m x 2.04m):528869 - PanelOperation: SWINGING
Type - Autre - Catégorie: Portes; Nom de la famille: Int. Double
Type - Construction - Fonction: Intérieur; Fermeture du mur: Par hôte
Type - Contraintes - LP: 90 cm
Type - Cotes - Epaisseur: 4 cm; Hauteur: 204 cm; Largeur: 180 cm
Type - Données d'identification - Marque de type: 49; Nom du type: PP (1.80m x 2.04m)
Type - Matériaux et finitions - Cadre: Bois - Panneau de porte; Coffrage de finition: Bois - Panneau de porte; Panneau: Bois - Panneau de porte; Poignée: Finition Peinture - Blanc satiné
Type - Propriétés analytiques - Coefficient d'apport thermique solaire: 0.78; Coefficient de transfert de chaleur (U): 3.6886; Construction analytique: Simple vitrage Pilkington 1/8 po.; Résistance thermique (R): 0.271106; Transmission de la lumière visible: 0.9
OverallHeight: 209 cm; OverallWidth: 190 cm
Pset_DoorCommon - IsExternal: no; Reference: Int. Double:PP (1.80m x 2.04m); ThermalTransmittance: 3.6886 kg/K/s3
Pset_QuantityTakeOff - Reference: Int. Double:PP (1.80m x 2.04m)
BaseQuantities - Height: 204 cm; Width: 180 cm; Area: 3.672 m2
Autre - Famille: Int. Double: PP (1.80m x 2.04m); Famille et type: Int. Double: PP (1.80m x 2.04m); Hauteur sous linteau: 204 cm; ID du type: Int. Double: PP (1.80m x 2.04m); ID hôte: Mur de base: Cloison de séparation 98/48 à ossature métal avec laine minérale; Type: Int. Double: PP (1.80m x 2.04m)
Contraintes - Niveau: Niveau: 0 RDC; Hauteur de l'appui: 0 cm
Cotes - Surface: 4.70198 m2; Volume: 0.167289 m3
Données d'identification - Commentaires: CF1/2h + FP; Identifiant: 105
Graphismes - Angle d'ouverture (à droite): 0 deg; Angle d'ouverture (à gauche): 0 deg; Angle d'ouverture 2D fixe: yes
Phase de construction - Phase de création: Projet

# IfcFlowController: Regard EP 600x600 (7)
In: -1 Soubassement
Type - Material: Béton, précoulé
Type - Autre - Catégorie: Accessoire de canalisation; Nom de la famille: Regard Eau pluviale 2
Type - Cotes - hauteur connecteur: 8 cm; Larg. 1: 60 cm; Larg. 2: 60 cm; Larg. Couv 1: 60 cm; Larg. Couv 2: 60 cm; Larg. Fond 1: 60 cm; Larg. Fond 2: 60 cm; Ø connecteur Ar: 16 cm; Ø connecteur Av: 16 cm; Ø connecteur D: 16 cm
Type - Données d'identification - Nom du type: Regard EP 600x600
Pset_DistributionFlowElementCommon - Reference: Regard Eau pluviale 2:Regard EP 600x600; sets with these values: 2
Autre - Famille: Regard Eau pluviale 2: Regard EP 600x600; Famille et type: Regard Eau pluviale 2: Regard EP 600x600; Hauteur int.: 150 cm; ID du type: Regard Eau pluviale 2: Regard EP 600x600; Type: Regard Eau pluviale 2: Regard EP 600x600
Contraintes - Niveau: Niveau: -1 Soubassement; Niveau de base: Niveau: -1 Soubassement; Décalage inférieur: 5 cm
Cotes - Taille: 160 mmø-160 mmø-160 mmø; Taille maximale: 16 cm; Taille minimale: 16 cm
Génie climatique - Abréviation du système: EP; Type de système: Système de canalisation: Eau Pluviales
Isolation - Epaisseur d'isolation: 0 cm; Taille globale: 160 mmø-160 mmø-160 mmø
Phase de construction - Phase de création: Projet
Name (Regard Eau pluviale 2:Regard EP 600x600:...) | Décalage supérieur (cm) | Niveau supérieur | Surface (m2) | Volume (m3) | Classification du système | Nom du système = Group
1963935 | -2 | Niveau: TN arrière | 3.92331 | 0.183987 | Alimentation hydraulique,Eau froide sanitaire,Alimentation hydraulique | EP 5
1964383 | -2 | Niveau: TN arrière | 3.92331 | 0.183987 | Alimentation hydraulique,Eau froide sanitaire,Alimentation hydraulique | EP 5
1964598 | -2 | Niveau: TN arrière | 3.92331 | 0.183987 | Eau froide sanitaire,Alimentation hydraulique | EP 5
1981700 | -2 | Niveau: TN arrière | 3.92331 | 0.183987 | Eau froide sanitaire | EP 3
1981944 | -7 | Niveau: 0 RDC | 1.71246 | 0.0734454 | Alimentation hydraulique,Eau froide sanitaire,Alimentation hydraulique | EP 2
1983183 | -7 | Niveau: 0 RDC | 1.71246 | 0.0734454 | Eau froide sanitaire,Alimentation hydraulique | EP 5
2037868 | -7 | Niveau: 0 RDC | 1.71246 | 0.0734454 | Alimentation hydraulique,Eau froide sanitaire,Alimentation hydraulique | EP 1 | Données d'identification - Identifiant: 2

# IfcFlowController: Regard EP 900x900 (2)
In: -1 Soubassement
Type - Material: Béton, précoulé
Type - Autre - Catégorie: Accessoire de canalisation; Nom de la famille: Regard Eau pluviale 2
Type - Cotes - Hauteur connecteur: 8 cm; Larg. 1: 90 cm; Larg. 2: 90 cm; Larg. Couv 1: 90 cm; Larg. Couv 2: 90 cm; Larg. Fond 1: 90 cm; Larg. Fond 2: 90 cm; Ø connecteur Ar: 16 cm; Ø connecteur Av: 16 cm; Ø connecteur D: 16 cm
Type - Données d'identification - Nom du type: Regard EP 900x900
Pset_DistributionFlowElementCommon - Reference: Regard Eau pluviale 2:Regard EP 900x900; sets with these values: 2
Autre - Famille: Regard Eau pluviale 2: Regard EP 900x900; Famille et type: Regard Eau pluviale 2: Regard EP 900x900; Hauteur int.: 150 cm; ID du type: Regard Eau pluviale 2: Regard EP 900x900; Type: Regard Eau pluviale 2: Regard EP 900x900
Contraintes - Niveau: Niveau: -1 Soubassement; Niveau de base: Niveau: -1 Soubassement; Niveau supérieur: Niveau: 0 RDC; Décalage inférieur: 5 cm; Décalage supérieur: -7 cm
Cotes - Surface: 3.18846 m2; Taille: 160 mmø-160 mmø-160 mmø; Taille maximale: 16 cm; Taille minimale: 16 cm; Volume: 0.141245 m3
Génie climatique - Type de système: Système de canalisation: Eau Pluviales; Abréviation du système: EP; Classification du système: Eau froide sanitaire; Nom du système: EP 6
Isolation - Epaisseur d'isolation: 0 cm; Taille globale: 160 mmø-160 mmø-160 mmø
Phase de construction - Phase de création: Projet
Group: EP 6
Name (Regard Eau pluviale 2:Regard EP 900x900:...)
1982875
2039043 | Données d'identification - Identifiant: 3

# IfcFlowFitting: Coude 45 (5)
In: -1 Soubassement
Type - Material: PVC
Type - Autre - Catégorie: Raccords de gaine; Nom de la famille: coude 45
Type - Cotes - ØCoude: 16 cm
Type - Données d'identification - Nom du type: Coude 45; Numéro OmniClass: 23.75.70.14; Titre OmniClass: Air Ductwork
Pset_DistributionFlowElementCommon - Reference: coude 45:Coude 45; sets with these values: 2
Autre - Famille: coude 45: Coude 45; Famille et type: coude 45: Coude 45; ID du type: coude 45: Coude 45; Type: coude 45: Coude 45
Contraintes - Niveau: Niveau: -1 Soubassement; Décalage: 18 cm; Hôte: Niveau : -1 Soubassement
Cotes - Rayon du centre: 50 cm
Génie climatique - Epaisseur d'isolation: 0 cm; Epaisseur du revêtement: 0 cm; Abréviation du système: EP; Type de système: Système de canalisation: Eau Pluviales
Graphismes - Utiliser l'échelle d'annotations: no
Isolation - Epaisseur d'isolation: 0 cm
Phase de construction - Phase de création: Projet
Revêtement - Epaisseur du revêtement: 0 cm
Name (coude 45:Coude 45:...) | Angle (deg) | Longueur1 (cm) | Surface (m2) | Volume (m3) | Classification du système | Nom du système = Group
2034771 | 42 | 19.1932 | 0.0591815 | 0.00312612 | Alimentation hydraulique | EP 5
2035501 | 45 | 20.7107 | 0.0639602 | 0.00350841 | Alimentation hydraulique | EP 5
2035645 | 45 | 20.7107 | 0.0639602 | 0.00350841 | Alimentation hydraulique | EP 5
2038890 | 69 | 34.364 | 0.115302 | 0.00761559 | Eau froide sanitaire | EP 6
2040593 | 76 | 39.0643 | 0.137141 | 0.00936268 | Eau froide sanitaire | EP 2

# IfcFlowSegment: Canalisation:Canalisation EP (12)
In: -1 Soubassement
Type - Autre - Catégorie: Canalisation; Nom de la famille: Canalisation
Type - Données d'identification - Nom du type: Canalisation EP
Autre - Famille: Canalisation: Canalisation EP; Famille et type: Canalisation: Canalisation EP; ID du type: Canalisation: Canalisation EP; Type: Canalisation: Canalisation EP; sets with these values: 2
Contraintes - Décalage de départ: 18 cm; Décalage extrémité: 18 cm; Décaler: 18 cm; Inclinaison: 0; Justification horizontale: Centre; Justification verticale: Milieu; Niveau de référence: Niveau: -1 Soubassement
Cotes - Diamètre extérieur: 16 cm; Diamètre intérieur: 15.8 cm; Taille: 160 mmø; sets with these values: 2
Génie climatique - Type de système: Système de canalisation: Eau Pluviales; Abréviation du système: EP; Classification du système: Eau froide sanitaire; Diamètre: 16 cm; Inverser l'élévation: 86960.1 cm; Matériau: Plastique; Nomenclature/type: Types de nomenclatures de canalisations: Nomenclature 80; Rugosité: 0.000254 cm; Segment de canalisation: Plastique - Nomenclature 80; Type de connexion: Générique
Génie climatique - Débit - Débit: 0 m3/s; Débit par appareil: 0; Débit supplémentaire: 0 m3/s; Etat du flux: Laminaire; Facteur de frottement: 0; Frottement: 0; Nombre de Reynolds: 0; Perte de pression: 0 Pa; Rugosité relative: 0.0000160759; Vitesse: 0 m/s
Isolation - Epaisseur d'isolation: 0 cm; Taille globale: 160 mmø; sets with these values: 2
Phase de construction - Phase de création: Projet; sets with these values: 2
Pset_DistributionFlowElementCommon - Reference: Canalisation:Canalisation EP; sets with these values: 2
Pset_FlowSegmentDuctSegment - sets with these values: 2
Name (Canalisation:Canalisation EP:...) | Longueur (cm) = Length (cm) | Coupe | Nom du système = Group | Surface (m2) | Contraintes, sets with these values = Génie climatique - Débit, sets with these values
2000548 | 947.651 | 4 | EP 2 | 4.76341
2000957 | 974.611 | 3 | EP 5 | 4.89893 | 2
2002122 | 992.755 | 1 | EP 5 | 4.99013 | 2
2026979 | 975.48 | 6 | EP 5 | 4.9033 | 2
2027032 | 4.88672 | 6 | EP 5 | 0.0245633 | 2 | Génie climatique - sets with these values: 2
2035817 | 214.893 | 6 | EP 5 | 1.08017 | 2 | Génie climatique - sets with these values: 2
2038155 | 1130.48 | 10 | EP 1 | 5.68241 | 2
2039150 | 840 | 13 | EP 6 | 4.2223 | 2 | Génie climatique - sets with these values: 2
2039167 | 2238.21 | 14 | EP 6 | 11.2505 | 2 | Génie climatique - sets with these values: 2
2039489 | 899 | 3 | EP 2 | 4.51887 | 2 | Génie climatique - sets with these values: 2
2040104 | 733.202 | 15 | EP 1 | 3.68548 | 2 | Génie climatique - sets with these values: 2
2047433 | 972 | 8 | EP 3 | 4.8858 | 2

# IfcFlowSegment: Gouttière:Gouttière demi-ronde 33:91549 (3)
Type - ElementType: Gouttière:Gouttière demi-ronde 33:91549; PredefinedType: GUTTER
Pset_DistributionFlowElementCommon - Reference: Gouttière:Gouttière demi-ronde 33; sets with these values: 2
Pset_FlowSegmentDuctSegment - sets with these values: 2
Autre - Catégorie: Gouttières; Famille: Gouttière: Gouttière demi-ronde 33; Famille et type: Gouttière: Gouttière demi-ronde 33; ID du type: Gouttière: Gouttière demi-ronde 33; Type: Gouttière: Gouttière demi-ronde 33
Contraintes - Décalage horizontal du profil: 0 cm; Décalage vertical du profil: 0 cm
Phase de construction - Phase de création: Projet
Profil - Angle: 0 deg
Autre(Type) - Catégorie: Gouttières; Nom de la famille: Gouttière
Construction(Type) - Profil: Gouttière demi-ronde: 33
Données d'identification(Type) - Nom du type: Gouttière demi-ronde 33
Matériaux et finitions(Type) - Matériau: Acier zingué galvanisé
Name (Gouttière:Gouttière demi-ronde 33:...) | In | Length (cm) = Longueur (cm)
1625279 | 1 Toiture auvent | 1414.13
1798596 | 1 Toiture auvent | 161.45
1945219 | 2 Toiture batiment | 3214.12

# IfcFlowTerminal: Bac à douche rectangulaire:90 x 90 cm, Bac à douche rectangulaire:90 x 90 cm:564111
In: 0 RDC
Material: Métal - Chrome, Acrylique - Blanc
Pset_DistributionFlowElementCommon - Reference: Bac à douche rectangulaire:90 x 90 cm; sets with these values: 2
Autre - Catégorie: Appareils sanitaires; Famille: Bac à douche rectangulaire: 90 x 90 cm; Famille et type: Bac à douche rectangulaire: 90 x 90 cm; ID du type: Bac à douche rectangulaire: 90 x 90 cm; Type: Bac à douche rectangulaire: 90 x 90 cm
Contraintes - Se déplace avec les éléments voisins: no; Niveau: Niveau: 0 RDC; Décalage: -6 cm; Hôte: Niveau : 0 RDC
Cotes - Surface: 0.927789 m2; Volume: 0.0182 m3
Données d'identification - Identifiant: 29
Phase de construction - Phase de création: Projet
Autre(Type) - Catégorie: Appareils sanitaires; Nom de la famille: Bac à douche rectangulaire
Cotes(Type) - Largeur: 90 cm; Profondeur: 90 cm
Données d'identification(Type) - Nom du type: 90 x 90 cm; Numéro OmniClass: 23.45.00.00; Titre OmniClass: Sanitary, Laundry, and Cleaning Equipment
Matériaux et finitions(Type) - Récepteur: Acrylique - Blanc

# IfcFlowTerminal: Descente Eau pluviale:EP (7)
In: 0 RDC
Pset_DistributionFlowElementCommon - Reference: Descente Eau pluviale:EP; sets with these values: 2
Autre - Catégorie: Appareils sanitaires; Famille: Descente Eau pluviale: EP; Famille et type: Descente Eau pluviale: EP; ID du type: Descente Eau pluviale: EP; Type: Descente Eau pluviale: EP
Contraintes - Niveau: Niveau: 0 RDC; Niveau supérieur: Niveau: 0 RDC; Niveau de base: Niveau: 0 RDC
Cotes - Hauteur de la naissance: 30 cm; Hauteur de la pente: 9 cm
Données d'identification - Commentaires: Ø80
Phase de construction - Phase de création: Projet
Autre(Type) - Catégorie: Appareils sanitaires; Nom de la famille: Descente Eau pluviale
Cotes(Type) - Rayon des coudes: 6 cm; R EXT EP: 4 cm; R INT EP: 3.9 cm
Données d'identification(Type) - Nom du type: EP
Name (Descente Eau pluviale:EP:...) | Décalage inférieur (cm) | Décalage supérieur (cm) | Débord toiture (cm) | Surface (m2) | Volume (m3) | Identifiant
1624435 | 100 | 315 | 21.5 | 0.564694 | 0.00056442 | 41
1624436 | 0 | 263 | 28 | 0.697733 | 0.000697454 | 43
1624437 | 0 | 263 | 109.176 | 0.891996 | 0.000891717 | 46
1624438 | 0 | 263 | 104 | 0.879297 | 0.000879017 | 47
1624439 | 100 | 315 | 21.5 | 0.564694 | 0.00056442 | 49
1956689 | 100 | 315 | 21.5 | 0.564694 | 0.00056442 | 50
1957019 | 100 | 315 | 21.5 | 0.564694 | 0.00056442 | 51

# IfcFlowTerminal: Evier double - Encastrable:1000 mm x 535 mm, Evier double - Encastrable:1000 mm x 535 mm:574365
In: 0 RDC
Material: Porcelaine - Lin, Métal - Acier, Poli
Pset_DistributionFlowElementCommon - Reference: Evier double - Encastrable:1000 mm x 535 mm; sets with these values: 2
Autre - Catégorie: Appareils sanitaires; Famille: Evier double - Encastrable: 1000 mm x 535 mm; Famille et type: Evier double - Encastrable: 1000 mm x 535 mm; ID du type: Evier double - Encastrable: 1000 mm x 535 mm; Type: Evier double - Encastrable: 1000 mm x 535 mm
Contraintes - Niveau: Niveau: 0 RDC; Décalage: 0 cm; Se déplace avec les éléments voisins: no; Hôte: Niveau : 0 RDC
Cotes - Surface: 1.49865 m2; Volume: 0.019121 m3
Données d'identification - Identifiant: 33
Phase de construction - Phase de création: Projet
Autre(Type) - Catégorie: Appareils sanitaires; Nom de la famille: Evier double - Encastrable
Cotes(Type) - Hauteur du plan de travail: 85 cm; Largeur: 120 cm; Profondeur: 55 cm
Données d'identification(Type) - Nom du type: 1000 mm x 535 mm
Matériaux et finitions(Type) - Evier: Porcelaine - Lin; Robinet: Métal - Acier, Poli

# IfcFlowTerminal: Lavabo encastrable1:Lavabo encastrable (2)
In: 0 RDC
Material: Métal - Chrome poli, Porcelaine - Blanche
Pset_DistributionFlowElementCommon - Reference: Lavabo encastrable1:Lavabo encastrable; sets with these values: 2
Autre - Catégorie: Appareils sanitaires; Famille: Lavabo encastrable1: Lavabo encastrable; Famille et type: Lavabo encastrable1: Lavabo encastrable; ID du type: Lavabo encastrable1: Lavabo encastrable; Type: Lavabo encastrable1: Lavabo encastrable
Contraintes - Niveau: Niveau: 0 RDC; Se déplace avec les éléments voisins: no; Décalage: 70 cm; Hôte: Niveau : 0 RDC
Cotes - Surface: 0.294456 m2; Volume: 0.00257494 m3
Phase de construction - Phase de création: Projet
Autre(Type) - Catégorie: Appareils sanitaires; Nom de la famille: Lavabo encastrable1
Données d'identification(Type) - Nom du type: Lavabo encastrable
Matériaux et finitions(Type) - Matériau - Evier: Porcelaine - Blanche; Matériau - Robinet: Métal - Chrome poli
Name (Lavabo encastrable1:Lavabo encastrable:...) | Identifiant
563038 | 23
563137 | 24

# IfcFlowTerminal: Urinoir:Urinoir (2)
In: 0 RDC
Material: Métal - Chrome poli, Porcelaine - Blanche
Pset_DistributionFlowElementCommon - Reference: Urinoir:Urinoir; sets with these values: 2
Autre - Catégorie: Appareils sanitaires; Famille: Urinoir: Urinoir; Famille et type: Urinoir: Urinoir; ID du type: Urinoir: Urinoir; Type: Urinoir: Urinoir
Contraintes - Décalage: 0 cm; Se déplace avec les éléments voisins: no; Niveau: Niveau: 0 RDC; Hôte: Niveau : 0 RDC
Cotes - Surface: 0.31175 m2; Volume: 0.0111932 m3
Phase de construction - Phase de création: Projet
Autre(Type) - Catégorie: Appareils sanitaires; Nom de la famille: Urinoir
Données d'identification(Type) - Nom du type: Urinoir
Matériaux et finitions(Type) - Matériau - Cuvette: Porcelaine - Blanche; Matériau - Raccords: Métal - Chrome poli
Name (Urinoir:Urinoir:...) | Identifiant
563397 | 25
563496 | 26

# IfcFlowTerminal: Vasque à poser:50 x 42 x 14 cm, Vasque à poser:50 x 42 x 14 cm:624636
In: 0 RDC
Material: Métal - Chrome, Céramique - Blanc
Pset_DistributionFlowElementCommon - Reference: Vasque à poser:50 x 42 x 14 cm; sets with these values: 2
Autre - Catégorie: Appareils sanitaires; Famille: Vasque à poser: 50 x 42 x 14 cm; Famille et type: Vasque à poser: 50 x 42 x 14 cm; ID du type: Vasque à poser: 50 x 42 x 14 cm; Type: Vasque à poser: 50 x 42 x 14 cm
Contraintes - Se déplace avec les éléments voisins: no; Niveau: Niveau: 0 RDC; Décalage: 90 cm; Hôte: Niveau : 0 RDC
Cotes - Surface: 0.555434 m2; Volume: 0.0177081 m3
Données d'identification - Identifiant: 36
Phase de construction - Phase de création: Projet
Autre(Type) - Catégorie: Appareils sanitaires; Nom de la famille: Vasque à poser
Cotes(Type) - Epaisseur: 14 cm; Largeur: 60 cm; Profondeur: 50 cm
Données d'identification(Type) - Nom du type: 50 x 42 x 14 cm; Numéro OmniClass: 23.45.00.00; Titre OmniClass: Sanitary, Laundry, and Cleaning Equipment
Matériaux et finitions(Type) - Vasque: Céramique - Blanc

# IfcFlowTerminal: WC mural - 03:520 x 370mm (2)
In: 0 RDC
Material: Porcelaine - Blanche
Pset_DistributionFlowElementCommon - Reference: WC mural - 03:520 x 370mm; sets with these values: 2
Autre - Catégorie: Appareils sanitaires; Famille: WC mural - 03: 520 x 370mm; Famille et type: WC mural - 03: 520 x 370mm; ID du type: WC mural - 03: 520 x 370mm; Type: WC mural - 03: 520 x 370mm
Contraintes - Niveau: Niveau: 0 RDC; Se déplace avec les éléments voisins: no; Décalage: 20 cm; Hôte: Niveau : 0 RDC
Cotes - Surface: 0.506492 m2; Volume: 0.0167364 m3
Phase de construction - Phase de création: Projet
Autre(Type) - Catégorie: Appareils sanitaires; Nom de la famille: WC mural - 03
Données d'identification(Type) - Nom du type: 520 x 370mm
Matériaux et finitions(Type) - Matériau: Porcelaine - Blanche
Name (WC mural - 03:520 x 370mm:...) | Identifiant
569469 | 31
575085 | 34

# IfcFlowTerminal: WC à réservoir:WC à réservoir (2)
In: 0 RDC
Material: Porcelaine - Blanche, Métal - Chrome
Pset_DistributionFlowElementCommon - Reference: WC à réservoir:WC à réservoir; sets with these values: 2
Autre - Catégorie: Appareils sanitaires; Famille: WC à réservoir: WC à réservoir; Famille et type: WC à réservoir: WC à réservoir; ID du type: WC à réservoir: WC à réservoir; Type: WC à réservoir: WC à réservoir
Contraintes - Niveau: Niveau: 0 RDC; Décalage: 0 cm; Se déplace avec les éléments voisins: no; Hôte: Niveau : 0 RDC
Cotes - Surface: 1.0705 m2; Volume: 0.0431081 m3
Phase de construction - Phase de création: Projet
Autre(Type) - Catégorie: Appareils sanitaires; Nom de la famille: WC à réservoir
Données d'identification(Type) - Nom du type: WC à réservoir
Matériaux et finitions(Type) - Matériau: Porcelaine - Blanche; Matériau de bouton: Métal - Chrome
Name (WC à réservoir:WC à réservoir:...) | Identifiant
517492 | 45
2141218 | 55 | Phase de construction - Phase de démolition: Conformité PMR

# IfcFooting: Semelle filante:SF1 (3)
In: -1 Soubassement
PredefinedType: STRIP_FOOTING; Material: Maçonnerie - Béton
Pset_QuantityTakeOff - Reference: Semelle filante:SF1; sets with these values: 3
Autre - Catégorie: Fondations; Famille: Semelle filante: SF1; Famille et type: Semelle filante: SF1; ID du type: Semelle filante: SF1; Type: Semelle filante: SF1
Cotes - Elévation à la base: 86910 cm; Elévation en haut: 86950 cm; Etude de l'élévation à la base: 86910 cm; Etude de l'élévation en haut: 86950 cm; Largeur: 50 cm
Phase de construction - Phase de création: Projet
Structure - Activer le modèle analytique: yes; Enrobage d'armature - Autres faces: Paramètres de l'enrobage d'armature: Enrobage d'armature 1; Enrobage d'armature - Face inférieure: Paramètres de l'enrobage d'armature: Enrobage d'armature 1; Enrobage d'armature - Face supérieure: Paramètres de l'enrobage d'armature: Enrobage d'armature 1
Autre(Type) - Catégorie: Fondations; Nom de la famille: Semelle filante
Cotes(Type) - Epaisseur de fondation: 40 cm; Largeur côté extérieur: 15 cm; Largeur côté intérieur: 15 cm; Longueur de l'extension de fin par défaut: 0 cm; Ne pas couper aux insertions: no
Données d'identification(Type) - Nom du type: SF1
Matériaux et finitions(Type) - Matériau structurel: Maçonnerie - Béton
Structure(Type) - Utilisation structurelle: Soutènement
Name (Semelle filante:SF1:...) | Longueur (cm) | Surface (m2) | Volume (m3) | Commentaires
927398 | 1020.36 | 4.90241 | 1.96096 | 50x30x40 +GB20cm
927535 | 984.169 | 4.52281 | 1.80912 | 50x30x40 +GB20cm
930697 | 980.689 | 5.35105 | 2.14042 | 50x40 +GB20cm

# IfcFooting: Semelle filante:SF2 (3)
In: -1 Soubassement
PredefinedType: STRIP_FOOTING; Material: Maçonnerie - Béton
Pset_QuantityTakeOff - Reference: Semelle filante:SF2; sets with these values: 3
Autre - Catégorie: Fondations; Famille: Semelle filante: SF2; Famille et type: Semelle filante: SF2; ID du type: Semelle filante: SF2; Type: Semelle filante: SF2
Cotes - Elévation à la base: 86910 cm; Elévation en haut: 86950 cm; Etude de l'élévation à la base: 86910 cm; Etude de l'élévation en haut: 86950 cm; Largeur: 110 cm
Données d'identification - Commentaires: 110x40 +GB 20cm
Phase de construction - Phase de création: Projet
Structure - Enrobage d'armature - Autres faces: Paramètres de l'enrobage d'armature: Enrobage d'armature 1; Enrobage d'armature - Face inférieure: Paramètres de l'enrobage d'armature: Enrobage d'armature 1; Enrobage d'armature - Face supérieure: Paramètres de l'enrobage d'armature: Enrobage d'armature 1
Autre(Type) - Catégorie: Fondations; Nom de la famille: Semelle filante
Cotes(Type) - Longueur de l'extension de fin par défaut: 0 cm; Ne pas couper aux insertions: no; Epaisseur de fondation: 40 cm; Largeur côté extérieur: 70 cm; Largeur côté intérieur: 20 cm
Données d'identification(Type) - Nom du type: SF2
Matériaux et finitions(Type) - Matériau structurel: Maçonnerie - Béton
Structure(Type) - Utilisation structurelle: Soutènement
Name (Semelle filante:SF2:...) | Longueur (cm) | Surface (m2) | Volume (m3) | Activer le modèle analytique
1804496 | 835.5 | 9.43848 | 3.77539 | yes
1907766 | 3156.02 | 35.1616 | 14.0647 | no
2185657 | 782.909 | 8.12568 | 3.25027 | no

# IfcFooting: Semelle filante:SF3, Semelle filante:SF3:1230851
In: -1 Soubassement
PredefinedType: STRIP_FOOTING; Material: Maçonnerie - Béton
Pset_QuantityTakeOff - Reference: Semelle filante:SF3; sets with these values: 3
Autre - Catégorie: Fondations; Famille: Semelle filante: SF3; Famille et type: Semelle filante: SF3; ID du type: Semelle filante: SF3; Type: Semelle filante: SF3
Cotes - Elévation à la base: 86910 cm; Elévation en haut: 86950 cm; Etude de l'élévation à la base: 86910 cm; Etude de l'élévation en haut: 86950 cm; Largeur: 60 cm; Longueur: 855.075 cm; Surface: 4.7507 m2; Volume: 1.90028 m3
Données d'identification - Commentaires: 60x40 +GB 20cm
Phase de construction - Phase de création: Projet
Structure - Activer le modèle analytique: yes; Enrobage d'armature - Autres faces: Paramètres de l'enrobage d'armature: Enrobage d'armature 1; Enrobage d'armature - Face inférieure: Paramètres de l'enrobage d'armature: Enrobage d'armature 1; Enrobage d'armature - Face supérieure: Paramètres de l'enrobage d'armature: Enrobage d'armature 1
Autre(Type) - Catégorie: Fondations; Nom de la famille: Semelle filante
Cotes(Type) - Longueur de l'extension de fin par défaut: 0 cm; Ne pas couper aux insertions: no; Epaisseur de fondation: 40 cm; Largeur côté extérieur: 25 cm; Largeur côté intérieur: 15 cm
Données d'identification(Type) - Nom du type: SF3
Matériaux et finitions(Type) - Matériau structurel: Maçonnerie - Béton
Structure(Type) - Utilisation structurelle: Soutènement

# IfcFurnishingElement: 1200mm, Placard - Porte double unité pour évier:1200mm:1900138
In: 0 RDC
Type - Material: Bois - Mélaminé blanc, Plastique - Noir
Type - Autre - Catégorie: Meubles de rangement; Nom de la famille: Placard - Porte double unité pour évier
Type - Cotes - Hauteur: 90 cm; Hauteur de plinthe: 16 cm; Largeur: 120 cm; Profondeur: 60 cm; Profondeur de plinthe: 3.5 cm
Type - Données d'identification - Nom du type: 1200mm
Type - Matériaux et finitions - Matériau de placard: Bois - Mélaminé blanc; Matériau de poignée: Plastique - Noir; Matériau de porte/tiroir: Bois - Mélaminé blanc
Pset_QuantityTakeOff - Reference: Placard - Porte double unité pour évier:1200mm
Autre - Famille: Placard - Porte double unité pour évier: 1200mm; Famille et type: Placard - Porte double unité pour évier: 1200mm; ID du type: Placard - Porte double unité pour évier: 1200mm; Type: Placard - Porte double unité pour évier: 1200mm
Contraintes - Décalage: 0 cm; Se déplace avec les éléments voisins: no; Niveau: Niveau: 0 RDC; Hôte: Niveau : 0 RDC
Cotes - Surface: 5.1115 m2; Volume: 0.180568 m3
Phase de construction - Phase de création: Projet

# IfcFurnishingElement: Bar, Plan de travail:Bar:1838181
In: 0 RDC
Type - Material: Par défaut
Type - Autre - Catégorie: Mobilier; Hauteur de plinthe: 10 cm; Nom de la famille: Plan de travail
Type - Construction - Extension de la plinthe 1: no; Extension de la plinthe 2: no; Réservation de l'évier: no
Type - Cotes - Hauteur: 115 cm
Type - Données d'identification - Nom du type: Bar
Type - Matériaux et finitions - Plan de travail: Bois - Mélaminé jaune pastel; Plinthe: Bois - Mélaminé jaune pastel
Pset_QuantityTakeOff - Reference: Plan de travail:Bar
Autre - ID hôte: Mur de base: Mur exterieur doublé; Décalage du bord 1: 100 cm; Décalage du bord 2: 10 cm; Décalage du mur 1: 5 cm; Décalage du mur 2: 5 cm; Famille: Plan de travail: Bar; Famille et type: Plan de travail: Bar; ID du type: Plan de travail: Bar; Type: Plan de travail: Bar
Contraintes - Niveau: Niveau: 0 RDC; Elévation: 110 cm; EP1: 3 cm; EP2: 3 cm; HS: 5 cm
Cotes - Longueur: 140 cm; Profondeur: 50 cm; Surface: 4.46405 m2; Volume: 0.202289 m3
Phase de construction - Phase de création: Projet

# IfcFurnishingElement: P-600 mm, Plan de travail - Emplacement rond pour lavabo:P-600 mm:517417
In: 0 RDC
Type - Material: Bois - Mélaminé bleu
Type - Autre - Catégorie: Meubles de rangement; Nom de la famille: Plan de travail - Emplacement rond pour lavabo
Type - Cotes - Epaisseur du plan de travail: 4 cm; Hauteur: 75 cm; Profondeur: 62.5 cm
Type - Données d'identification - Nom du type: P-600 mm
Type - Matériaux et finitions - Plan de travail: Bois - Mélaminé bleu
Pset_QuantityTakeOff - Reference: Plan de travail - Emplacement rond pour lavabo:P-600 mm
Autre - Famille: Plan de travail - Emplacement rond pour lavabo: P-600 mm; Famille et type: Plan de travail - Emplacement rond pour lavabo: P-600 mm; ID du type: Plan de travail - Emplacement rond pour lavabo: P-600 mm; Type: Plan de travail - Emplacement rond pour lavabo: P-600 mm
Contraintes - Niveau: Niveau: 0 RDC; Décalage: 0 cm; Hôte: Niveau : 0 RDC; Se déplace avec les éléments voisins: no
Cotes - Emplacement de l'évier: 190.577 cm; Emplacement de l'évier par rapport au mur: 10 cm; Largeur de l'ouverture de l'évier: 43.2 cm; Longueur: 173 cm; Surface: 1.35315 m2; Volume: 0.0465984 m3
Phase de construction - Phase de création: Projet

# IfcFurnishingElement: Rangement bar, Plan de travail bas:Rangement bar:1838207
In: 0 RDC
Type - Material: Par défaut
Type - Autre - Catégorie: Mobilier; Hauteur de plinthe: 10 cm; Nom de la famille: Plan de travail bas
Type - Construction - Extension de la plinthe 1: yes; Extension de la plinthe 2: yes; Réservation de l'évier: yes
Type - Cotes - Hauteur: 87.2 cm
Type - Données d'identification - Nom du type: Rangement bar
Type - Matériaux et finitions - Plan de travail: Bois - Mélaminé jaune pastel; Plinthe: Bois - Mélaminé jaune pastel
Pset_QuantityTakeOff - Reference: Plan de travail bas:Rangement bar
Autre - ID hôte: Mur de base: Mur exterieur doublé; Décalage du bord 1: 100 cm; Décalage du bord 2: 10 cm; Décalage du mur 1: 5 cm; Décalage du mur 2: 5 cm; Famille: Plan de travail bas: Rangement bar; Famille et type: Plan de travail bas: Rangement bar; ID du type: Plan de travail bas: Rangement bar; Type: Plan de travail bas: Rangement bar
Contraintes - Niveau: Niveau: 0 RDC; Elévation: 85 cm; EP1: 0 cm; EP2: 0 cm; HS: -5 cm
Cotes - Longueur: 140 cm; Profondeur: 50 cm; Surface: 4.34379 m2; Volume: 0.196904 m3
Phase de construction - Phase de création: Projet

# IfcFurnishingElement: Sans réservation pour évier (2)
In: 0 RDC
Type - Material: Acajou
Type - Autre - Catégorie: Mobilier; Hauteur de plinthe: 10 cm; Nom de la famille: Tablette sanitaires
Type - Construction - Extension de la plinthe 1: no; Extension de la plinthe 2: no; Réservation de l'évier: no
Type - Cotes - Hauteur: 115 cm
Type - Données d'identification - Nom du type: Sans réservation pour évier
Type - Matériaux et finitions - Plan de travail: Acajou; Plinthe: Acajou
Pset_QuantityTakeOff - Reference: Tablette sanitaires:Sans réservation pour évier
Autre - ID hôte: Mur de base: Cloison de distribution 72/48 à ossature métal avec laine minérale; Décalage du bord 1: 100 cm; Décalage du bord 2: 10 cm; Décalage du mur 1: 5 cm; Décalage du mur 2: 5 cm; Famille: Tablette sanitaires: Sans réservation pour évier; Famille et type: Tablette sanitaires: Sans réservation pour évier; ID du type: Tablette sanitaires: Sans réservation pour évier; Type: Tablette sanitaires: Sans réservation pour évier
Contraintes - Niveau: Niveau: 0 RDC; Elévation: 100 cm; EP1: 3 cm; EP2: 3 cm; HS: 5 cm
Cotes - Longueur: 111.68 cm; Profondeur: 50 cm; Surface: 0.310748 m2; Volume: 0.0068912 m3
Phase de construction - Phase de création: Projet
Name (Tablette sanitaires:Sans réservation pour évier:...)
1841610
1845828

# IfcGroup: Groupe de modèles:Barre appui, Groupe de modèles:Barre appui:2066244
Autre - Catégorie: Groupes de modèles; Famille: Groupe de modèles: Barre appui; Famille et type: Groupe de modèles: Barre appui; ID du type: Groupe de modèles: Barre appui; Type: Groupe de modèles: Barre appui
Contraintes - Décalage du niveau de l'origine: 0 cm; Niveau de référence: Niveau: 0 RDC
Autre(Type) - Catégorie: Groupes de modèles; Nom de la famille: Groupe de modèles
Données d'identification(Type) - Nom du type: Barre appui

# IfcOpeningElement: Opening (14)
Pset_QuantityTakeOff - sets with these values: 2
Name (Mur de base:...) | In | Depth (cm) | Height (cm) | Width (cm) | Catégorie | Famille = Famille et type = ID du type = Type | Hauteur sous linteau (cm) | ID hôte | Hauteur de l'appui (cm) | Niveau | Surface (m2) | Volume (m3) | Identifiant | Phase de création | Reference
Lg1:922663 | -1 Soubassement | 304.8 | 400 | 220 | Portes | Ensemble Alu vitré: Menuiserie 6 | 220 | Mur de base: Mur exterieur doublé | 0 | Niveau: 0 RDC | 16.6796 | 0.406165 | 172 | Projet | Mur de base:Lg1 | Cotes - Ext Wall Offset: 2 cm
Sbt1:924087 | -1 Soubassement | 304.8 | 100 | 207.5 | Portes | Int. Simple: PP (0.93m x 2.04m) | 204 | Mur de base: Int. Voile BA 20 doublé | 0 | Niveau: 0 RDC | 3.57997 | 0.124072 | 126 | Projet | Mur de base:Sbt1 | Données d'identification - Commentaires: CF1/2h + FP; Graphismes - Angle d'ouverture 2D fixe: yes; Angle d'ouverture 3D: 0 deg
Sbt1:924087 | -1 Soubassement | 35.4 | 220 | 93 | Portes | Porte Ext vitrée: Menuiserie 3 | 220 | Mur de base: Mur exterieur doublé | 0 | Niveau: 0 RDC | 3.43277 | 0.0724895 | 243 | Projet | Mur de base:Sbt1 | Autre - Handle Height Control: 105 cm; Inset Control: 5 cm; Wall Width: 35.4 cm; Cotes - Handle Height: 105 cm; Inset: 5 cm; Données - Fire Resistance Options Text: no
Sbt1:927328 | -1 Soubassement | 304.8 | 330 | 220 | Portes | Ensemble Alu vitré: Menuiserie 7 | 220 | Mur de base: Mur exterieur doublé | 0 | Niveau: 0 RDC | 14.4097 | 0.345114 | 171 | Projet | Mur de base:Sbt1 | Cotes - Ext Wall Offset: 2 cm
Lg1:930646 | -1 Soubassement | 304.8 | 330 | 220 | Portes | Ensemble Alu vitré: Menuiserie 7 | 220 | Mur de base: Mur exterieur doublé | 0 | Niveau: 0 RDC | 14.4097 | 0.345114 | 171 | Projet | Mur de base:Lg1 | Cotes - Ext Wall Offset: 2 cm
Lg1:930646 | -1 Soubassement | 35.4 | 400 | 220 | Portes | Ensemble Alu vitré: Menuiserie 6 | 220 | Mur de base: Mur exterieur doublé | 0 | Niveau: 0 RDC | 16.6796 | 0.406165 | 172 | Projet | Mur de base:Lg1 | Cotes - Ext Wall Offset: 2 cm
Sbt1:1230850 | -1 Soubassement | 304.8 | 220 | 93 | Portes | Porte Ext vitrée: Menuiserie 3 | 220 | Mur de base: Mur exterieur doublé | 0 | Niveau: 0 RDC | 3.43277 | 0.0724895 | 160 | Projet | Mur de base:Sbt1 | Autre - Handle Height Control: 105 cm; Inset Control: 5 cm; Wall Width: 35.4 cm; Cotes - Handle Height: 105 cm; Inset: 5 cm; Données - Fire Resistance Options Text: no
Sbt1:1230850 | -1 Soubassement | 35.4 | 220 | 93 | Portes | Porte Ext vitrée: Menuiserie 3 | 220 | Mur de base: Mur exterieur doublé | 0 | Niveau: 0 RDC | 3.43277 | 0.0724895 | 243 | Projet | Mur de base:Sbt1 | Autre - Handle Height Control: 105 cm; Inset Control: 5 cm; Wall Width: 35.4 cm; Cotes - Handle Height: 105 cm; Inset: 5 cm; Données - Fire Resistance Options Text: no
Sbt1:1230850 | -1 Soubassement | 304.8 | 370 | 220 | Portes | Ensemble Alu vitré: Menuiserie 2 | 220 | Mur de base: Mur exterieur doublé | 0 | Niveau: 0 RDC | 15.7068 | 0.38 | 167 | Projet | Mur de base:Sbt1 | Cotes - Ext Wall Offset: 2 cm
Sbt1:1230850 | -1 Soubassement | 100 | 207.5 | 27.1 | Portes | Int. Simple: PP (0.93m x 2.04m) | 204 | Mur de base: Int. Voile BA 20 doublé | 0 | Niveau: 0 RDC | 3.57997 | 0.124072 | 126 | Projet | Mur de base:Sbt1 | Données d'identification - Commentaires: CF1/2h + FP; Graphismes - Angle d'ouverture 2D fixe: yes; Angle d'ouverture 3D: 0 deg
Mur pierre 10 cm:1879198 | 0 RDC | 304.8 | 330 | 220 | Portes | Ensemble Alu vitré: Menuiserie 7 | 220 | Mur de base: Mur exterieur doublé | 0 | Niveau: 0 RDC | 14.4097 | 0.345114 | 171 | Projet | Mur de base:Mur pierre 10 cm | Cotes - Ext Wall Offset: 2 cm
Mur pierre 10 cm:1879198 | 0 RDC | 35.4 | 400 | 220 | Portes | Ensemble Alu vitré: Menuiserie 6 | 220 | Mur de base: Mur exterieur doublé | 0 | Niveau: 0 RDC | 16.6796 | 0.406165 | 172 | Projet | Mur de base:Mur pierre 10 cm | Cotes - Ext Wall Offset: 2 cm
Mur pierre 10 cm:511022 | 0 RDC |  | 222 | 330 | <Esquisse> |  |  |  |  |  |  |  |  |  | Mur de base:Mur pierre 10 cm | Cotes - Longueur: 222 cm
Lg1:2079338 | -1 Soubassement | 304.8 | 220 | 93 | Portes | Porte Ext vitrée: Menuiserie 3 | 220 | Mur de base: Mur exterieur doublé | 0 | Niveau: 0 RDC | 3.43277 | 0.0724895 | 243 | Projet | Mur de base:Lg1 | Autre - Handle Height Control: 105 cm; Inset Control: 5 cm; Wall Width: 35.4 cm; Cotes - Handle Height: 105 cm; Inset: 5 cm; Données - Fire Resistance Options Text: no

# IfcRailing: Garde-corps:3 lisses + panneau de verre, Garde-corps:3 lisses + panneau de verre:674252
In: 0 RDC
Material: Acier inox poli, Chêne clair, Verre
Pset_QuantityTakeOff - Reference: Garde-corps:3 lisses + panneau de verre
Pset_RailingCommon - IsExternal: no; Reference: Garde-corps:3 lisses + panneau de verre; Height: 121.92 cm
BaseQuantities - Length: 157.559 cm
Autre - Catégorie: Garde-corps; Famille: Garde-corps: 3 lisses + panneau de verre; Famille et type: Garde-corps: 3 lisses + panneau de verre; ID du type: Garde-corps: 3 lisses + panneau de verre; Type: Garde-corps: 3 lisses + panneau de verre
Contraintes - Décalage inférieur: 0 cm; Décalage à partir de la trajectoire: 2.54 cm
Cotes - Longueur: 157.559 cm
Phase de construction - Phase de création: Projet
Autre(Type) - Catégorie: Garde-corps; Nom de la famille: Garde-corps
Construction(Type) - Connexion des traverses: Ajuster; Décalage des barreaux: -3 cm; Hauteur du garde-corps: 101 cm; Joints d'angle: Ajouter des segments verticaux/horizontaux; Joints tangents: Prolonger la traverse jusqu'à; Réglage de la hauteur du palier: 0 cm; Utiliser le réglage de la hauteur du palier: no
Données d'identification(Type) - Nom du type: 3 lisses + panneau de verre

# IfcRailing: Garde-corps:Fixé au mur, Garde-corps:Fixé au mur:674256
In: 0 RDC
Material: Peinture - Noir, Chêne clair
Pset_QuantityTakeOff - Reference: Garde-corps:Fixé au mur
Pset_RailingCommon - IsExternal: no; Reference: Garde-corps:Fixé au mur; Height: 121.92 cm
BaseQuantities - Length: 197.859 cm
Autre - Catégorie: Garde-corps; Famille: Garde-corps: Fixé au mur; Famille et type: Garde-corps: Fixé au mur; ID du type: Garde-corps: Fixé au mur; Type: Garde-corps: Fixé au mur
Contraintes - Décalage inférieur: 0 cm; Décalage à partir de la trajectoire: 2.54 cm
Cotes - Longueur: 197.859 cm
Phase de construction - Phase de création: Projet
Autre(Type) - Catégorie: Garde-corps; Nom de la famille: Garde-corps
Construction(Type) - Joints d'angle: Ajouter des segments verticaux/horizontaux; Joints tangents: Prolonger la traverse jusqu'à; Réglage de la hauteur du palier: 0 cm; Utiliser le réglage de la hauteur du palier: no; Connexion des traverses: Soudure; Décalage des barreaux: 0 cm; Hauteur du garde-corps: 90 cm
Données d'identification(Type) - Nom du type: Fixé au mur

# IfcRoof: Toit de base:Couverture bac acier double peau, Toit de base:Couverture bac acier double peau:517272
In: 2 Toiture batiment
Pset_QuantityTakeOff - Reference: Toit de base:Couverture bac acier double peau
Pset_RoofCommon - Reference: Toit de base:Couverture bac acier double peau; IsExternal: yes; ProjectedArea: 376.591 m2; TotalArea: 379.293 m2
Autre - Catégorie: Toits; Famille: Toit de base: Couverture bac acier double peau; Famille et type: Toit de base: Couverture bac acier double peau; ID du type: Toit de base: Couverture bac acier double peau; Type: Toit de base: Couverture bac acier double peau
Construction - Coupe en chevron: Coupe verticale; Hauteur maximale de l'arrête: 87490.5 cm; Profondeur du bord de toiture: 0 cm
Contraintes - Lié au volume: no; Limite de pièce: yes; Décalage de la coupure: 0 cm; Décalage inférieur à partir du niveau: 0 cm; Niveau de base: Niveau: 2 Toiture batiment
Cotes - Epaisseur: 32 cm; Inclinaison: 0.12; Surface: 379.293 m2; Volume: 121.374 m3
Phase de construction - Phase de création: Projet
Autre(Type) - Catégorie: Toits; Nom de la famille: Toit de base
Construction(Type) - Epaisseur par défaut: 32 cm
Données d'identification(Type) - Nom du type: Couverture bac acier double peau
Graphismes(Type) - Motif vue détail faible: <Remplissage de solide>; Couleur vue détail faible: 12632256
Propriétés analytiques(Type) - Rugosité: 1; Coefficient d'absorbance: 0.1; Coefficient de transfert de chaleur (U): 0.161887; Masse thermique: 142860; Résistance thermique (R): 6.17714

# IfcRoof: Toit de base:Couverture bac acier simple peau, Toit de base:Couverture bac acier simple peau:517283
In: 1 Toiture auvent
Pset_QuantityTakeOff - Reference: Toit de base:Couverture bac acier simple peau
Pset_RoofCommon - IsExternal: yes; Reference: Toit de base:Couverture bac acier simple peau; ProjectedArea: 108.745 m2; TotalArea: 109.287 m2
Autre - Catégorie: Toits; Famille: Toit de base: Couverture bac acier simple peau; Famille et type: Toit de base: Couverture bac acier simple peau; ID du type: Toit de base: Couverture bac acier simple peau; Type: Toit de base: Couverture bac acier simple peau
Construction - Coupe en chevron: Coupe verticale; Profondeur du bord de toiture: 0 cm; Hauteur maximale de l'arrête: 87394.7 cm
Contraintes - Lié au volume: no; Limite de pièce: yes; Décalage de la coupure: 0 cm; Décalage inférieur à partir du niveau: 39.4 cm; Niveau de base: Niveau: 1 Toiture auvent
Cotes - Epaisseur: 2.9 cm; Inclinaison: 0.1; Surface: 109.287 m2; Volume: 3.16933 m3
Phase de construction - Phase de création: Projet
Autre(Type) - Catégorie: Toits; Nom de la famille: Toit de base
Construction(Type) - Epaisseur par défaut: 2.9 cm
Données d'identification(Type) - Nom du type: Couverture bac acier simple peau
Graphismes(Type) - Motif vue détail faible: <Remplissage de solide>; Couleur vue détail faible: 8947848
Propriétés analytiques(Type) - Rugosité: 1; Coefficient d'absorbance: 0.1

# IfcSlab: -M1- (11)
In: -1 Soubassement
Type - PredefinedType: FLOOR; Material: Béton - Béton coulé sur place
Type - Autre - Catégorie: Fondations; Nom de la famille: Base rectangulaire modifier
Type - Cotes - Epaisseur de fondation: 40 cm; Largeur: 80 cm; Longueur: 80 cm
Type - Données d'identification - Nom du type: -M1-
Type - Pset_QuantityTakeOff - Reference: Base rectangulaire modifier:-M1-
Type - Pset_ReinforcementBarPitchOfSlab - Reference: Base rectangulaire modifier:-M1-
Type - Pset_SlabCommon - IsExternal: no; Reference: Base rectangulaire modifier:-M1-
Pset_QuantityTakeOff - sets with these values: 2
Pset_SlabCommon - PitchAngle: 0 deg
BaseQuantities - GrossArea: 0.64 m2; NetArea: 2.56 m2; GrossVolume: 25.6 m3; NetVolume: 0.256 m3; Perimeter: 320 cm; Width: 40 cm
Autre - Famille: Base rectangulaire modifier: -M1-; Famille et type: Base rectangulaire modifier: -M1-; ID du type: Base rectangulaire modifier: -M1-; Type: Base rectangulaire modifier: -M1-
Contraintes - Se déplace avec les quadrillages: yes; Décalage par rapport au niveau: 0 cm; Hôte: Niveau : -1 Soubassement; Niveau: Niveau: -1 Soubassement
Cotes - Elévation à la base: 86910 cm; Elévation en haut: 86950 cm; Etude de l'élévation à la base: 86910 cm; Etude de l'élévation en haut: 86950 cm; Surface: 0.64 m2; Volume: 0.256 m3
Données d'identification - Commentaires: 80x80x40 +GB 20cm
Matériaux et finitions - Matériau structurel: Béton dallage
Phase de construction - Phase de création: Projet
Structure - Activer le modèle analytique: yes; Enrobage d'armature - Autres faces: Paramètres de l'enrobage d'armature: Enrobage d'armature 1; Enrobage d'armature - Face inférieure: Paramètres de l'enrobage d'armature: Enrobage d'armature 1; Enrobage d'armature - Face supérieure: Paramètres de l'enrobage d'armature: Enrobage d'armature 1
Name (Base rectangulaire modifier:-M1-:...)
897465
897968
898000
898011
898022
899270
899412
899421
903420
903999
904196

# IfcSlab: -M2- (3)
In: -1 Soubassement
Type - PredefinedType: FLOOR; Material: Béton - Béton coulé sur place
Type - Autre - Catégorie: Fondations; Nom de la famille: Base rectangulaire modifier
Type - Cotes - Epaisseur de fondation: 40 cm; Largeur: 100 cm; Longueur: 140 cm
Type - Données d'identification - Nom du type: -M2-
Type - Pset_QuantityTakeOff - Reference: Base rectangulaire modifier:-M2-
Type - Pset_ReinforcementBarPitchOfSlab - Reference: Base rectangulaire modifier:-M2-
Type - Pset_SlabCommon - IsExternal: no; Reference: Base rectangulaire modifier:-M2-
Pset_QuantityTakeOff - sets with these values: 2
Pset_SlabCommon - PitchAngle: 0 deg
BaseQuantities - GrossArea: 1.4 m2; NetArea: 4.72 m2; GrossVolume: 56 m3; NetVolume: 0.56 m3; Perimeter: 480 cm; Width: 40 cm
Autre - Famille: Base rectangulaire modifier: -M2-; Famille et type: Base rectangulaire modifier: -M2-; ID du type: Base rectangulaire modifier: -M2-; Type: Base rectangulaire modifier: -M2-
Contraintes - Se déplace avec les quadrillages: yes; Décalage par rapport au niveau: 0 cm; Niveau: Niveau: -1 Soubassement; Hôte: Niveau : -1 Soubassement
Cotes - Elévation à la base: 86910 cm; Elévation en haut: 86950 cm; Etude de l'élévation à la base: 86910 cm; Etude de l'élévation en haut: 86950 cm; Surface: 1.4 m2; Volume: 0.56 m3
Données d'identification - Commentaires: 140x100x40 +GB 20cm
Matériaux et finitions - Matériau structurel: Béton dallage
Phase de construction - Phase de création: Projet
Structure - Activer le modèle analytique: yes; Enrobage d'armature - Autres faces: Paramètres de l'enrobage d'armature: Enrobage d'armature 1; Enrobage d'armature - Face inférieure: Paramètres de l'enrobage d'armature: Enrobage d'armature 1; Enrobage d'armature - Face supérieure: Paramètres de l'enrobage d'armature: Enrobage d'armature 1
Name (Base rectangulaire modifier:-M2-:...)
904739
904904
905620

# IfcSlab: -M3- (4)
In: -1 Soubassement
Type - PredefinedType: FLOOR; Material: Béton - Béton coulé sur place
Type - Autre - Catégorie: Fondations; Nom de la famille: Base rectangulaire modifier
Type - Cotes - Epaisseur de fondation: 40 cm; Largeur: 90 cm; Longueur: 90 cm
Type - Données d'identification - Nom du type: -M3-
Type - Pset_QuantityTakeOff - Reference: Base rectangulaire modifier:-M3-
Type - Pset_ReinforcementBarPitchOfSlab - Reference: Base rectangulaire modifier:-M3-
Type - Pset_SlabCommon - IsExternal: no; Reference: Base rectangulaire modifier:-M3-
Pset_QuantityTakeOff - sets with these values: 2
Pset_SlabCommon - PitchAngle: 0 deg
BaseQuantities - GrossArea: 0.81 m2; NetArea: 3.06 m2; GrossVolume: 32.4 m3; NetVolume: 0.324 m3; Perimeter: 360 cm; Width: 40 cm
Autre - Famille: Base rectangulaire modifier: -M3-; Famille et type: Base rectangulaire modifier: -M3-; ID du type: Base rectangulaire modifier: -M3-; Type: Base rectangulaire modifier: -M3-
Contraintes - Se déplace avec les quadrillages: yes; Décalage par rapport au niveau: 0 cm; Niveau: Niveau: -1 Soubassement; Hôte: Niveau : -1 Soubassement
Cotes - Elévation à la base: 86910 cm; Elévation en haut: 86950 cm; Etude de l'élévation à la base: 86910 cm; Etude de l'élévation en haut: 86950 cm; Surface: 0.81 m2; Volume: 0.324 m3
Données d'identification - Commentaires: 90x90x40 +GB 20cm
Matériaux et finitions - Matériau structurel: Béton dallage
Phase de construction - Phase de création: Projet
Structure - Activer le modèle analytique: yes; Enrobage d'armature - Autres faces: Paramètres de l'enrobage d'armature: Enrobage d'armature 1; Enrobage d'armature - Face inférieure: Paramètres de l'enrobage d'armature: Enrobage d'armature 1; Enrobage d'armature - Face supérieure: Paramètres de l'enrobage d'armature: Enrobage d'armature 1
Name (Base rectangulaire modifier:-M3-:...)
905674
905768
905777
905788

# IfcSlab: Sol:Dallage Terrasse, Sol:Dallage Terrasse:517390
In: 0 RDC
Type - PredefinedType: FLOOR
Type - Autre - Catégorie: Sols; Nom de la famille: Sol
Type - Construction - Epaisseur par défaut: 18 cm; Fonction: Extérieur
Type - Données d'identification - Nom du type: Dallage Terrasse
Type - Graphismes - Motif vue détail faible: <Remplissage de solide>; Couleur vue détail faible: 8421504
Type - Matériaux et finitions - Matériau structurel: Béton dallage
Type - Propriétés analytiques - Rugosité: 1; Coefficient d'absorbance: 0.1; Coefficient de transfert de chaleur (U): 9.16667; Masse thermique: 271998; Résistance thermique (R): 0.109091
Type - Pset_QuantityTakeOff - Reference: Sol:Dallage Terrasse
Type - Pset_ReinforcementBarPitchOfSlab - Reference: Sol:Dallage Terrasse
Type - Pset_SlabCommon - IsExternal: no; Reference: Sol:Dallage Terrasse; ThermalTransmittance: 9.16667 kg/K/s3
Pset_QuantityTakeOff - sets with these values: 2
Pset_SlabCommon - LoadBearing: no; IsExternal: yes; PitchAngle: 0 deg
BaseQuantities - GrossArea: 179.96 m2; NetArea: 375.154 m2; NetVolume: 32.3928 m3; Perimeter: 8462.98 cm
Autre - Famille: Sol: Dallage Terrasse; Famille et type: Sol: Dallage Terrasse; ID du type: Sol: Dallage Terrasse; Type: Sol: Dallage Terrasse
Contraintes - Lié au volume: no; Limite de pièce: yes; Décalage par rapport au niveau: -2 cm; Niveau: Niveau: 0 RDC
Cotes - Elévation à la base: 86980 cm; Elévation en haut: 86998 cm; Epaisseur: 18 cm; Périmètre: 8462.98 cm; Surface: 179.96 m2; Volume: 32.3928 m3
Données d'identification - Commentaires: Dalle béton
Phase de construction - Phase de création: Projet
Structure - Activer le modèle analytique: no; Structure: no

# IfcSlab: Sol:Paillasson (2)
In: 0 RDC
Type - PredefinedType: FLOOR; Material: Tissu - Gris(1) 5 cm
Type - Autre - Catégorie: Sols; Nom de la famille: Sol
Type - Construction - Fonction: Intérieur; Epaisseur par défaut: 5 cm
Type - Données d'identification - Nom du type: Paillasson
Type - Graphismes - Motif vue détail faible: <Remplissage de solide>; Couleur vue détail faible: 8421504
Type - Matériaux et finitions - Matériau structurel: Tissu - Gris(1)
Type - Propriétés analytiques - Rugosité: 1; Coefficient d'absorbance: 0.1
Type - Pset_QuantityTakeOff - Reference: Sol:Paillasson
Type - Pset_ReinforcementBarPitchOfSlab - Reference: Sol:Paillasson
Type - Pset_SlabCommon - IsExternal: no; Reference: Sol:Paillasson
Pset_QuantityTakeOff - sets with these values: 2
Pset_SlabCommon - LoadBearing: no; PitchAngle: 0 deg
BaseQuantities - Width: 5 cm
Autre - Famille: Sol: Paillasson; Famille et type: Sol: Paillasson; ID du type: Sol: Paillasson; Type: Sol: Paillasson
Contraintes - Lié au volume: no; Limite de pièce: yes; Niveau: Niveau: 0 RDC; Décalage par rapport au niveau: 0 cm
Cotes - Elévation à la base: 86995 cm; Elévation en haut: 87000 cm; Epaisseur: 5 cm
Phase de construction - Phase de création: Projet
Structure - Activer le modèle analytique: no; Structure: no
Name (Sol:Paillasson:...) | GrossArea (m2) = Surface (m2) | NetArea (m2) | GrossVolume (m3) | NetVolume (m3) = Volume (m3) | Perimeter (cm) = Périmètre (cm)
655995 | 2.3368 | 5.0052 | 11.684 | 0.11684 | 663.2
656475 | 2.3 | 4.93 | 11.5 | 0.115 | 660

# IfcSlab: Sol:Plancher haut RDC étanche, Sol:Plancher haut RDC étanche:869742
In: 0 RDC
Type - PredefinedType: FLOOR; Material: Béton plancher 15 cm
Type - Autre - Catégorie: Sols; Nom de la famille: Sol
Type - Construction - Fonction: Intérieur; Epaisseur par défaut: 15 cm
Type - Données d'identification - Nom du type: Plancher haut RDC étanche
Type - Graphismes - Motif vue détail faible: <Remplissage de solide>; Couleur vue détail faible: 12632256
Type - Matériaux et finitions - Matériau structurel: Béton plancher
Type - Propriétés analytiques - Rugosité: 1; Coefficient d'absorbance: 0.1
Type - Pset_QuantityTakeOff - Reference: Sol:Plancher haut RDC étanche
Type - Pset_ReinforcementBarPitchOfSlab - Reference: Sol:Plancher haut RDC étanche
Type - Pset_SlabCommon - IsExternal: no; Reference: Sol:Plancher haut RDC étanche
Pset_QuantityTakeOff - sets with these values: 2
Pset_SlabCommon - LoadBearing: no; PitchAngle: 0 deg
BaseQuantities - GrossArea: 11.028 m2; NetArea: 24.6911 m2; GrossVolume: 165.42 m3; NetVolume: 1.6542 m3; Perimeter: 1756.77 cm; Width: 15 cm
Autre - Famille: Sol: Plancher haut RDC étanche; Famille et type: Sol: Plancher haut RDC étanche; ID du type: Sol: Plancher haut RDC étanche; Type: Sol: Plancher haut RDC étanche
Contraintes - Lié au volume: no; Limite de pièce: yes; Niveau: Niveau: 0 RDC; Décalage par rapport au niveau: 295.21 cm
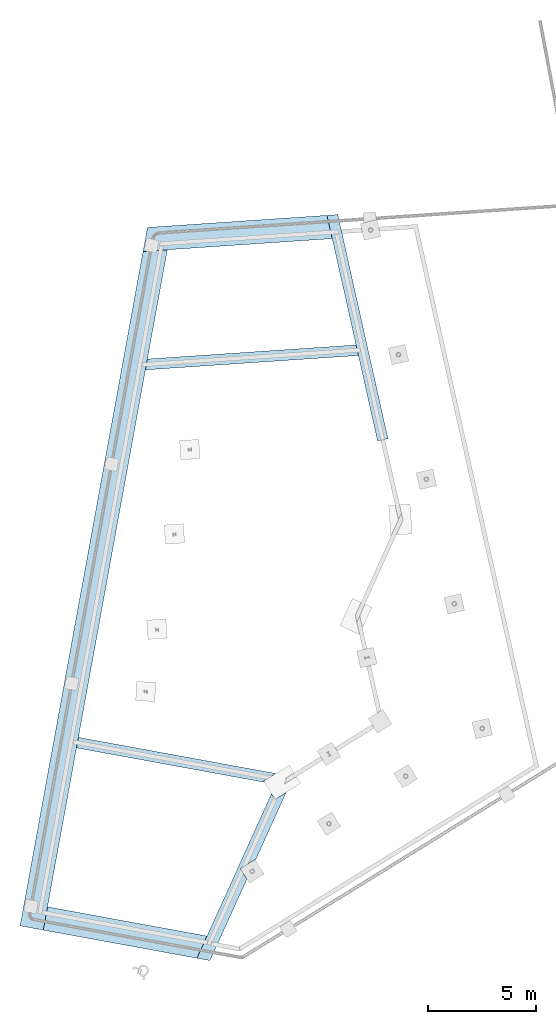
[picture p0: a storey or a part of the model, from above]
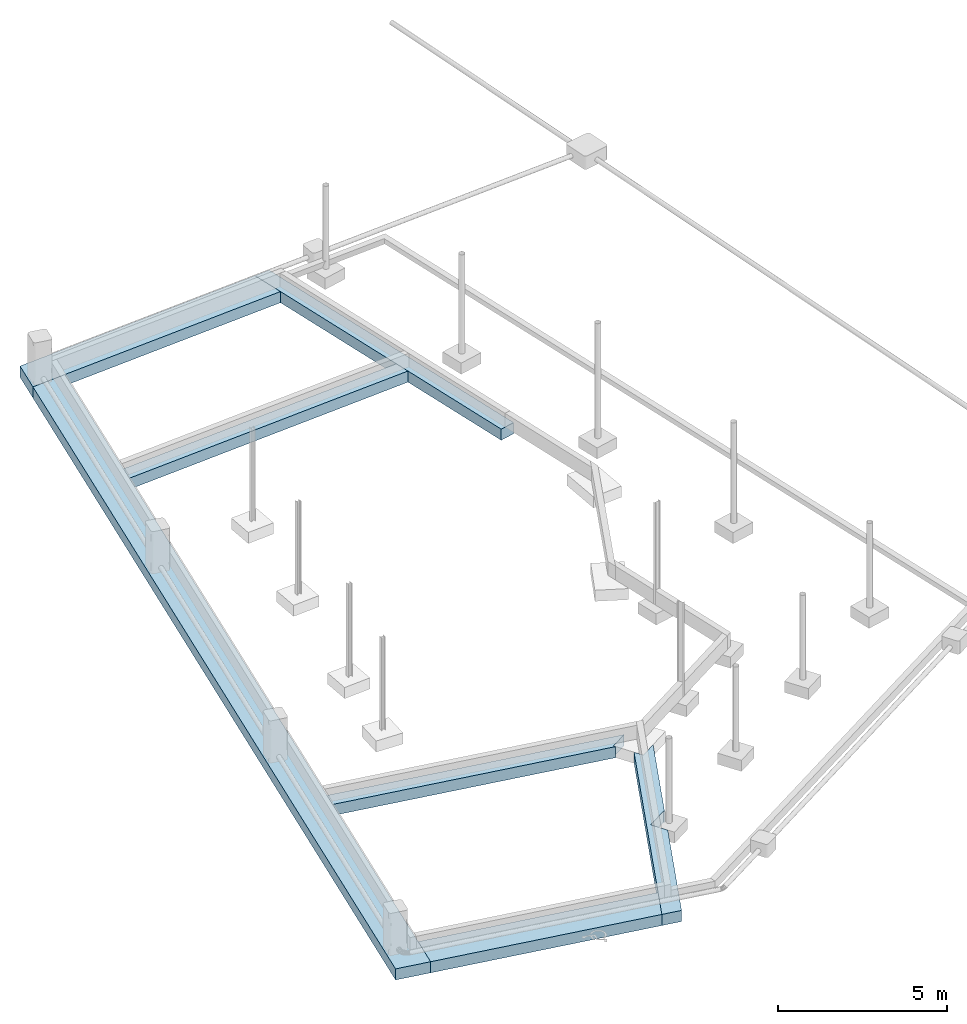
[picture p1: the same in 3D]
Properties of the parts of a building model (IFC2X3), part 4 of 5

# IfcSlab: Sol:Plancher haut RDC étanche, Sol:Plancher haut RDC étanche:869742
Cotes - Elévation à la base: 87280.2 cm; Elévation en haut: 87295.2 cm; Epaisseur: 15 cm; Périmètre: 1756.77 cm; Surface: 11.028 m2; Volume: 1.6542 m3
Phase de construction - Phase de création: Projet
Structure - Activer le modèle analytique: no; Structure: no

# IfcSlab: Sol:Scène, Sol:Scène:673181
In: 0 RDC
Type - PredefinedType: FLOOR; Material: Bois - Pin 5 cm
Type - Autre - Catégorie: Sols; Nom de la famille: Sol
Type - Construction - Fonction: Intérieur; Epaisseur par défaut: 5 cm
Type - Données d'identification - Nom du type: Scène
Type - Graphismes - Motif vue détail faible: <Remplissage de solide>; Couleur vue détail faible: 8421504
Type - Matériaux et finitions - Matériau structurel: Bois - Pin
Type - Propriétés analytiques - Rugosité: 1; Coefficient d'absorbance: 0.1
Type - Pset_QuantityTakeOff - Reference: Sol:Scène
Type - Pset_ReinforcementBarPitchOfSlab - Reference: Sol:Scène
Type - Pset_SlabCommon - IsExternal: no; Reference: Sol:Scène
Pset_QuantityTakeOff - sets with these values: 2
Pset_SlabCommon - LoadBearing: no; PitchAngle: 0 deg
BaseQuantities - GrossArea: 31.6172 m2; NetArea: 64.4327 m2; GrossVolume: 158.086 m3; NetVolume: 1.58086 m3; Perimeter: 2396.59 cm; Width: 5 cm
Autre - Famille: Sol: Scène; Famille et type: Sol: Scène; ID du type: Sol: Scène; Type: Sol: Scène
Contraintes - Lié au volume: no; Limite de pièce: yes; Niveau: Niveau: 0 RDC; Décalage par rapport au niveau: 75 cm
Cotes - Elévation à la base: 87070 cm; Elévation en haut: 87075 cm; Epaisseur: 5 cm; Périmètre: 2396.59 cm; Surface: 31.6172 m2; Volume: 1.58086 m3
Phase de construction - Phase de création: Projet
Structure - Activer le modèle analytique: no; Structure: no

# IfcSlab: Terre-plein:Dallage sur terre plein finition Carrelage 30x30 (3)
In: 0 RDC
Type - PredefinedType: FLOOR
Type - Autre - Catégorie: Terre-plein; Nom de la famille: Terre-plein
Type - Construction - Epaisseur: 50 cm
Type - Données d'identification - Nom du type: Dallage sur terre plein finition Carrelage 30x30
Type - Graphismes - Motif vue détail faible: <Remplissage de solide>; Couleur vue détail faible: 12632256
Type - Propriétés analytiques - Rugosité: 1; Coefficient d'absorbance: 0.1; Coefficient de transfert de chaleur (U): 0.399153; Masse thermique: 201037; Résistance thermique (R): 2.5053
Type - Pset_QuantityTakeOff - Reference: Terre-plein:Dallage sur terre plein finition Carrelage 30x30
Type - Pset_ReinforcementBarPitchOfSlab - Reference: Terre-plein:Dallage sur terre plein finition Carrelage 30x30
Type - Pset_SlabCommon - IsExternal: no; Reference: Terre-plein:Dallage sur terre plein finition Carrelage 30x30; ThermalTransmittance: 0.399153 kg/K/s3
Pset_QuantityTakeOff - sets with these values: 2
Autre - Famille: Terre-plein: Dallage sur terre plein finition Carrelage 30x30; Famille et type: Terre-plein: Dallage sur terre plein finition Carrelage 30x30; ID du type: Terre-plein: Dallage sur terre plein finition Carrelage 30x30; Type: Terre-plein: Dallage sur terre plein finition Carrelage 30x30
Contraintes - Limite de pièce: yes; Décalage par rapport au niveau: 0 cm; Niveau: Niveau: 0 RDC
Phase de construction - Phase de création: Projet
Name (Terre-plein:Dallage sur terre plein finition Carrelage 30x30:...) | NetArea (m2) | NetVolume (m3) = Volume (m3) | Périmètre (cm) | Surface (m2)
1888354 | 84.3152 | 17.7809 | 2638.32 | 35.5618
2588470 | 13.4384 | 2.27589 | 866.956 | 4.55179
2717765 | 28.4924 | 5.45962 | 1330.79 | 10.9192

# IfcSlab: Terre-plein:Dallage sur terre plein finition carrelage 45x45 (2)
In: 0 RDC
Type - PredefinedType: FLOOR
Type - Autre - Catégorie: Terre-plein; Nom de la famille: Terre-plein
Type - Construction - Epaisseur: 50 cm
Type - Données d'identification - Nom du type: Dallage sur terre plein finition carrelage 45x45
Type - Graphismes - Motif vue détail faible: <Remplissage de solide>; Couleur vue détail faible: 12632256
Type - Propriétés analytiques - Rugosité: 1; Coefficient d'absorbance: 0.1; Coefficient de transfert de chaleur (U): 0.398888; Masse thermique: 201037; Résistance thermique (R): 2.50697
Type - Pset_QuantityTakeOff - Reference: Terre-plein:Dallage sur terre plein finition carrelage 45x45
Type - Pset_ReinforcementBarPitchOfSlab - Reference: Terre-plein:Dallage sur terre plein finition carrelage 45x45
Type - Pset_SlabCommon - IsExternal: no; Reference: Terre-plein:Dallage sur terre plein finition carrelage 45x45; ThermalTransmittance: 0.398888 kg/K/s3
Pset_QuantityTakeOff - sets with these values: 2
Autre - Famille: Terre-plein: Dallage sur terre plein finition carrelage 45x45; Famille et type: Terre-plein: Dallage sur terre plein finition carrelage 45x45; ID du type: Terre-plein: Dallage sur terre plein finition carrelage 45x45; Type: Terre-plein: Dallage sur terre plein finition carrelage 45x45
Contraintes - Limite de pièce: yes; Niveau: Niveau: 0 RDC; Décalage par rapport au niveau: 0 cm
Phase de construction - Phase de création: Projet
Name (Terre-plein:Dallage sur terre plein finition carrelage 45x45:...) | NetArea (m2) | NetVolume (m3) = Volume (m3) | Périmètre (cm) | Surface (m2)
1035782 | 77.6109 | 16.3535 | 2439.41 | 32.7069
1908285 | 79.6072 | 16.7954 | 2485.16 | 33.5907

# IfcSlab: Terre-plein:Dallage sur terre plein finition quartz (2)
In: 0 RDC
Type - PredefinedType: FLOOR
Type - Autre - Catégorie: Terre-plein; Nom de la famille: Terre-plein
Type - Construction - Epaisseur: 50 cm
Type - Données d'identification - Nom du type: Dallage sur terre plein finition quartz
Type - Graphismes - Motif vue détail faible: <Remplissage de solide>; Couleur vue détail faible: 12632256
Type - Propriétés analytiques - Rugosité: 1; Coefficient d'absorbance: 0.1; Coefficient de transfert de chaleur (U): 0.398958; Masse thermique: 199148; Résistance thermique (R): 2.50653
Type - Pset_QuantityTakeOff - Reference: Terre-plein:Dallage sur terre plein finition quartz
Type - Pset_ReinforcementBarPitchOfSlab - Reference: Terre-plein:Dallage sur terre plein finition quartz
Type - Pset_SlabCommon - IsExternal: no; Reference: Terre-plein:Dallage sur terre plein finition quartz; ThermalTransmittance: 0.398958 kg/K/s3
Pset_QuantityTakeOff - sets with these values: 2
Autre - Famille: Terre-plein: Dallage sur terre plein finition quartz; Famille et type: Terre-plein: Dallage sur terre plein finition quartz; ID du type: Terre-plein: Dallage sur terre plein finition quartz; Type: Terre-plein: Dallage sur terre plein finition quartz
Contraintes - Limite de pièce: yes; Niveau: Niveau: 0 RDC; Décalage par rapport au niveau: 0 cm
Phase de construction - Phase de création: Projet
Name (Terre-plein:Dallage sur terre plein finition quartz:...) | NetArea (m2) | NetVolume (m3) = Volume (m3) | Périmètre (cm) | Surface (m2)
1823911 | 468.45 | 109.521 | 6073.53 | 219.041
2717444 | 29.5564 | 5.51586 | 1498.6 | 11.0317

# IfcSlab: Terre-plein:Hérisson terrasse, Terre-plein:Hérisson terrasse:1040622
In: 0 RDC
Type - PredefinedType: FLOOR; Material: Sable 5 cm, Gravier 25 cm
Type - Autre - Catégorie: Terre-plein; Nom de la famille: Terre-plein
Type - Construction - Epaisseur: 30 cm
Type - Données d'identification - Nom du type: Hérisson terrasse
Type - Graphismes - Motif vue détail faible: <Remplissage de solide>; Couleur vue détail faible: 12632256
Type - Propriétés analytiques - Rugosité: 1; Coefficient d'absorbance: 0.1
Type - Pset_QuantityTakeOff - Reference: Terre-plein:Hérisson terrasse
Type - Pset_ReinforcementBarPitchOfSlab - Reference: Terre-plein:Hérisson terrasse
Type - Pset_SlabCommon - IsExternal: no; Reference: Terre-plein:Hérisson terrasse
Pset_QuantityTakeOff - sets with these values: 2
BaseQuantities - NetArea: 366.678 m2; NetVolume: 51.25 m3
Autre - Famille: Terre-plein: Hérisson terrasse; Famille et type: Terre-plein: Hérisson terrasse; ID du type: Terre-plein: Hérisson terrasse; Type: Terre-plein: Hérisson terrasse
Contraintes - Limite de pièce: yes; Niveau: Niveau: 0 RDC; Décalage par rapport au niveau: -20 cm
Cotes - Périmètre: 8337.3 cm; Surface: 170.833 m2; Volume: 51.25 m3
Phase de construction - Phase de création: Projet

# IfcSlab: Toit de base:Couverture bac acier simple peau (2)
In: 1 Toiture auvent
PredefinedType: ROOF; Material: Bac acier auvent 2.9 cm
Pset_QuantityTakeOff - Reference: Toit de base:Couverture bac acier simple peau; sets with these values: 2
Pset_SlabCommon - IsExternal: yes; Reference: Toit de base:Couverture bac acier simple peau; PitchAngle: 5.71059 deg
BaseQuantities - NetArea: 220.75 m2; NetVolume: 3.16933 m3; Width: 2.9 cm
Name (Toit de base:Couverture bac acier simple peau:...) | GrossArea (m2) | GrossVolume (m3) | Perimeter (cm)
517283 | 8.36381 | 24.255 | 4989.33
517283 | 1.78931 | 5.18899 | 2792.51

# IfcStair: Escalier coulé sur place:Béton - Pailasse, Escalier coulé sur place:Escalier:673989
In: 0 RDC
Pset_QuantityTakeOff - Reference: Escalier coulé sur place:Escalier
Pset_StairCommon - IsExternal: no; Reference: Escalier coulé sur place:Escalier; NumberOfRiser: 5; NumberOfTreads: 5; RiserHeight: 15 cm; TreadLength: 33 cm
Autre - Catégorie: Escalier; Famille: Escalier coulé sur place: Béton - Pailasse; Famille et type: Escalier coulé sur place: Béton - Pailasse; ID du type: Escalier coulé sur place: Béton - Pailasse; Type: Escalier coulé sur place: Béton - Pailasse
Contraintes - Décalage inférieur: 0 cm; Décalage supérieur: 90 cm; Hauteur d'escalier souhaitée: 90 cm; Niveau de base: Niveau: 0 RDC; Niveau supérieur: Niveau: 0 RDC
Cotes - Hauteur actuelle de la contremarche: 15 cm; Nombre de contremarches souhaité: 6; Nombre réel de contremarches: 5; Numéro initial de marche/contremarche: 1; Profondeur actuelle du giron: 33 cm
Phase de construction - Phase de création: Projet
Structure - Enrobage d'armature: Paramètres de l'enrobage d'armature: Enrobage d'armature 1
Autre(Type) - Catégorie: Escalier; Nom de la famille: Escalier coulé sur place
Construction(Type) - Fonction: Intérieur; Type de palier: Palier monobloc: Epaisseur 150 mm; Type de volée: Volée monobloc: Giron 10 mm Nez de marche 5 mm Contremarche 10 mm
Données d'identification(Type) - Nom du type: Béton - Pailasse
Graphismes(Type) - Type de symbole de coupe: Symbole de coupure d'escalier: Zig-zag simple
Règles de calcul(Type) - Hauteur maximum de la contremarche: 16 cm; Largeur de volée minimale: 100 cm; Profondeur de marche minimale: 28 cm
Supports(Type) - Décalage latéral droit: 0 cm; Décalage latéral gauche: 0 cm; Nombre de supports intermédiaires: 0; Support droit: Aucun; Support gauche: Aucun; Support intermédiaire: no

# IfcStairFlight: Volée monobloc:Giron 10 mm Nez de marche 5 mm Contremarche 10 mm, Escalier coulé sur place:Escalier:673989 Run 1
In: 0 RDC
NumberOfRiser: 5; NumberOfTreads: 5; RiserHeight: 0.492126 cm; TreadLength: 1.08268 cm; Material: Béton fintion balayée
Pset_QuantityTakeOff - Reference: Volée monobloc:Giron 10 mm Nez de marche 5 mm Contremarche 10 mm
Pset_StairFlightCommon - Reference: Volée monobloc:Giron 10 mm Nez de marche 5 mm Contremarche 10 mm; NumberOfRiser: 5; NumberOfTreads: 5; RiserHeight: 15 cm; TreadLength: 33 cm; NosingLength: 0.5 cm; TreadLengthAtOffset: 33 cm
Autre - Catégorie: Volées; Famille: Volée monobloc: Giron 10 mm Nez de marche 5 mm Contremarche 10 mm; Famille et type: Volée monobloc: Giron 10 mm Nez de marche 5 mm Contremarche 10 mm; ID du type: Volée monobloc: Giron 10 mm Nez de marche 5 mm Contremarche 10 mm; Type: Volée monobloc: Giron 10 mm Nez de marche 5 mm Contremarche 10 mm
Construction - Débuter avec contremarche: yes; Etendre la base de contremarche inférieure: 0 cm; Finir avec contremarche: no
Contraintes - Hauteur de base relative: 0 cm; Hauteur de la volée: 75 cm; Hauteur maximale relative: 75 cm
Cotes - Nombre réel de contremarches: 5; Hauteur réelle des contremarches: 15 cm; Nombre réel de marches: 5
Phase de construction - Phase de création: Projet
Autre(Type) - Catégorie: Volées; Nom de la famille: Volée monobloc
Construction(Type) - Paillasse: Lissée; Profondeur structurelle: 8 cm
Contremarches(Type) - Connexion contremarche à marche: Marche dessous la contremarche; Contremarche: yes; Epaisseur de la contremarche: 1 cm; Inclinée: no
Données d'identification(Type) - Nom du type: Giron 10 mm Nez de marche 5 mm Contremarche 10 mm
Marches(Type) - Appliquer un nez de marche: Devant seulement; Epaisseur de la marche: 1 cm; Longueur du nez de marche: 0.5 cm; Marche: yes
Matériaux et finitions(Type) - Matériau de la contremarche: Béton fintion balayée; Matériau de la marche: Béton fintion balayée; Matériau monobloc: Béton fintion balayée

# IfcSystem: Eau Pluviales (5)
Autre - Catégorie: Système de canalisation; Famille: Système de canalisation: Eau Pluviales; Famille et type: Système de canalisation: Eau Pluviales; ID du type: Système de canalisation: Eau Pluviales; Type: Système de canalisation: Eau Pluviales
Génie climatique - Débit par appareil: 0; Nombre d'éléments: 0
Name | Nom du système | Volume (m3)
EP 5 | EP 5 | 0.714439
EP 3 | EP 3 | 0.208223
EP 2 | EP 2 | 0.395031
EP 6 | EP 6 | 0.669948
EP 1 | EP 1 | 0.383052

# IfcWall: Mur de base:Cloison de distribution 72/48 à ossature métal avec laine minérale (6)
In: 0 RDC
Type - PredefinedType: STANDARD
Type - Autre - Catégorie: Murs; Nom de la famille: Mur de base
Type - Construction - Fonction: Intérieur; Retournement aux extrémités: Aucun(e); Retournement aux insertions: Ne pas retourner; Largeur: 7.2 cm
Type - Données d'identification - Nom du type: Cloison de distribution 72/48 à ossature métal avec laine minérale
Type - Graphismes - Motif vue détail faible: <Remplissage de solide>; Couleur vue détail faible: 12632256
Type - Propriétés analytiques - Rugosité: 1; Coefficient d'absorbance: 0.1; Coefficient de transfert de chaleur (U): 1.03333; Masse thermique: 4260; Résistance thermique (R): 0.967742
Type - Pset_QuantityTakeOff - Reference: Mur de base:Cloison de distribution 72/48 à ossature métal avec laine minérale
Type - Pset_ReinforcementBarPitchOfWall - Reference: Mur de base:Cloison de distribution 72/48 à ossature métal avec laine minérale
Type - Pset_WallCommon - IsExternal: no; Reference: Mur de base:Cloison de distribution 72/48 à ossature métal avec laine minérale; ThermalTransmittance: 1.03333 kg/K/s3
Autre - Famille: Mur de base: Cloison de distribution 72/48 à ossature métal avec laine minérale; Famille et type: Mur de base: Cloison de distribution 72/48 à ossature métal avec laine minérale; ID du type: Mur de base: Cloison de distribution 72/48 à ossature métal avec laine minérale; Type: Mur de base: Cloison de distribution 72/48 à ossature métal avec laine minérale
Contraintes - Contrainte inférieure: Niveau: 0 RDC; Décalage inférieur: 0 cm; Extension inférieure: 0 cm; Extension supérieure: 0 cm; Lié au volume: no; Partie inférieure attachée: no; Hauteur non contrainte: 300 cm
Phase de construction - Phase de création: Projet
Structure - Activer le modèle analytique: no; Structure: no; Utilisation structurelle: Non porteur
Pset_QuantityTakeOff - sets with these values: 2
Pset_WallCommon - LoadBearing: no
Name (Mur de base:Cloison de distribution 72/48 à ossature métal avec laine minérale:...) | Partie supérieure attachée = ExtendToStructure | Ligne de justification | Décalage supérieur (cm) | Limite de pièce | Longueur (cm) | Surface (m2) | Volume (m3)
557602 | yes | Nu fini: Extérieur | -50 | no | 293.448 | 6.43881 | 0.463588
563261 | no | Nu fini: Extérieur | -50 | yes | 118.569 | 3.02616 | 0.217877
574841 | no | Axe du mur | -50 | no | 377.936 | 7.56407 | 0.544613
574974 | no | Nu fini: Extérieur | -50 | no | 131.298 | 3.30002 | 0.237596
1491147 | no | Nu fini: Extérieur | -50 | no | 131.437 | 3.30419 | 0.237896
1839399 | no | Nu fini: Extérieur | 30.83 | no | 275.338 | 5.56411 | 0.400616

# IfcWall: Mur de base:Cloison de séparation 98/48 à ossature métal avec laine minérale (12)
In: 0 RDC
Type - PredefinedType: STANDARD
Type - Autre - Catégorie: Murs; Nom de la famille: Mur de base
Type - Construction - Fonction: Intérieur; Largeur: 9.8 cm; Retournement aux extrémités: Aucun(e); Retournement aux insertions: Ne pas retourner
Type - Données d'identification - Nom du type: Cloison de séparation 98/48 à ossature métal avec laine minérale
Type - Graphismes - Couleur vue détail faible: 12632256; Motif vue détail faible: <Remplissage de solide>
Type - Propriétés analytiques - Coefficient d'absorbance: 0.1; Rugosité: 1
Type - Pset_QuantityTakeOff - Reference: Mur de base:Cloison de séparation 98/48 à ossature métal avec laine minérale
Type - Pset_ReinforcementBarPitchOfWall - Reference: Mur de base:Cloison de séparation 98/48 à ossature métal avec laine minérale
Type - Pset_WallCommon - Reference: Mur de base:Cloison de séparation 98/48 à ossature métal avec laine minérale; IsExternal: no
Autre - Famille: Mur de base: Cloison de séparation 98/48 à ossature métal avec laine minérale; Famille et type: Mur de base: Cloison de séparation 98/48 à ossature métal avec laine minérale; ID du type: Mur de base: Cloison de séparation 98/48 à ossature métal avec laine minérale; Type: Mur de base: Cloison de séparation 98/48 à ossature métal avec laine minérale
Contraintes - Contrainte inférieure: Niveau: 0 RDC; Décalage inférieur: 0 cm; Décalage supérieur: 0 cm; Extension inférieure: 0 cm; Extension supérieure: 0 cm; Hauteur non contrainte: 300 cm; Lié au volume: no; Limite de pièce: yes; Partie inférieure attachée: no
Phase de construction - Phase de création: Projet
Structure - Activer le modèle analytique: no; Structure: no; Utilisation structurelle: Non porteur
Pset_QuantityTakeOff - sets with these values: 2
Pset_WallCommon - LoadBearing: no
Name (Mur de base:Cloison de séparation 98/48 à ossature métal avec laine minérale:...) | Ligne de justification | Partie supérieure attachée = ExtendToStructure | Longueur (cm) | Surface (m2) | Volume (m3)
517269 | Axe du mur | yes | 120 | 1.90615 | 0.186112
517377 | Nu fini: Extérieur | yes | 709.158 | 23.141 | 2.26385
517448 | Axe du mur | yes | 293.528 | 8.51621 | 0.834578
517482 | Axe du mur | yes | 294.123 | 8.53396 | 0.836318
548504 | Nu fini: Extérieur | no | 891.419 | 24.93 | 2.34674
551414 | Nu fini: Extérieur | yes | 192.534 | 6.62333 | 0.648114
557456 | Nu fini: Extérieur | yes | 393.087 | 11.1174 | 1.08735
573663 | Nu fini: Extérieur | yes | 171.1 | 5.46181 | 0.535257
573842 | Axe du mur | yes | 1860.39 | 47.6309 | 4.65323
886935 | Nu fini: Extérieur | yes | 130.2 | 4.20253 | 0.411848
887032 | Nu fini: Extérieur | yes | 199.9 | 6.0098 | 0.587865
1618630 | Nu fini: Extérieur | yes | 545.334 | 16.5309 | 1.61716

# IfcWall: Mur de base:Int. Voile BA 20, Mur de base:Int. Voile BA 20:2597887
In: 0 RDC
Type - PredefinedType: STANDARD
Type - Autre - Catégorie: Murs; Nom de la famille: Mur de base
Type - Construction - Fonction: Intérieur; Retournement aux extrémités: Aucun(e); Retournement aux insertions: Intérieur; Largeur: 20 cm
Type - Données d'identification - Commentaires du type: Extérieur voile BA 20; Nom du type: Int. Voile BA 20
Type - Graphismes - Couleur vue détail faible: 0
Type - Matériaux et finitions - Matériau structurel: Béton banché mur
Type - Propriétés analytiques - Rugosité: 1; Coefficient d'absorbance: 0.1; Coefficient de transfert de chaleur (U): 8.25; Masse thermique: 302220; Résistance thermique (R): 0.121212
Type - Pset_QuantityTakeOff - Reference: Mur de base:Int. Voile BA 20
Type - Pset_ReinforcementBarPitchOfWall - Reference: Mur de base:Int. Voile BA 20
Type - Pset_WallCommon - IsExternal: no; Reference: Mur de base:Int. Voile BA 20; ThermalTransmittance: 8.25 kg/K/s3
Autre - Famille: Mur de base: Int. Voile BA 20; Famille et type: Mur de base: Int. Voile BA 20; ID du type: Mur de base: Int. Voile BA 20; Type: Mur de base: Int. Voile BA 20
Contraintes - Contrainte inférieure: Niveau: 0 RDC; Décalage supérieur: 0 cm; Extension inférieure: 0 cm; Extension supérieure: 0 cm; Lié au volume: no; Limite de pièce: yes; Partie inférieure attachée: no; Partie supérieure attachée: yes; Ligne de justification: Nu fini: Extérieur; Contrainte supérieure: Niveau: 2 Toiture batiment; Décalage inférieur: 255 cm; Hauteur non contrainte: 36 cm
Cotes - Longueur: 293.25 cm; Surface: 1.60628 m2; Volume: 0.32125 m3
Phase de construction - Phase de création: Projet
Structure - Activer le modèle analytique: no; Structure: no; Utilisation structurelle: Non porteur
Pset_QuantityTakeOff - sets with these values: 2
Pset_WallCommon - ExtendToStructure: yes; LoadBearing: no

# IfcWall: Mur de base:Int. Voile BA 20 doublé (2)
In: 0 RDC
Type - PredefinedType: STANDARD
Type - Autre - Catégorie: Murs; Nom de la famille: Mur de base
Type - Construction - Fonction: Intérieur; Retournement aux extrémités: Aucun(e); Largeur: 27.1 cm; Retournement aux insertions: Intérieur
Type - Données d'identification - Commentaires du type: Extérieur voile BA 20; Nom du type: Int. Voile BA 20 doublé
Type - Graphismes - Couleur vue détail faible: 0
Type - Matériaux et finitions - Matériau structurel: Béton banché mur
Type - Propriétés analytiques - Rugosité: 1; Coefficient d'absorbance: 0.1; Coefficient de transfert de chaleur (U): 4.44026; Masse thermique: 326244; Résistance thermique (R): 0.225212
Type - Pset_QuantityTakeOff - Reference: Mur de base:Int. Voile BA 20 doublé
Type - Pset_ReinforcementBarPitchOfWall - Reference: Mur de base:Int. Voile BA 20 doublé
Type - Pset_WallCommon - IsExternal: no; Reference: Mur de base:Int. Voile BA 20 doublé; ThermalTransmittance: 4.44026 kg/K/s3
Autre - Famille: Mur de base: Int. Voile BA 20 doublé; Famille et type: Mur de base: Int. Voile BA 20 doublé; ID du type: Mur de base: Int. Voile BA 20 doublé; Type: Mur de base: Int. Voile BA 20 doublé
Contraintes - Contrainte inférieure: Niveau: 0 RDC; Décalage inférieur: 0 cm; Décalage supérieur: 0 cm; Extension inférieure: 0 cm; Extension supérieure: 0 cm; Lié au volume: no; Limite de pièce: yes; Partie inférieure attachée: no; Partie supérieure attachée: yes; Ligne de justification: Nu fini: Extérieur; Hauteur non contrainte: 300 cm
Phase de construction - Phase de création: Projet
Structure - Activer le modèle analytique: no; Structure: no; Utilisation structurelle: Non porteur
Pset_QuantityTakeOff - sets with these values: 2
Pset_WallCommon - ExtendToStructure: yes; LoadBearing: no
Name (Mur de base:Int. Voile BA 20 doublé:...) | Longueur (cm) | Surface (m2) | Volume (m3)
1618633 | 710.908 | 23.7894 | 6.31752
1618670 | 1023.83 | 33.3338 | 8.97169

# IfcWall: Mur de base:Mur exterieur doublé (7)
In: 0 RDC
Type - PredefinedType: STANDARD
Type - Autre - Catégorie: Murs; Nom de la famille: Mur de base
Type - Construction - Retournement aux extrémités: Aucun(e); Fonction: Extérieur; Largeur: 35.4 cm; Retournement aux insertions: Extérieur
Type - Données d'identification - Nom du type: Mur exterieur doublé
Type - Graphismes - Motif vue détail faible: <Remplissage de solide>; Couleur vue détail faible: 12632256
Type - Matériaux et finitions - Matériau structurel: Béton banché mur
Type - Propriétés analytiques - Rugosité: 1; Coefficient d'absorbance: 0.1; Coefficient de transfert de chaleur (U): 0.296605; Masse thermique: 350094; Résistance thermique (R): 3.37149
Type - Pset_QuantityTakeOff - Reference: Mur de base:Mur exterieur doublé
Type - Pset_ReinforcementBarPitchOfWall - Reference: Mur de base:Mur exterieur doublé
Type - Pset_WallCommon - IsExternal: no; Reference: Mur de base:Mur exterieur doublé; ThermalTransmittance: 0.296605 kg/K/s3
Autre - Famille: Mur de base: Mur exterieur doublé; Famille et type: Mur de base: Mur exterieur doublé; ID du type: Mur de base: Mur exterieur doublé; Type: Mur de base: Mur exterieur doublé
Contraintes - Contrainte inférieure: Niveau: 0 RDC; Décalage inférieur: 0 cm; Extension inférieure: 0 cm; Extension supérieure: 0 cm; Lié au volume: no; Limite de pièce: yes; Partie inférieure attachée: no
Phase de construction - Phase de création: Projet
Structure - Activer le modèle analytique: no; Structure: no; Utilisation structurelle: Non porteur
Pset_QuantityTakeOff - sets with these values: 2
Pset_WallCommon - LoadBearing: no; IsExternal: yes
Name (Mur de base:Mur exterieur doublé:...) | Décalage supérieur (cm) | Partie supérieure attachée = ExtendToStructure | Ligne de justification | Hauteur non contrainte (cm) | Longueur (cm) | Surface (m2) | Volume (m3)
1618626 | 0 | yes | Nu fini: Extérieur | 300 | 496.918 | 12.5885 | 4.25981
1618628 | 0 | yes | Nu fini: Extérieur | 300 | 3143.84 | 94.9047 | 33.3099
1618631 | 0 | yes | Nu fini: Extérieur | 300 | 801.833 | 27.8945 | 9.77477
1618635 | -12.4439 | no | Nu fini: Extérieur | 306.786 | 538.108 | 12.2524 | 4.15968
1869114 | 0 | yes | Nu fini: Extérieur | 291 | 2183.19 | 42.0164 | 14.6579 | Contraintes - Contrainte supérieure: Niveau: 2 Toiture batiment
1869155 | 0 | yes | Nu fini: Extérieur | 291 | 1372.49 | 40.1673 | 13.8982 | Contraintes - Contrainte supérieure: Niveau: 2 Toiture batiment
2172880 | 0 | yes | Nu fini: Intérieur | 291 | 790.744 | 20.4329 | 7.17238 | Contraintes - Contrainte supérieure: Niveau: 2 Toiture batiment

# IfcWall: Mur de base:Mur pierre 10 cm (2)
In: 0 RDC
Type - PredefinedType: STANDARD; Material: Mur en pierres 10 cm
Type - Autre - Catégorie: Murs; Nom de la famille: Mur de base
Type - Construction - Retournement aux extrémités: Aucun(e); Retournement aux insertions: Ne pas retourner; Fonction: Extérieur; Largeur: 10 cm
Type - Données d'identification - Nom du type: Mur pierre 10 cm
Type - Graphismes - Couleur vue détail faible: 0
Type - Matériaux et finitions - Matériau structurel: Mur en pierres
Type - Propriétés analytiques - Rugosité: 1; Coefficient d'absorbance: 0.1; Coefficient de transfert de chaleur (U): 29; Masse thermique: 231000; Résistance thermique (R): 0.0344828
Type - Pset_QuantityTakeOff - Reference: Mur de base:Mur pierre 10 cm
Type - Pset_ReinforcementBarPitchOfWall - Reference: Mur de base:Mur pierre 10 cm
Type - Pset_WallCommon - IsExternal: no; Reference: Mur de base:Mur pierre 10 cm; ThermalTransmittance: 29 kg/K/s3
Autre - Famille: Mur de base: Mur pierre 10 cm; Famille et type: Mur de base: Mur pierre 10 cm; ID du type: Mur de base: Mur pierre 10 cm; Type: Mur de base: Mur pierre 10 cm
Contraintes - Contrainte inférieure: Niveau: 0 RDC; Décalage supérieur: 0 cm; Extension inférieure: 0 cm; Extension supérieure: 0 cm; Lié au volume: no; Limite de pièce: yes; Partie inférieure attachée: no; Ligne de justification: Nu fini: Extérieur; Partie supérieure attachée: no; Décalage inférieur: -2 cm
Phase de construction - Phase de création: Projet
Structure - Activer le modèle analytique: no; Structure: no; Utilisation structurelle: Non porteur
Pset_QuantityTakeOff - sets with these values: 2
Pset_WallCommon - LoadBearing: no; IsExternal: yes; ExtendToStructure: no
Name (Mur de base:Mur pierre 10 cm:...) | Hauteur non contrainte (cm) | Longueur (cm) | Surface (m2) | Volume (m3)
1640005 | 293 | 500.507 | 12.1399 | 1.20907 | Material: Mur en pierres; Contraintes - Contrainte supérieure: Niveau: 2 Toiture batiment
1640006 | 300 | 159.75 | 6.00094 | 0.595178

# IfcWallStandardCase: Mur de base:Int. Plâtre 7cm (4)
In: 0 RDC
Type - PredefinedType: STANDARD; Material: Plâtre 7 cm
Type - Autre - Catégorie: Murs; Nom de la famille: Mur de base
Type - Construction - Fonction: Intérieur; Retournement aux extrémités: Aucun(e); Retournement aux insertions: Ne pas retourner; Largeur: 7 cm
Type - Données d'identification - Nom du type: Int. Plâtre 7cm
Type - Graphismes - Motif vue détail faible: <Remplissage de solide>; Couleur vue détail faible: 12632256
Type - Matériaux et finitions - Matériau structurel: Plâtre
Type - Propriétés analytiques - Rugosité: 1; Coefficient d'absorbance: 0.1
Type - Pset_QuantityTakeOff - Reference: Mur de base:Int. Plâtre 7cm
Type - Pset_ReinforcementBarPitchOfWall - Reference: Mur de base:Int. Plâtre 7cm
Type - Pset_WallCommon - IsExternal: no; Reference: Mur de base:Int. Plâtre 7cm
BaseQuantities - Width: 7 cm
Autre - Famille: Mur de base: Int. Plâtre 7cm; Famille et type: Mur de base: Int. Plâtre 7cm; ID du type: Mur de base: Int. Plâtre 7cm; Type: Mur de base: Int. Plâtre 7cm
Contraintes - Contrainte inférieure: Niveau: 0 RDC; Décalage inférieur: 0 cm; Extension inférieure: 0 cm; Extension supérieure: 0 cm; Lié au volume: no; Partie inférieure attachée: no; Ligne de justification: Nu fini: Extérieur; Partie supérieure attachée: no
Phase de construction - Phase de création: Projet
Structure - Activer le modèle analytique: no; Structure: no; Utilisation structurelle: Non porteur
Pset_QuantityTakeOff - sets with these values: 2
Pset_WallCommon - LoadBearing: no; ExtendToStructure: no
Name (Mur de base:Int. Plâtre 7cm:...) | Height (cm) = Hauteur non contrainte (cm) | Length (cm) | GrossFootprintArea (m2) | NetVolume (m3) | NetSideArea (m2) | Limite de pièce | Décalage supérieur (cm) | Longueur (cm) | Surface (m2) | Volume (m3)
672343 | 110.009 | 784.156 | 0.548913 | 603852 | 86264.5 | yes | -189.991 | 784.156 | 8.64684 | 0.603856 | Graphismes - Marque centrale visible: no
673390 | 70 | 865.82 | 0.605075 | 424252 | 60607.4 | yes | -215 | 887.357 | 6.06074 | 0.423552
848625 | 100 | 109.986 | 0.0769882 | 76990 | 10998.6 | no | 0 | 131.283 | 1.09986 | 0.0769882
848692 | 100 | 110.015 | 0.077009 | 77010.8 | 11001.5 | no | 0 | 131.313 | 1.10015 | 0.077009

# IfcWallStandardCase: Mur de base:Lg1 (4)
In: -1 Soubassement
Type - PredefinedType: STANDARD; Material: Maçonnerie - Voile BA 20 cm
Type - Autre - Catégorie: Murs; Nom de la famille: Mur de base
Type - Construction - Retournement aux extrémités: Aucun(e); Retournement aux insertions: Ne pas retourner; Fonction: Soutènement; Largeur: 20 cm
Type - Données d'identification - Commentaires du type: Extérieur voile BA 20; Nom du type: Lg1
Type - Graphismes - Couleur vue détail faible: 0
Type - Matériaux et finitions - Matériau structurel: Maçonnerie - Voile BA
Type - Propriétés analytiques - Rugosité: 1; Coefficient d'absorbance: 0.1
Type - Pset_QuantityTakeOff - Reference: Mur de base:Lg1
Type - Pset_ReinforcementBarPitchOfWall - Reference: Mur de base:Lg1
Type - Pset_WallCommon - IsExternal: no; Reference: Mur de base:Lg1
BaseQuantities - Height: 50 cm; Width: 20 cm
Autre - Famille: Mur de base: Lg1; Famille et type: Mur de base: Lg1; ID du type: Mur de base: Lg1; Type: Mur de base: Lg1
Contraintes - Décalage inférieur: 0 cm; Décalage supérieur: 0 cm; Extension inférieure: 0 cm; Extension supérieure: 0 cm; Lié au volume: no; Partie inférieure attachée: no; Partie supérieure attachée: no; Contrainte inférieure: Niveau: -1 Soubassement; Contrainte supérieure: Niveau: 0 RDC; Hauteur non contrainte: 50 cm
Données d'identification - Commentaires: 20X50
Phase de construction - Phase de création: Projet
Structure - Activer le modèle analytique: yes; Enrobage d'armature - Autres faces: Paramètres de l'enrobage d'armature: Enrobage d'armature 1; Enrobage d'armature - Face extérieure: Paramètres de l'enrobage d'armature: Enrobage d'armature 1; Enrobage d'armature - Face intérieure: Paramètres de l'enrobage d'armature: Enrobage d'armature 1; Structure: yes; Utilisation structurelle: Porteur
Pset_QuantityTakeOff - sets with these values: 2
Pset_WallCommon - IsExternal: yes; LoadBearing: yes; ExtendToStructure: no
Name (Mur de base:Lg1:...) | Length (cm) | GrossFootprintArea (m2) | NetVolume (m3) | NetSideArea (m2) | Limite de pièce | Ligne de justification | Longueur (cm) | Surface (m2) | Volume (m3)
922663 | 547.336 | 1.04143 | 547336 | 27366.8 | yes | Axe porteur | 525.738 | 2.60359 | 0.520717
922946 | 514.075 | 0.99455 | 514075 | 25703.7 | yes | Axe porteur | 508.326 | 2.53548 | 0.497275
930646 | 377.232 | 0.727845 | 377232 | 18861.6 | no | Axe du mur | 380.57 | 1.88616 | 0.363923
2079338 | 530.249 | 1.02591 | 530249 | 26512.5 | no | Axe du mur | 550.462 | 2.61635 | 0.512953

# IfcWallStandardCase: Mur de base:Mur pierre 10 cm (2)
In: 0 RDC
Type - PredefinedType: STANDARD; Material: Mur en pierres 10 cm
Type - Autre - Catégorie: Murs; Nom de la famille: Mur de base
Type - Construction - Retournement aux extrémités: Aucun(e); Retournement aux insertions: Ne pas retourner; Fonction: Extérieur; Largeur: 10 cm
Type - Données d'identification - Nom du type: Mur pierre 10 cm
Type - Graphismes - Couleur vue détail faible: 0
Type - Matériaux et finitions - Matériau structurel: Mur en pierres
Type - Propriétés analytiques - Rugosité: 1; Coefficient d'absorbance: 0.1; Coefficient de transfert de chaleur (U): 29; Masse thermique: 231000; Résistance thermique (R): 0.0344828
Type - Pset_QuantityTakeOff - Reference: Mur de base:Mur pierre 10 cm
Type - Pset_ReinforcementBarPitchOfWall - Reference: Mur de base:Mur pierre 10 cm
Type - Pset_WallCommon - IsExternal: no; Reference: Mur de base:Mur pierre 10 cm; ThermalTransmittance: 29 kg/K/s3
BaseQuantities - Width: 10 cm
Autre - Famille: Mur de base: Mur pierre 10 cm; Famille et type: Mur de base: Mur pierre 10 cm; ID du type: Mur de base: Mur pierre 10 cm; Type: Mur de base: Mur pierre 10 cm
Contraintes - Contrainte inférieure: Niveau: 0 RDC; Extension inférieure: 0 cm; Extension supérieure: 0 cm; Lié au volume: no; Partie inférieure attachée: no; Ligne de justification: Nu fini: Extérieur; Contrainte supérieure: Niveau: 2 Toiture batiment; Décalage inférieur: -2 cm
Phase de construction - Phase de création: Projet
Structure - Activer le modèle analytique: no; Structure: no; Utilisation structurelle: Non porteur
Pset_QuantityTakeOff - sets with these values: 2
Pset_WallCommon - LoadBearing: no; IsExternal: yes
Name (Mur de base:Mur pierre 10 cm:...) | Height (cm) | Length (cm) | GrossFootprintArea (m2) | NetVolume (m3) | NetSideArea (m2) | Décalage supérieur (cm) | Limite de pièce | Partie supérieure attachée = ExtendToStructure | Hauteur non contrainte (cm) | Longueur (cm) | Surface (m2) | Volume (m3)
1640008 | 418.265 | 51.307 | 0.051307 | 214599 | 21459.9 | 0 | yes | no | 293 | 51.307 | 2.14217 | 0.214217
1879198 | 457.944 | 474.184 | 0.470903 | 2171499 | 217150 | 200 | no | yes | 493 | 441.918 | 13.828 | 1.35503

# IfcWallStandardCase: Mur de base:Sbt1 (7)
In: -1 Soubassement
Type - PredefinedType: STANDARD; Material: Maçonnerie - Voile BA 20 cm
Type - Autre - Catégorie: Murs; Nom de la famille: Mur de base
Type - Construction - Retournement aux extrémités: Aucun(e); Retournement aux insertions: Ne pas retourner; Fonction: Soutènement; Largeur: 20 cm
Type - Données d'identification - Commentaires du type: Extérieur voile BA 20; Nom du type: Sbt1
Type - Graphismes - Couleur vue détail faible: 0
Type - Matériaux et finitions - Matériau structurel: Maçonnerie - Voile BA
Type - Propriétés analytiques - Rugosité: 1; Coefficient d'absorbance: 0.1
Type - Pset_QuantityTakeOff - Reference: Mur de base:Sbt1
Type - Pset_ReinforcementBarPitchOfWall - Reference: Mur de base:Sbt1
Type - Pset_WallCommon - IsExternal: no; Reference: Mur de base:Sbt1
BaseQuantities - Height: 50 cm; Width: 20 cm
Autre - Famille: Mur de base: Sbt1; Famille et type: Mur de base: Sbt1; ID du type: Mur de base: Sbt1; Type: Mur de base: Sbt1
Contraintes - Décalage inférieur: 0 cm; Décalage supérieur: 0 cm; Extension inférieure: 0 cm; Extension supérieure: 0 cm; Lié au volume: no; Partie inférieure attachée: no; Partie supérieure attachée: no; Contrainte inférieure: Niveau: -1 Soubassement; Contrainte supérieure: Niveau: 0 RDC; Hauteur non contrainte: 50 cm
Phase de construction - Phase de création: Projet
Pset_QuantityTakeOff - sets with these values: 2
Pset_WallCommon - IsExternal: yes; ExtendToStructure: no
Name (Mur de base:Sbt1:...) | Length (cm) | GrossFootprintArea (m2) | NetVolume (m3) | NetSideArea (m2) | Limite de pièce | Ligne de justification | Longueur (cm) | Surface (m2) | Volume (m3) | Activer le modèle analytique = Structure = LoadBearing | Enrobage d'armature - Autres faces = Enrobage d'armature - Face extérieure = Enrobage d'armature - Face intérieure | Utilisation structurelle
921290 | 835.5 | 1.66286 | 835500 | 41775 | yes | Axe porteur | 810.996 | 4.1775 | 0.831429 | yes | Paramètres de l'enrobage d'armature: Enrobage d'armature 1 | Porteur
921740 | 1020.36 | 2.03258 | 1020360 | 51018 | yes | Axe porteur | 1036.72 | 5.1018 | 1.01629 | yes | Paramètres de l'enrobage d'armature: Enrobage d'armature 1 | Porteur
924087 | 984.169 | 1.96334 | 984169 | 49208.5 | yes | Axe du mur | 1012.37 | 4.92085 | 0.981669 | yes | Paramètres de l'enrobage d'armature: Enrobage d'armature 1 | Porteur
927328 | 980.689 | 1.95829 | 980689 | 49034.4 | yes | Axe porteur | 989.265 | 4.90344 | 0.979147 | yes | Paramètres de l'enrobage d'armature: Enrobage d'armature 1 | Porteur
1230850 | 855.075 | 1.70018 | 855075 | 42753.7 | no | Nu fini: Intérieur | 829.476 | 4.25044 | 0.850088 | yes | Paramètres de l'enrobage d'armature: Enrobage d'armature 1 | Porteur
1907748 | 3156.02 | 6.30697 | 3156021 | 157801 | no | Nu porteur: Intérieur | 3153.8 | 15.7801 | 3.15348 | no |  | Non porteur
2185411 | 782.909 | 1.56082 | 782909 | 39145.5 | no | Axe porteur | 800.715 | 3.91455 | 0.780409 | no |  | Non porteur

# IfcWindow: Menuiserie 1.1, trapzoid_1824:Menuiserie 1.1:2173543
In: 0 RDC
Type - OperationType: TRIPLE_PANEL_VERTICAL; ParameterTakesPrecedence: no; Sizeable: no; Material: Verre, Aluminium
Type - Autre - Catégorie: Fenêtres; Default Sill Height: 91.44 cm; Nom de la famille: trapzoid_1824
Type - Construction - Fermeture du mur: Les deux
Type - Cotes - Hauteur: 0 cm; Hauteur brute: 0 cm; Largeur brute: 0 cm; Largeur: 220 cm
Type - Données d'identification - Commentaires du type: Menuiserie 1.1; Description: Menuiserie 1.1; Marque de type: 30; Nom du type: Menuiserie 1.1; Note d'identification: Paroi vitrée
Type - Propriétés analytiques - Coefficient d'apport thermique solaire: 0.61; Coefficient de transfert de chaleur (U): 1.533; Construction analytique: Triple vitrage - 1/4 po. d'épaisseur - verre transparent/transparent/transparent; Résistance thermique (R): 0.652316; Transmission de la lumière visible: 0.7
OverallHeight: 90.8034 cm; OverallWidth: 222.54 cm
Pset_QuantityTakeOff - Reference: trapzoid_1824:Menuiserie 1.1
Pset_WindowCommon - IsExternal: yes; Reference: trapzoid_1824:Menuiserie 1.1; ThermalTransmittance: 1.533 kg/K/s3
BaseQuantities - Height: 0 cm; Width: 220 cm; Area: 0 m2
Autre - ID hôte: Mur de base: Mur exterieur doublé; glass: Verre; Famille: trapzoid_1824: Menuiserie 1.1; Famille et type: trapzoid_1824: Menuiserie 1.1; Hauteur sous linteau: 170 cm; ID du type: trapzoid_1824: Menuiserie 1.1; Leg Height: 65 cm; Type: trapzoid_1824: Menuiserie 1.1; Window Pitch: 84 deg
Contraintes - Niveau: Niveau: 0 RDC; Hauteur de l'appui: 170 cm
Cotes - Surface: 2.45158 m2; Volume: 0.0198639 m3
Données d'identification - Commentaires: Menuiserie 1.1; Identifiant: 14
Phase de construction - Phase de création: Projet

# IfcWindow: Menuiserie 1.2, trapzoid_1824:Menuiserie 1.2:2173518
In: 0 RDC
Type - ParameterTakesPrecedence: no; Sizeable: no; Material: Verre, Aluminium
Type - Autre - Catégorie: Fenêtres; Default Sill Height: 91.44 cm; Nom de la famille: trapzoid_1824
Type - Construction - Fermeture du mur: Par hôte
Type - Cotes - Hauteur: 0 cm; Hauteur brute: 0 cm; Largeur: 185 cm; Largeur brute: 0 cm
Type - Données d'identification - Marque de type: 31; Nom du type: Menuiserie 1.2; Note d'identification: Paroi vitrée
Type - Propriétés analytiques - Coefficient d'apport thermique solaire: 0.61; Coefficient de transfert de chaleur (U): 1.533; Construction analytique: Triple vitrage - 1/4 po. d'épaisseur - verre transparent/transparent/transparent; Résistance thermique (R): 0.652316; Transmission de la lumière visible: 0.7
OverallHeight: 110.245 cm; OverallWidth: 187.54 cm
Pset_QuantityTakeOff - Reference: trapzoid_1824:Menuiserie 1.2
Pset_WindowCommon - IsExternal: yes; Reference: trapzoid_1824:Menuiserie 1.2; ThermalTransmittance: 1.533 kg/K/s3
BaseQuantities - Height: 0 cm; Width: 185 cm; Area: 0 m2
Autre - ID hôte: Mur de base: Mur exterieur doublé; Famille: trapzoid_1824: Menuiserie 1.2; Famille et type: trapzoid_1824: Menuiserie 1.2; glass: Verre; Hauteur sous linteau: 170 cm; ID du type: trapzoid_1824: Menuiserie 1.2; Leg Height: 88.12 cm; Type: trapzoid_1824: Menuiserie 1.2; Window Pitch: 84 deg
Contraintes - Niveau: Niveau: 0 RDC; Hauteur de l'appui: 170 cm
Cotes - Surface: 2.54112 m2; Volume: 0.0195739 m3
Données d'identification - Identifiant: 15
Phase de construction - Phase de création: Projet

# IfcWindow: Menuiserie 1.3, trapzoid_1824:Menuiserie 1.3:2173519
In: 0 RDC
Type - ParameterTakesPrecedence: no; Sizeable: no; Material: Verre, Aluminium
Type - Autre - Catégorie: Fenêtres; Default Sill Height: 91.44 cm; Nom de la famille: trapzoid_1824
Type - Construction - Fermeture du mur: Par hôte
Type - Cotes - Hauteur: 0 cm; Hauteur brute: 0 cm; Largeur brute: 0 cm; Largeur: 185 cm
Type - Données d'identification - Marque de type: 33; Nom du type: Menuiserie 1.3; Note d'identification: Paroi vitrée
Type - Propriétés analytiques - Coefficient d'apport thermique solaire: 0.61; Coefficient de transfert de chaleur (U): 1.533; Construction analytique: Triple vitrage - 1/4 po. d'épaisseur - verre transparent/transparent/transparent; Résistance thermique (R): 0.652316; Transmission de la lumière visible: 0.7
OverallHeight: 129.685 cm; OverallWidth: 187.54 cm
Pset_QuantityTakeOff - Reference: trapzoid_1824:Menuiserie 1.3
Pset_WindowCommon - IsExternal: yes; Reference: trapzoid_1824:Menuiserie 1.3; ThermalTransmittance: 1.533 kg/K/s3
BaseQuantities - Height: 0 cm; Width: 185 cm; Area: 0 m2
Autre - ID hôte: Mur de base: Mur exterieur doublé; glass: Verre; Famille: trapzoid_1824: Menuiserie 1.3; Famille et type: trapzoid_1824: Menuiserie 1.3; Hauteur sous linteau: 170 cm; ID du type: trapzoid_1824: Menuiserie 1.3; Leg Height: 107.56 cm; Type: trapzoid_1824: Menuiserie 1.3; Window Pitch: 84 deg
Contraintes - Niveau: Niveau: 0 RDC; Hauteur de l'appui: 170 cm
Cotes - Surface: 2.95168 m2; Volume: 0.0216855 m3
Données d'identification - Identifiant: 16
Phase de construction - Phase de création: Projet

# IfcWindow: Menuiserie 10.1, fixed_trapezoidal_window_11265:Menuiserie 10.1:1876427
In: 0 RDC
Type - ParameterTakesPrecedence: no; Sizeable: no; Classification: B2020100 Windows (Uniformat); Material: Verre, Aluminium
Type - Autre - Catégorie: Fenêtres; Nom de la famille: fixed_trapezoidal_window_11265
Type - Construction - Fermeture du mur: Par hôte
Type - Cotes - Default Sill Height: 120 cm; Hauteur: 67 cm; Largeur: 127 cm; slope to 12: 0.628893; top slope: 3 deg; Window Inset: 5 cm
Type - Données d'identification - Code d'assemblage: B2020100; Description de l'assemblage: Windows; Marque de type: 57; Nom du type: Menuiserie 10.1; Note d'identification: Paroi vitrée; Numéro OmniClass: 23.30.20.17.11; Titre OmniClass: Fixed Windows
Type - Matériaux et finitions - Glass Pane Material: Verre; Sash Material: Aluminium
Type - Propriétés analytiques - Coefficient d'apport thermique solaire: 0.56; Coefficient de transfert de chaleur (U): 1.533; Construction analytique: Triple vitrage - 1/4 po. d'épaisseur - verre transparent/transparent/énergétique (e = 0.2); Résistance thermique (R): 0.652316; Transmission de la lumière visible: 0.64
OverallHeight: 67 cm; OverallWidth: 127 cm
Pset_QuantityTakeOff - Reference: fixed_trapezoidal_window_11265:Menuiserie 10.1
Pset_WindowCommon - IsExternal: yes; Reference: fixed_trapezoidal_window_11265:Menuiserie 10.1; ThermalTransmittance: 1.533 kg/K/s3
BaseQuantities - Height: 67 cm; Width: 127 cm; Area: 0.8509 m2
Autre - ID hôte: Mur de base: Mur exterieur doublé; Famille: fixed_trapezoidal_window_11265: Menuiserie 10.1; Famille et type: fixed_trapezoidal_window_11265: Menuiserie 10.1; Hauteur sous linteau: 413.5 cm; ID du type: fixed_trapezoidal_window_11265: Menuiserie 10.1; Type: fixed_trapezoidal_window_11265: Menuiserie 10.1
Contraintes - Niveau: Niveau: 0 RDC; Hauteur de l'appui: 346.5 cm
Cotes - Surface: 1.39485 m2; Volume: 0.0343257 m3
Données d'identification - Identifiant: 86
Phase de construction - Phase de création: Projet

# IfcWindow: Menuiserie 10.2, fixed_trapezoidal_window_11265:Menuiserie 10.2:1876428
In: 0 RDC
Type - ParameterTakesPrecedence: no; Sizeable: no; Classification: B2020100 Windows (Uniformat); Material: Verre, Aluminium
Type - Autre - Catégorie: Fenêtres; Nom de la famille: fixed_trapezoidal_window_11265
Type - Construction - Fermeture du mur: Par hôte
Type - Cotes - Default Sill Height: 121.92 cm; Hauteur: 61 cm; Largeur: 133 cm; slope to 12: 0.628893; top slope: 3 deg; Window Inset: 5 cm
Type - Données d'identification - Code d'assemblage: B2020100; Description de l'assemblage: Windows; Marque de type: 58; Nom du type: Menuiserie 10.2; Note d'identification: Paroi vitrée; Numéro OmniClass: 23.30.20.17.11; Titre OmniClass: Fixed Windows
Type - Matériaux et finitions - Glass Pane Material: Verre; Sash Material: Aluminium
Type - Propriétés analytiques - Coefficient d'apport thermique solaire: 0.56; Coefficient de transfert de chaleur (U): 1.533; Construction analytique: Triple vitrage - 1/4 po. d'épaisseur - verre transparent/transparent/énergétique (e = 0.2); Résistance thermique (R): 0.652316; Transmission de la lumière visible: 0.64
OverallHeight: 61 cm; OverallWidth: 133 cm
Pset_QuantityTakeOff - Reference: fixed_trapezoidal_window_11265:Menuiserie 10.2
Pset_WindowCommon - IsExternal: yes; Reference: fixed_trapezoidal_window_11265:Menuiserie 10.2; ThermalTransmittance: 1.533 kg/K/s3
BaseQuantities - Height: 61 cm; Width: 133 cm; Area: 0.8113 m2
Autre - ID hôte: Mur de base: Mur exterieur doublé; Famille: fixed_trapezoidal_window_11265: Menuiserie 10.2; Famille et type: fixed_trapezoidal_window_11265: Menuiserie 10.2; Hauteur sous linteau: 413.5 cm; ID du type: fixed_trapezoidal_window_11265: Menuiserie 10.2; Type: fixed_trapezoidal_window_11265: Menuiserie 10.2
Contraintes - Niveau: Niveau: 0 RDC; Hauteur de l'appui: 352.5 cm
Cotes - Surface: 1.35377 m2; Volume: 0.0337898 m3
Données d'identification - Identifiant: 166
Phase de construction - Phase de création: Projet

# IfcWindow: Menuiserie 10.3, fixed_trapezoidal_window_11265:Menuiserie 10.3:1876432
In: 0 RDC
Type - ParameterTakesPrecedence: no; Sizeable: no; Classification: B2020100 Windows (Uniformat); Material: Verre, Aluminium
Type - Autre - Catégorie: Fenêtres; Nom de la famille: fixed_trapezoidal_window_11265
Type - Construction - Fermeture du mur: Par hôte
Type - Cotes - Default Sill Height: 121.92 cm; Hauteur: 55 cm; Largeur: 120 cm; slope to 12: 0.628893; top slope: 3 deg; Window Inset: 5 cm
Type - Données d'identification - Code d'assemblage: B2020100; Description de l'assemblage: Windows; Marque de type: 59; Nom du type: Menuiserie 10.3; Note d'identification: Paroi vitrée; Numéro OmniClass: 23.30.20.17.11; Titre OmniClass: Fixed Windows
Type - Matériaux et finitions - Glass Pane Material: Verre; Sash Material: Aluminium
Type - Propriétés analytiques - Coefficient d'apport thermique solaire: 0.61; Coefficient de transfert de chaleur (U): 1.533; Construction analytique: Triple vitrage - 1/4 po. d'épaisseur - verre transparent/transparent/transparent; Résistance thermique (R): 0.652316; Transmission de la lumière visible: 0.7
OverallHeight: 55 cm; OverallWidth: 120 cm
Pset_QuantityTakeOff - Reference: fixed_trapezoidal_window_11265:Menuiserie 10.3
Pset_WindowCommon - IsExternal: yes; Reference: fixed_trapezoidal_window_11265:Menuiserie 10.3; ThermalTransmittance: 1.533 kg/K/s3
BaseQuantities - Height: 55 cm; Width: 120 cm; Area: 0.66 m2
Autre - ID hôte: Mur de base: Mur exterieur doublé; Famille: fixed_trapezoidal_window_11265: Menuiserie 10.3; Famille et type: fixed_trapezoidal_window_11265: Menuiserie 10.3; Hauteur sous linteau: 414 cm; ID du type: fixed_trapezoidal_window_11265: Menuiserie 10.3; Type: fixed_trapezoidal_window_11265: Menuiserie 10.3
Contraintes - Niveau: Niveau: 0 RDC; Hauteur de l'appui: 359 cm
Cotes - Surface: 1.14995 m2; Volume: 0.0294851 m3
Données d'identification - Identifiant: 174
Phase de construction - Phase de création: Projet

# IfcWindow: Menuiserie 11.1, fixed_trapezoidal_window_11265:Menuiserie 11.1:1876429
In: 0 RDC
Type - ParameterTakesPrecedence: no; Sizeable: no; Classification: B2020100 Windows (Uniformat); Material: Verre, Aluminium
Type - Autre - Catégorie: Fenêtres; Nom de la famille: fixed_trapezoidal_window_11265
Type - Construction - Fermeture du mur: Par hôte
Type - Cotes - Default Sill Height: 121.92 cm; Hauteur: 60 cm; Largeur: 145 cm; slope to 12: 0.628893; top slope: 3 deg; Window Inset: 5 cm
Type - Données d'identification - Code d'assemblage: B2020100; Description de l'assemblage: Windows; Marque de type: 60; Nom du type: Menuiserie 11.1; Note d'identification: Paroi vitrée; Numéro OmniClass: 23.30.20.17.11; Titre OmniClass: Fixed Windows
Type - Matériaux et finitions - Glass Pane Material: Verre; Sash Material: Aluminium
Type - Propriétés analytiques - Coefficient d'apport thermique solaire: 0.56; Coefficient de transfert de chaleur (U): 1.533; Construction analytique: Triple vitrage - 1/4 po. d'épaisseur - verre transparent/transparent/énergétique (e = 0.2); Résistance thermique (R): 0.652316; Transmission de la lumière visible: 0.64
OverallHeight: 60 cm; OverallWidth: 145 cm
Pset_QuantityTakeOff - Reference: fixed_trapezoidal_window_11265:Menuiserie 11.1
Pset_WindowCommon - IsExternal: yes; Reference: fixed_trapezoidal_window_11265:Menuiserie 11.1; ThermalTransmittance: 1.533 kg/K/s3
BaseQuantities - Height: 60 cm; Width: 145 cm; Area: 0.87 m2
Autre - ID hôte: Mur de base: Mur exterieur doublé; Famille: fixed_trapezoidal_window_11265: Menuiserie 11.1; Famille et type: fixed_trapezoidal_window_11265: Menuiserie 11.1; Hauteur sous linteau: 430.5 cm; ID du type: fixed_trapezoidal_window_11265: Menuiserie 11.1; Type: fixed_trapezoidal_window_11265: Menuiserie 11.1
Contraintes - Niveau: Niveau: 0 RDC; Hauteur de l'appui: 370.5 cm
Cotes - Surface: 1.44106 m2; Volume: 0.0358815 m3
Données d'identification - Identifiant: 168
Phase de construction - Phase de création: Projet

# IfcWindow: Menuiserie 11.2, fixed_trapezoidal_window_11265:Menuiserie 11.2:1876430
In: 0 RDC
Type - ParameterTakesPrecedence: no; Sizeable: no; Classification: B2020100 Windows (Uniformat); Material: Verre, Aluminium
Type - Autre - Catégorie: Fenêtres; Nom de la famille: fixed_trapezoidal_window_11265
Type - Construction - Fermeture du mur: Par hôte
Type - Cotes - Default Sill Height: 121.92 cm; Hauteur: 52 cm; Largeur: 139 cm; slope to 12: 0.839122; top slope: 4 deg; Window Inset: 5 cm
Type - Données d'identification - Code d'assemblage: B2020100; Description de l'assemblage: Windows; Marque de type: 61; Nom du type: Menuiserie 11.2; Note d'identification: Paroi vitrée; Numéro OmniClass: 23.30.20.17.11; Titre OmniClass: Fixed Windows
Type - Matériaux et finitions - Glass Pane Material: Verre; Sash Material: Aluminium
Type - Propriétés analytiques - Coefficient d'apport thermique solaire: 0.56; Coefficient de transfert de chaleur (U): 1.533; Construction analytique: Triple vitrage - 1/4 po. d'épaisseur - verre transparent/transparent/énergétique (e = 0.2); Résistance thermique (R): 0.652316; Transmission de la lumière visible: 0.64
OverallHeight: 52 cm; OverallWidth: 139 cm
Pset_QuantityTakeOff - Reference: fixed_trapezoidal_window_11265:Menuiserie 11.2
Pset_WindowCommon - IsExternal: yes; Reference: fixed_trapezoidal_window_11265:Menuiserie 11.2; ThermalTransmittance: 1.533 kg/K/s3
BaseQuantities - Height: 52 cm; Width: 139 cm; Area: 0.7228 m2
Autre - ID hôte: Mur de base: Mur exterieur doublé; Famille: fixed_trapezoidal_window_11265: Menuiserie 11.2; Famille et type: fixed_trapezoidal_window_11265: Menuiserie 11.2; Hauteur sous linteau: 430.75 cm; ID du type: fixed_trapezoidal_window_11265: Menuiserie 11.2; Type: fixed_trapezoidal_window_11265: Menuiserie 11.2
Contraintes - Niveau: Niveau: 0 RDC; Hauteur de l'appui: 378.75 cm
Cotes - Surface: 1.23455 m2; Volume: 0.0318802 m3
Données d'identification - Identifiant: 169
Phase de construction - Phase de création: Projet

# IfcWindow: Menuiserie 11.3, fixed_trapezoidal_window_11265:Menuiserie 11.3:1876431
In: 0 RDC
Type - ParameterTakesPrecedence: no; Sizeable: no; Classification: B2020100 Windows (Uniformat); Material: Verre, Aluminium
Type - Autre - Catégorie: Fenêtres; Nom de la famille: fixed_trapezoidal_window_11265
Type - Construction - Fermeture du mur: Par hôte
Type - Cotes - Default Sill Height: 121.92 cm; Hauteur: 42.5 cm; Largeur: 140 cm; slope to 12: 0.628893; top slope: 3 deg; Window Inset: 5 cm
Type - Données d'identification - Code d'assemblage: B2020100; Description de l'assemblage: Windows; Marque de type: 62; Nom du type: Menuiserie 11.3; Note d'identification: Paroi vitrée; Numéro OmniClass: 23.30.20.17.11; Titre OmniClass: Fixed Windows
Type - Matériaux et finitions - Glass Pane Material: Verre; Sash Material: Aluminium
Type - Propriétés analytiques - Coefficient d'apport thermique solaire: 0.56; Coefficient de transfert de chaleur (U): 1.533; Construction analytique: Triple vitrage - 1/4 po. d'épaisseur - verre transparent/transparent/énergétique (e = 0.2); Résistance thermique (R): 0.652316; Transmission de la lumière visible: 0.64
OverallHeight: 42.5 cm; OverallWidth: 140 cm
Pset_QuantityTakeOff - Reference: fixed_trapezoidal_window_11265:Menuiserie 11.3
Pset_WindowCommon - IsExternal: yes; Reference: fixed_trapezoidal_window_11265:Menuiserie 11.3; ThermalTransmittance: 1.533 kg/K/s3
BaseQuantities - Height: 42.5 cm; Width: 140 cm; Area: 0.595 m2
Autre - ID hôte: Mur de base: Mur exterieur doublé; Famille: fixed_trapezoidal_window_11265: Menuiserie 11.3; Famille et type: fixed_trapezoidal_window_11265: Menuiserie 11.3; Hauteur sous linteau: 430.75 cm; ID du type: fixed_trapezoidal_window_11265: Menuiserie 11.3; Type: fixed_trapezoidal_window_11265: Menuiserie 11.3
Contraintes - Niveau: Niveau: 0 RDC; Hauteur de l'appui: 388.25 cm
Cotes - Surface: 1.1019 m2; Volume: 0.0295174 m3
Données d'identification - Identifiant: 170
Phase de construction - Phase de création: Projet

# IfcWindow: Menuiserie 4, 3 Vantaux - Droits:Menuiserie 4:1618636
In: 0 RDC
Type - OperationType: TRIPLE_PANEL_VERTICAL; ParameterTakesPrecedence: no; Sizeable: no; Material: Aluminium, Verre, Métal
Type - Autre - Catégorie: Fenêtres; Nom de la famille: 3 Vantaux - Droits
Type - Construction - Appui Alu: no; Fermeture du mur: Extérieur
Type - Contraintes - A. App.: 90 deg; A: 3.5 cm; H. App: 8 cm
Type - Cotes - Ep. Isolant: 14 cm; Hauteur: 100 cm; Hauteur de la poignée: 140 cm; Largeur: 390 cm
Type - Données d'identification - Marque de type: 63; Nom du type: Menuiserie 4
Type - Matériaux et finitions - Appui: Aluminium; Fenêtre: Aluminium; Poignée: Aluminium; Tapées: Métal; Vitrage: Verre
Type - Propriétés analytiques - Coefficient d'apport thermique solaire: 0.56; Coefficient de transfert de chaleur (U): 1.533; Construction analytique: Triple vitrage - 1/4 po. d'épaisseur - verre transparent/transparent/énergétique (e = 0.2); Résistance thermique (R): 0.652316; Transmission de la lumière visible: 0.64
OverallHeight: 113 cm; OverallWidth: 400 cm
Pset_QuantityTakeOff - Reference: 3 Vantaux - Droits:Menuiserie 4
Pset_WindowCommon - IsExternal: yes; Reference: 3 Vantaux - Droits:Menuiserie 4; ThermalTransmittance: 1.533 kg/K/s3
BaseQuantities - Height: 100 cm; Width: 390 cm; Area: 3.9 m2
Autre - ID hôte: Mur de base: Mur exterieur doublé; Famille: 3 Vantaux - Droits: Menuiserie 4; Famille et type: 3 Vantaux - Droits: Menuiserie 4; Hauteur sous linteau: 220 cm; ID du type: 3 Vantaux - Droits: Menuiserie 4; Type: 3 Vantaux - Droits: Menuiserie 4
Contraintes - Niveau: Niveau: 0 RDC; Hauteur de l'appui: 120 cm
Cotes - Surface: 8.84618 m2; Volume: 0.163378 m3
Données d'identification - Identifiant: 10
Graphismes - A battant: yes; A soufflet: yes; Encadrement intérieur: no
Phase de construction - Phase de création: Projet

# IfcWindow: Menuiserie 8, 3 Vantaux - Droits:Menuiserie 8:1618634
In: 0 RDC
Type - OperationType: TRIPLE_PANEL_VERTICAL; ParameterTakesPrecedence: no; Sizeable: no; Material: Aluminium, Verre, Métal
Type - Autre - Catégorie: Fenêtres; Nom de la famille: 3 Vantaux - Droits
Type - Construction - Appui Alu: no; Fermeture du mur: Extérieur
Type - Contraintes - A: 3.5 cm; A. App.: 90 deg; H. App: 8 cm
Type - Cotes - Ep. Isolant: 14 cm; Hauteur: 100 cm; Hauteur de la poignée: 140 cm; Largeur: 410 cm
Type - Données d'identification - Marque de type: 28; Nom du type: Menuiserie 8; Note d'identification: Paroi vitrée
Type - Matériaux et finitions - Appui: Aluminium; Fenêtre: Aluminium; Poignée: Aluminium; Tapées: Métal; Vitrage: Verre
Type - Propriétés analytiques - Coefficient d'apport thermique solaire: 0.56; Coefficient de transfert de chaleur (U): 1.533; Construction analytique: Triple vitrage - 1/4 po. d'épaisseur - verre transparent/transparent/énergétique (e = 0.2); Résistance thermique (R): 0.652316; Transmission de la lumière visible: 0.64
OverallHeight: 113 cm; OverallWidth: 420 cm
Pset_QuantityTakeOff - Reference: 3 Vantaux - Droits:Menuiserie 8
Pset_WindowCommon - IsExternal: yes; Reference: 3 Vantaux - Droits:Menuiserie 8; ThermalTransmittance: 1.533 kg/K/s3
BaseQuantities - Height: 100 cm; Width: 410 cm; Area: 4.1 m2
Autre - ID hôte: Mur de base: Mur exterieur doublé; Famille: 3 Vantaux - Droits: Menuiserie 8; Famille et type: 3 Vantaux - Droits: Menuiserie 8; Hauteur sous linteau: 220 cm; ID du type: 3 Vantaux - Droits: Menuiserie 8; Type: 3 Vantaux - Droits: Menuiserie 8
Contraintes - Niveau: Niveau: 0 RDC; Hauteur de l'appui: 120 cm
Cotes - Surface: 9.26444 m2; Volume: 0.171014 m3
Données d'identification - Identifiant: 8
Graphismes - A battant: yes; A soufflet: yes; Encadrement intérieur: no
Phase de construction - Phase de création: Projet

# IfcWindow: Menuiserie 9.1, fixed_trapezoidal_window_11265:Menuiserie 9.1:1876424
In: 0 RDC
Type - ParameterTakesPrecedence: no; Sizeable: no; Classification: B2020100 Windows (Uniformat); Material: Verre, Aluminium
Type - Autre - Catégorie: Fenêtres; Nom de la famille: fixed_trapezoidal_window_11265
Type - Construction - Fermeture du mur: Par hôte
Type - Cotes - Default Sill Height: 121.92 cm; Hauteur: 85 cm; Largeur: 130 cm; slope to 12: 0.839122; top slope: 4 deg; Window Inset: 5 cm
Type - Données d'identification - Code d'assemblage: B2020100; Description de l'assemblage: Windows; Marque de type: 40; Nom du type: Menuiserie 9.1; Note d'identification: Paroi vitrée; Numéro OmniClass: 23.30.20.17.11; Titre OmniClass: Fixed Windows
Type - Matériaux et finitions - Glass Pane Material: Verre; Sash Material: Aluminium
Type - Propriétés analytiques - Coefficient d'apport thermique solaire: 0.56; Coefficient de transfert de chaleur (U): 1.533; Construction analytique: Triple vitrage - 1/4 po. d'épaisseur - verre transparent/transparent/énergétique (e = 0.2); Résistance thermique (R): 0.652316; Transmission de la lumière visible: 0.64
OverallHeight: 85 cm; OverallWidth: 130 cm
Pset_QuantityTakeOff - Reference: fixed_trapezoidal_window_11265:Menuiserie 9.1
Pset_WindowCommon - IsExternal: yes; Reference: fixed_trapezoidal_window_11265:Menuiserie 9.1; ThermalTransmittance: 1.533 kg/K/s3
BaseQuantities - Height: 85 cm; Width: 130 cm; Area: 1.105 m2
Autre - ID hôte: Mur de base: Mur exterieur doublé; Famille: fixed_trapezoidal_window_11265: Menuiserie 9.1; Famille et type: fixed_trapezoidal_window_11265: Menuiserie 9.1; Hauteur sous linteau: 406.5 cm; ID du type: fixed_trapezoidal_window_11265: Menuiserie 9.1; Type: fixed_trapezoidal_window_11265: Menuiserie 9.1
Contraintes - Niveau: Niveau: 0 RDC; Hauteur de l'appui: 321.5 cm
Cotes - Surface: 1.69163 m2; Volume: 0.0399196 m3
Données d'identification - Identifiant: 48
Phase de construction - Phase de création: Projet

# IfcWindow: Menuiserie 9.2, fixed_trapezoidal_window_11265:Menuiserie 9.2:1876425
In: 0 RDC
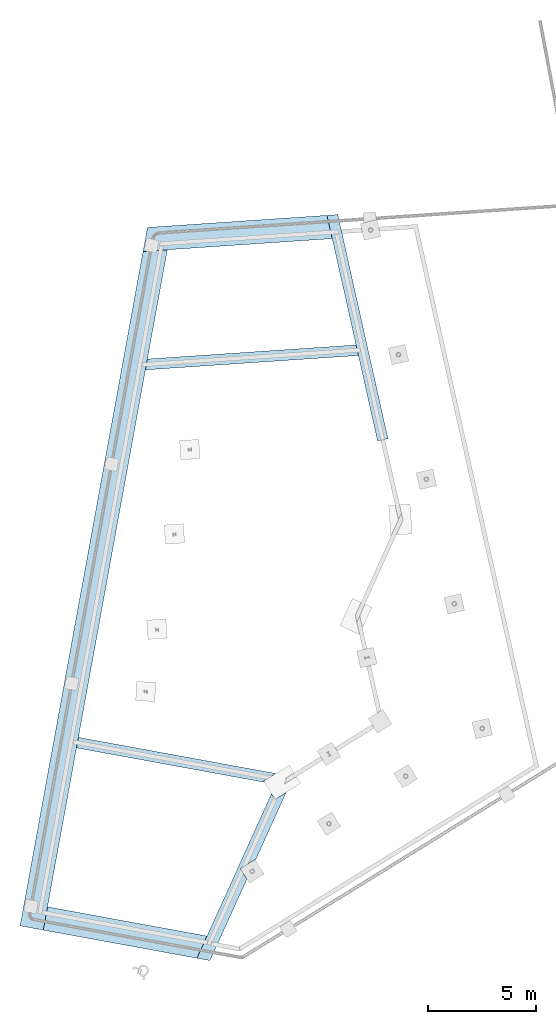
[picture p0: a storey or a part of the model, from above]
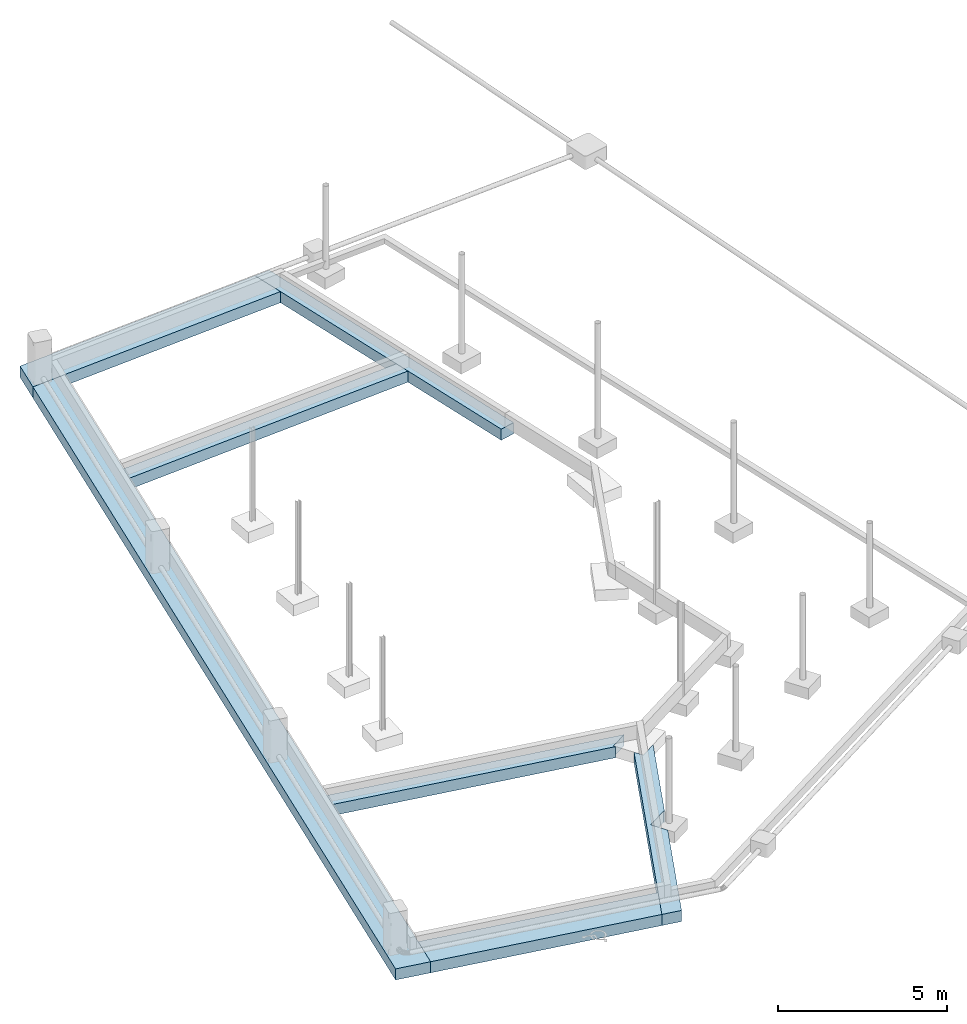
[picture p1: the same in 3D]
Properties of the parts of a building model (IFC2X3), part 5 of 5

# IfcWindow: Menuiserie 9.2, fixed_trapezoidal_window_11265:Menuiserie 9.2:1876425
Type - ParameterTakesPrecedence: no; Sizeable: no; Classification: B2020100 Windows (Uniformat); Material: Verre, Aluminium
Type - Autre - Catégorie: Fenêtres; Nom de la famille: fixed_trapezoidal_window_11265
Type - Construction - Fermeture du mur: Par hôte
Type - Cotes - Default Sill Height: 121.92 cm; Hauteur: 75.9 cm; Largeur: 120 cm; slope to 12: 0.839122; top slope: 4 deg; Window Inset: 5 cm
Type - Données d'identification - Code d'assemblage: B2020100; Description de l'assemblage: Windows; Marque de type: 55; Nom du type: Menuiserie 9.2; Note d'identification: Paroi vitrée; Numéro OmniClass: 23.30.20.17.11; Titre OmniClass: Fixed Windows
Type - Matériaux et finitions - Glass Pane Material: Verre; Sash Material: Aluminium
Type - Propriétés analytiques - Coefficient d'apport thermique solaire: 0.56; Coefficient de transfert de chaleur (U): 1.533; Construction analytique: Triple vitrage - 1/4 po. d'épaisseur - verre transparent/transparent/énergétique (e = 0.2); Résistance thermique (R): 0.652316; Transmission de la lumière visible: 0.64
OverallHeight: 75.9 cm; OverallWidth: 120 cm
Pset_QuantityTakeOff - Reference: fixed_trapezoidal_window_11265:Menuiserie 9.2
Pset_WindowCommon - IsExternal: yes; Reference: fixed_trapezoidal_window_11265:Menuiserie 9.2; ThermalTransmittance: 1.533 kg/K/s3
BaseQuantities - Height: 75.9 cm; Width: 120 cm; Area: 0.9108 m2
Autre - ID hôte: Mur de base: Mur exterieur doublé; Famille: fixed_trapezoidal_window_11265: Menuiserie 9.2; Famille et type: fixed_trapezoidal_window_11265: Menuiserie 9.2; Hauteur sous linteau: 406.7 cm; ID du type: fixed_trapezoidal_window_11265: Menuiserie 9.2; Type: fixed_trapezoidal_window_11265: Menuiserie 9.2
Contraintes - Niveau: Niveau: 0 RDC; Hauteur de l'appui: 330.8 cm
Cotes - Surface: 1.44629 m2; Volume: 0.0350787 m3
Données d'identification - Identifiant: 82
Phase de construction - Phase de création: Projet

# IfcWindow: Menuiserie 9.3, fixed_trapezoidal_window_11265:Menuiserie 9.3:1876426
In: 0 RDC
Type - ParameterTakesPrecedence: no; Sizeable: no; Classification: B2020100 Windows (Uniformat); Material: Verre, Aluminium
Type - Autre - Catégorie: Fenêtres; Nom de la famille: fixed_trapezoidal_window_11265
Type - Construction - Fermeture du mur: Par hôte
Type - Cotes - Default Sill Height: 121.92 cm; Hauteur: 67.5 cm; Largeur: 110 cm; slope to 12: 0.733951; top slope: 3.5 deg; Window Inset: 5 cm
Type - Données d'identification - Code d'assemblage: B2020100; Description de l'assemblage: Windows; Marque de type: 56; Nom du type: Menuiserie 9.3; Note d'identification: Paroi vitrée; Numéro OmniClass: 23.30.20.17.11; Titre OmniClass: Fixed Windows
Type - Matériaux et finitions - Glass Pane Material: Verre; Sash Material: Aluminium
Type - Propriétés analytiques - Coefficient d'apport thermique solaire: 0.56; Coefficient de transfert de chaleur (U): 1.533; Construction analytique: Triple vitrage - 1/4 po. d'épaisseur - verre transparent/transparent/énergétique (e = 0.2); Résistance thermique (R): 0.652316; Transmission de la lumière visible: 0.64
OverallHeight: 67.5 cm; OverallWidth: 110 cm
Pset_QuantityTakeOff - Reference: fixed_trapezoidal_window_11265:Menuiserie 9.3
Pset_WindowCommon - IsExternal: yes; Reference: fixed_trapezoidal_window_11265:Menuiserie 9.3; ThermalTransmittance: 1.533 kg/K/s3
BaseQuantities - Height: 67.5 cm; Width: 110 cm; Area: 0.7425 m2
Autre - ID hôte: Mur de base: Mur exterieur doublé; Famille: fixed_trapezoidal_window_11265: Menuiserie 9.3; Famille et type: fixed_trapezoidal_window_11265: Menuiserie 9.3; Hauteur sous linteau: 406.5 cm; ID du type: fixed_trapezoidal_window_11265: Menuiserie 9.3; Type: fixed_trapezoidal_window_11265: Menuiserie 9.3
Contraintes - Niveau: Niveau: 0 RDC; Hauteur de l'appui: 339 cm
Cotes - Surface: 1.23482 m2; Volume: 0.0307741 m3
Données d'identification - Identifiant: 85
Phase de construction - Phase de création: Projet
